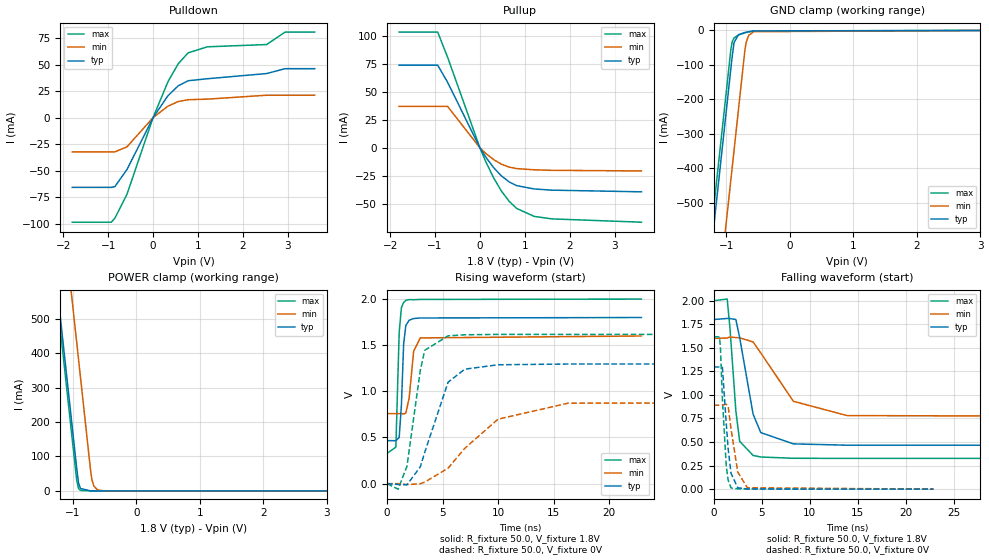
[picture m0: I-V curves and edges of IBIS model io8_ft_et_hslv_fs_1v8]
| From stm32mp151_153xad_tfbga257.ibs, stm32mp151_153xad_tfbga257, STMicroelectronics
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[Model]   io8_ft_et_hslv_fs_1v8
Model_type I/O
Polarity   Non-Inverting
Enable   Active-Low
| CAP_THRESHOLD on pad IOFT is "UDTCAPC" :
| Rising=20.00f vddiom   Falling=80.00f vddiom
| C_comp min and max val. don't necessarily correlate with the min and max pvt
| but are the smallest and greatest pad capacitance found.
| var   typ   min   max
C_comp   3.43098pF  3.42356pF  3.49920pF
|C_comp_pullup   1.96775pF  2.05990pF  1.91900pF
|C_comp_pulldown   1.46323pF  1.36366pF  1.58020pF
Vinl = 640.0mV
Vinh = 1.2V
Vmeas = 900.0mV   | Reference voltage for timing measurements
Cref  = 50.0pF   | Timing specification test load capacitance value
Rref  = 100.0MOhm   | Timing specification test load resistance value
Vref  = 0V   | Timing specification test load voltage
[Model Spec]
| TIME_THRESHOLD on pin ZIV11 is "CMOS" :
| Rising=40.00f vdd   Falling=60.00f vdd
Vinl 738.60000mV 665.60000mV 824.60000mV
Vinh 1.04640V 924.40000mV 1.13940V
| variable   typ   min   max
[Temperature Range] 25.0 140.0 -40.0
| variable   typ   min   max
[Voltage Range] 1.8V 1.6V 2.0V
| variable   typ   min   max
[POWER Clamp Reference] 1.8V 1.6V 2.0V
| variable   typ   min   max
[GND Clamp Reference] 0V 0V 0V
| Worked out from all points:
|   slope of the pulldown table from 0 to 0.27 V, typ, clamps not added: 16 ohm
|   slope of the pullup table from 0 to 0.27 V, typ, clamps not added: 17 ohm
|   GND clamp passes 1 mA (typ) near -0.52 V on its own axis
|   POWER clamp passes 1 mA (typ) near -0.83 V on its own axis
|   rising waveform, R_fixture 50.0, V_fixture 1.8V: 20-80 % time 262ps typ, 401ps min, 226ps max; typ from 0.466 V to 1.8 V
|   falling waveform, R_fixture 50.0, V_fixture 1.8V: 20-80 % time 1.42ns typ, 3.39ns min, 737ps max; typ from 1.8 V to 0.466 V
|   rising waveform, R_fixture 50.0, V_fixture 0V: 20-80 % time 2.03ns typ, 4.63ns min, 1.08ns max; typ from 0 V to 1.3 V
|   falling waveform, R_fixture 50.0, V_fixture 0V: 20-80 % time 599ps typ, 793ps min, 479ps max; typ from 1.3 V to 0 V
[POWER Clamp]
-1.8V     1.529A     1.894A     1.494A
-940mV    66.83mA    432.1mA    31.5mA
-910mV    22.88mA    381.1mA    7.077mA
-880mV    7.117mA    330.1mA    1.59mA
-720mV    14.05uA    58.12mA    554nA
-700mV    6.453uA    33.14mA    205nA
-670mV    2.008uA    14.27mA    46.29nA
-610mV    195.5nA    2.645mA    2.508nA
-500mV    3.96nA     120.4uA    139.7pA
3.6V      0A         0A         0A
[GND Clamp]
-1.8V     -1.588A    -1.91A     -1.533A
-1.26V    -670.3mA   -992.4mA   -614.9mA
-1.2V     -568.3mA   -890.4mA   -512.9mA
-930mV    -109.3mA   -431.4mA   -53.86mA
-910mV    -75.33mA   -397.4mA   -32.91mA
-880mV    -34.88mA   -346.4mA   -21.56mA
-810mV    -12.56mA   -227.4mA   -13.55mA
-710mV    -6.275mA   -57.63mA   -7.234mA
-690mV    -5.461mA   -35.21mA   -6.234mA
-650mV    -4.039mA   -14.43mA   -4.463mA
-570mV    -1.908mA   -3.832mA   -1.869mA
3.6V      5.084nA    1.599uA    245.6pA
| variable   typ   min   max
[Pullup Reference] 1.8V 1.6V 2.0V
| variable   typ   min   max
[Pulldown Reference] 0V 0V 0V
[Pullup]
-1.8V     73.6mA     36.9mA     103.1mA
-940mV    73.6mA     36.9mA     103.1mA
-720mV    58.44mA    36.9mA     80.78mA
0V        7.41pA     1.331nA    4.294pA
140mV     -8.79mA    -5.35mA    -13.15mA
310mV     -17.86mA   -10.65mA   -27.08mA
480mV     -25.08mA   -14.62mA   -38.59mA
650mV     -30.37mA   -17.22mA   -47.59mA
820mV     -33.72mA   -18.55mA   -54.08mA
1.21V     -36.68mA   -19.61mA   -61.13mA
1.6V      -37.75mA   -20.08mA   -63.35mA
3.6V      -39.24mA   -20.63mA   -66.3mA
[Pulldown]
-1.8V     -65.8mA    -32.31mA   -98.64mA
-930mV    -65.8mA    -32.31mA   -98.64mA
-850mV    -65.04mA   -32.31mA   -94.81mA
-580mV    -48.83mA   -27.49mA   -72.14mA
0V        0A         -3pA       0A
330mV     20.59mA    10.79mA    33.74mA
560mV     30.02mA    15.15mA    50.81mA
780mV     34.81mA    16.9mA     61.1mA
1.21V     36.69mA    17.44mA    66.81mA
2.53V     41.58mA    21.14mA    68.95mA
2.94V     46.18mA    21.14mA    80.69mA
3.6V      46.18mA    21.14mA    80.69mA
[Ramp]
dV/dt_r 777.92791mV/2.02837ns 534.21504mV/4.63418ns 970.12816mV/1.08189ns
dV/dt_f 800.59662mV/1.41649ns 504.71748mV/3.38638ns 1.00395V/732.27748ps
R_load = 50.0
| Removed startup time: 0s 0s 0s  .
| Removed end time: 22.9ns.
[Rising Waveform]
R_fixture   = 50.0
V_fixture   = 1.8V
V_fixture_min = 1.6V
V_fixture_max = 2.0V
0s        465.7mV    758.8mV    326.7mV
800ps     465.4mV    758.9mV    395.8mV
1.1ns     499.2mV    758.9mV    1.64V
1.3ns     850.8mV    759.2mV    1.907V
1.5ns     1.512V     754.2mV    1.963V
1.7ns     1.714V     764.7mV    1.986V
2ns       1.771V     930.4mV    1.994V
2.4ns     1.789V     1.434V     1.993V
3ns       1.795V     1.579V     1.996V
22.9ns    1.8V       1.6V       2V
| Removed startup time: 0s 0s 0s  .
| Removed end time: 99.9ns.
[Falling Waveform]
R_fixture   = 50.0
V_fixture   = 1.8V
V_fixture_min = 1.6V
V_fixture_max = 2.0V
0s        1.8V       1.6V       2V
1.4ns     1.811V     1.603V     2.017V
1.7ns     1.81V      1.615V     1.695V
2.3ns     1.8V       1.608V     831.8mV
2.7ns     1.608V     1.606V     508mV
4.1ns     795.5mV    1.562V     357.7mV
4.9ns     600.2mV    1.445V     341.4mV
8.3ns     480.5mV    932.2mV    327.7mV
13.9ns    466.5mV    780.6mV    326.7mV
99.9ns    465.7mV    758.8mV    326.8mV
| Removed startup time: 0s 0s 0s  .
| Removed end time: 99.9ns.
[Rising Waveform]
R_fixture   = 50.0
V_fixture   = 0V
V_fixture_min = 0V
V_fixture_max = 0V
0s        100.1nV    -275.4nV   -4.987uV
1ns       -9.304mV   -93.83uV   -60.01mV
1.8ns     -12.88mV   -10.38mV   188.5mV
3ns       181.7mV    -1.667mV   1.228V
3.4ns     339.4mV    16.35mV    1.445V
5.5ns     1.099V     167.5mV    1.601V
7ns       1.24V      382.3mV    1.613V
10ns      1.288V     698.6mV    1.617V
16.3ns    1.296V     871.6mV    1.617V
99.9ns    1.297V     890.4mV    1.617V
| Removed startup time: 0s 0s 0s  .
| Removed end time: 22.9ns.
[Falling Waveform]
R_fixture   = 50.0
V_fixture   = 0V
V_fixture_min = 0V
V_fixture_max = 0V
0s        1.297V     890.4mV    1.617V
600ps     1.296V     890.5mV    1.615V
700ps     1.298V     890.5mV    1.49V
900ps     1.291V     890.6mV    953.1mV
1.3ns     697.7mV    901.5mV    249mV
1.5ns     428.2mV    878.7mV    95.13mV
1.8ns     167.9mV    637.3mV    12.87mV
2.5ns     14.43mV    181.4mV    2.639mV
3.5ns     2.73mV     15.03mV    1.331mV
22.9ns    999.6nV    9.911uV    -8.613nV
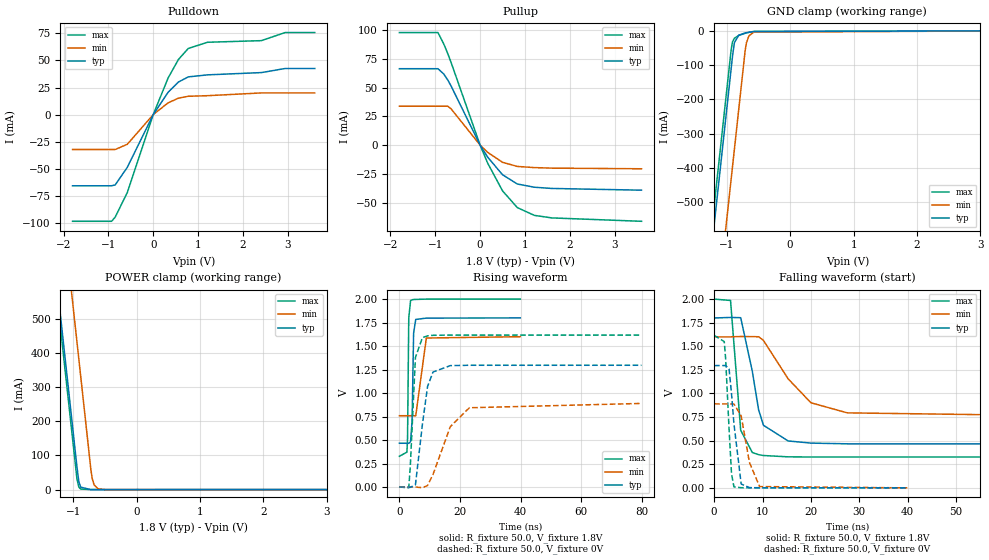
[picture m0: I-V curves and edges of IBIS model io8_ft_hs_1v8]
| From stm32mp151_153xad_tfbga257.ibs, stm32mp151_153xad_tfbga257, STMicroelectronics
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[Model]   io8_ft_hs_1v8
Model_type I/O
Polarity   Non-Inverting
Enable   Active-Low
| CAP_THRESHOLD on pad IOFT is "UDTCAPC" :
| Rising=20.00f vddiom   Falling=80.00f vddiom
| C_comp min and max val. don't necessarily correlate with the min and max pvt
| but are the smallest and greatest pad capacitance found.
| var   typ   min   max
C_comp   3.43303pF  3.42726pF  3.49995pF
|C_comp_pullup   1.98355pF  2.07755pF  1.93335pF
|C_comp_pulldown   1.44948pF  1.34971pF  1.56660pF
Vinl = 640.0mV
Vinh = 1.2V
Vmeas = 900.0mV   | Reference voltage for timing measurements
Cref  = 50.0pF   | Timing specification test load capacitance value
Rref  = 100.0MOhm   | Timing specification test load resistance value
Vref  = 0V   | Timing specification test load voltage
[Model Spec]
| TIME_THRESHOLD on pin ZIV11 is "CMOS" :
| Rising=40.00f vdd   Falling=60.00f vdd
Vinl 738.60000mV 665.60000mV 824.60000mV
Vinh 1.04640V 924.40000mV 1.13940V
| variable   typ   min   max
[Temperature Range] 25.0 140.0 -40.0
| variable   typ   min   max
[Voltage Range] 1.8V 1.6V 2.0V
| variable   typ   min   max
[POWER Clamp Reference] 1.8V 1.6V 2.0V
| variable   typ   min   max
[GND Clamp Reference] 0V 0V 0V
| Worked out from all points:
|   slope of the pulldown table from 0 to 0.27 V, typ, clamps not added: 16 ohm
|   slope of the pullup table from 0 to 0.27 V, typ, clamps not added: 17 ohm
|   GND clamp passes 1 mA (typ) near -0.52 V on its own axis
|   POWER clamp passes 1 mA (typ) near -0.83 V on its own axis
|   rising waveform, R_fixture 50.0, V_fixture 1.8V: 20-80 % time 390ps typ, 807ps min, 283ps max; typ from 0.466 V to 1.8 V
|   falling waveform, R_fixture 50.0, V_fixture 1.8V: 20-80 % time 2.78ns typ, 6.86ns min, 1.4ns max; typ from 1.8 V to 0.466 V
|   rising waveform, R_fixture 50.0, V_fixture 0V: 20-80 % time 2.79ns typ, 6.53ns min, 1.35ns max; typ from 0 V to 1.3 V
|   falling waveform, R_fixture 50.0, V_fixture 0V: 20-80 % time 1.34ns typ, 2.04ns min, 926ps max; typ from 1.3 V to 0 V
[POWER Clamp]
-1.8V     1.529A     1.894A     1.494A
-940mV    66.83mA    432.1mA    31.5mA
-910mV    22.88mA    381.1mA    7.077mA
-880mV    7.117mA    330.1mA    1.59mA
-720mV    14.05uA    58.12mA    554nA
-700mV    6.453uA    33.14mA    205nA
-670mV    2.008uA    14.27mA    46.28nA
-610mV    195.3nA    2.645mA    2.497nA
-500mV    3.855nA    120.4uA    130.5pA
3.6V      0A         0A         0A
[GND Clamp]
-1.8V     -1.588A    -1.91A     -1.533A
-1.26V    -670.3mA   -992.4mA   -614.9mA
-1.2V     -568.3mA   -890.4mA   -512.9mA
-930mV    -109.3mA   -431.4mA   -53.86mA
-910mV    -75.33mA   -397.4mA   -32.91mA
-880mV    -34.88mA   -346.4mA   -21.56mA
-810mV    -12.56mA   -227.4mA   -13.55mA
-710mV    -6.275mA   -57.63mA   -7.234mA
-690mV    -5.461mA   -35.21mA   -6.234mA
-650mV    -4.039mA   -14.43mA   -4.463mA
-570mV    -1.908mA   -3.832mA   -1.869mA
3.6V      5.036nA    1.588uA    245.5pA
| variable   typ   min   max
[Pullup Reference] 1.8V 1.6V 2.0V
| variable   typ   min   max
[Pulldown Reference] 0V 0V 0V
[Pullup]
-1.8V     66.33mA    33.75mA    97.74mA
-940mV    66.33mA    33.75mA    97.74mA
-810mV    61.74mA    33.75mA    87.84mA
-720mV    56.47mA    33.75mA    79.39mA
-650mV    51.56mA    31.62mA    72.14mA
0V        7.41pA     1.33nA     4.294pA
170mV     -10.52mA   -6.378mA   -15.77mA
500mV     -25.79mA   -14.99mA   -39.76mA
830mV     -33.83mA   -18.58mA   -54.35mA
1.21V     -36.65mA   -19.59mA   -61.09mA
1.6V      -37.71mA   -20.06mA   -63.31mA
3.6V      -39.21mA   -20.61mA   -66.25mA
[Pulldown]
-1.8V     -65.8mA    -32.31mA   -98.64mA
-930mV    -65.8mA    -32.31mA   -98.64mA
-850mV    -65.04mA   -32.31mA   -94.81mA
-580mV    -48.83mA   -27.49mA   -72.14mA
0V        0A         0A         0A
330mV     20.59mA    10.79mA    33.74mA
560mV     30.02mA    15.15mA    50.81mA
780mV     34.81mA    16.9mA     61.1mA
1.21V     36.69mA    17.44mA    66.81mA
2.41V     38.78mA    19.98mA    68.31mA
2.94V     42.55mA    19.98mA    75.77mA
3.6V      42.55mA    19.98mA    75.77mA
[Ramp]
dV/dt_r 777.74465mV/2.79218ns 533.89794mV/6.53451ns 970.01034mV/1.35361ns
dV/dt_f 800.598mV/2.77438ns 504.72922mV/6.86444ns 1.00395V/1.39597ns
R_load = 50.0
| Removed startup time: 0s 0s 0s  .
| Removed end time: 39.9ns.
[Rising Waveform]
R_fixture   = 50.0
V_fixture   = 1.8V
V_fixture_min = 1.6V
V_fixture_max = 2.0V
0s        465.7mV    758.8mV    326.8mV
2.5ns     465.7mV    758.8mV    371.3mV
2.7ns     465.7mV    758.8mV    526.8mV
3.1ns     464.9mV    758.8mV    1.799V
3.7ns     482.8mV    758.8mV    1.985V
4.2ns     708.1mV    758.8mV    1.993V
4.7ns     1.639V     758.9mV    1.996V
5.4ns     1.784V     758mV      1.997V
8.9ns     1.798V     1.586V     2V
39.9ns    1.8V       1.6V       2V
| Removed startup time: 0s 0s 0s  .
| Removed end time: 79.9ns.
[Falling Waveform]
R_fixture   = 50.0
V_fixture   = 1.8V
V_fixture_min = 1.6V
V_fixture_max = 2.0V
0s        1.8V       1.6V       2V
3.4ns     1.806V     1.6V       1.986V
5.5ns     1.803V     1.604V     610.5mV
7.9ns     1.234V     1.603V     374mV
9.2ns     825.6mV    1.601V     351.8mV
10.2ns    663mV      1.562V     342.8mV
15.3ns    497mV      1.155V     328.7mV
20ns      474.3mV    901.8mV    327mV
27.5ns    466.7mV    794.7mV    326.8mV
79.9ns    465.7mV    758.8mV    326.8mV
| Removed startup time: 0s 0s 0s  .
| Removed end time: 79.9ns.
[Rising Waveform]
R_fixture   = 50.0
V_fixture   = 0V
V_fixture_min = 0V
V_fixture_max = 0V
0s        69.77nV    639.1nV    99.37nV
3.1ns     201.2uV    665.7nV    -9.143mV
3.6ns     -3.771mV   740.3nV    217.4mV
5.3ns     23.01mV    145.7uV    1.379V
7.6ns     665.8mV    -8.11mV    1.59V
9.3ns     1.069V     15.34mV    1.609V
11.1ns    1.224V     133.5mV    1.615V
16.8ns    1.292V     642.6mV    1.617V
23.1ns    1.296V     843.5mV    1.617V
79.9ns    1.296V     889.8mV    1.617V
| Removed startup time: 0s 0s 0s  .
| Removed end time: 39.9ns.
[Falling Waveform]
R_fixture   = 50.0
V_fixture   = 0V
V_fixture_min = 0V
V_fixture_max = 0V
0s        1.296V     889.9mV    1.617V
2.1ns     1.296V     889.9mV    1.55V
2.4ns     1.296V     889.9mV    1.359V
3.1ns     1.258V     889.9mV    617mV
3.6ns     1.001V     889.9mV    151.1mV
4.1ns     680mV      889.6mV    10.38mV
5.6ns     40.3mV     762.2mV    1.601mV
7.3ns     2.759mV    269.1mV    761.2uV
9.4ns     1.116mV    13.7mV     339.6uV
39.9ns    -1.056uV   11.69uV    88.63nV
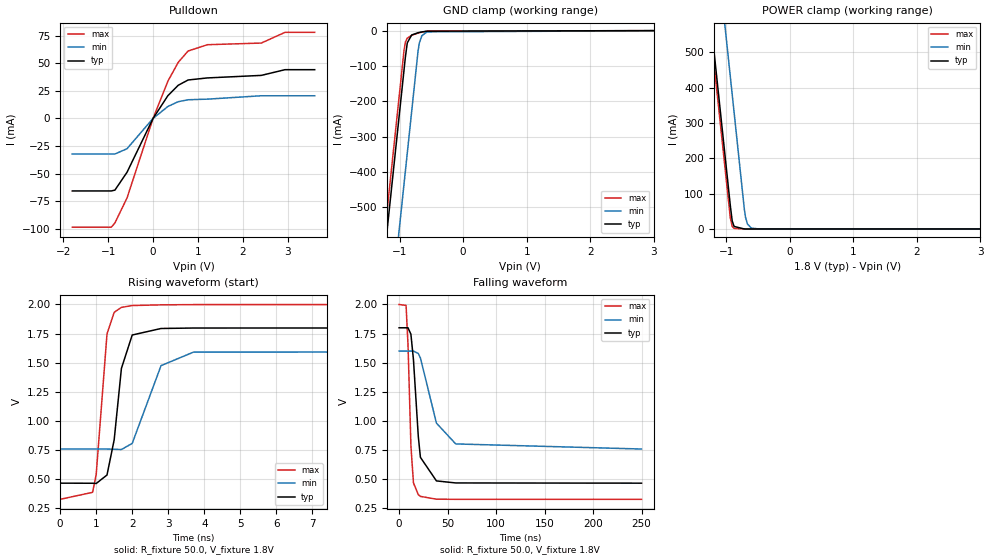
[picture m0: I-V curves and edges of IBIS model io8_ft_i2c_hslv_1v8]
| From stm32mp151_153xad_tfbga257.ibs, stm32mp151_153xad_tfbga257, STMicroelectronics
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[Model]   io8_ft_i2c_hslv_1v8
Model_type I/O_open_drain
Polarity   Non-Inverting
Enable   Active-Low
| CAP_THRESHOLD on pad IOFT is "UDTCAPC" :
| Rising=20.00f vddiom   Falling=80.00f vddiom
| C_comp min and max val. don't necessarily correlate with the min and max pvt
| but are the smallest and greatest pad capacitance found.
| var   typ   min   max
C_comp   3.45148pF  3.42528pF  3.49355pF
|C_comp_pulldown   3.45148pF  3.42528pF  3.49355pF
Vinl = 640.0mV
Vinh = 1.2V
Vmeas = 900.0mV   | Reference voltage for timing measurements
Cref  = 50.0pF   | Timing specification test load capacitance value
Rref  = 100.0MOhm   | Timing specification test load resistance value
Vref  = 900.0mV   | Timing specification test load voltage
[Model Spec]
| TIME_THRESHOLD on pin ZIV11 is "CMOS" :
| Rising=40.00f vdd   Falling=60.00f vdd
Vinl 738.60000mV 665.60000mV 824.60000mV
Vinh 1.04740V 925.40000mV 1.14040V
| variable   typ   min   max
[Temperature Range] 25.0 140.0 -40.0
| variable   typ   min   max
[Voltage Range] 1.8V 1.6V 2.0V
| variable   typ   min   max
[POWER Clamp Reference] 1.8V 1.6V 2.0V
| variable   typ   min   max
[GND Clamp Reference] 0V 0V 0V
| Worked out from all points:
|   slope of the pulldown table from 0 to 0.27 V, typ, clamps not added: 16 ohm
|   GND clamp passes 1 mA (typ) near -0.52 V on its own axis
|   POWER clamp passes 1 mA (typ) near -0.83 V on its own axis
|   rising waveform, R_fixture 50.0, V_fixture 1.8V: 20-80 % time 303ps typ, 522ps min, 243ps max; typ from 0.466 V to 1.8 V
|   falling waveform, R_fixture 50.0, V_fixture 1.8V: 20-80 % time 6.49ns typ, 15.7ns min, 3.61ns max; typ from 1.8 V to 0.466 V
[POWER Clamp]
-1.8V     1.529A     1.894A     1.494A
-940mV    66.83mA    432.1mA    31.5mA
-910mV    22.88mA    381.1mA    7.077mA
-880mV    7.117mA    330.1mA    1.59mA
-720mV    14.05uA    58.12mA    554nA
-700mV    6.453uA    33.14mA    205nA
-670mV    2.008uA    14.27mA    46.28nA
-610mV    195.3nA    2.645mA    2.496nA
-500mV    3.825nA    120.4uA    129.9pA
3.6V      0A         0A         0A
[GND Clamp]
-1.8V     -1.588A    -1.91A     -1.533A
-1.26V    -670.3mA   -992.4mA   -614.9mA
-1.2V     -568.3mA   -890.4mA   -512.9mA
-930mV    -109.3mA   -431.4mA   -53.86mA
-910mV    -75.33mA   -397.4mA   -32.91mA
-880mV    -34.88mA   -346.4mA   -21.56mA
-810mV    -12.56mA   -227.4mA   -13.55mA
-710mV    -6.275mA   -57.63mA   -7.234mA
-690mV    -5.461mA   -35.21mA   -6.234mA
-650mV    -4.039mA   -14.43mA   -4.463mA
-570mV    -1.908mA   -3.832mA   -1.869mA
3.6V      5.036nA    1.588uA    245.5pA
| variable   typ   min   max
[Pullup Reference] 1.8V 1.6V 2.0V
| variable   typ   min   max
[Pulldown Reference] 0V 0V 0V
[Pulldown]
-1.8V     -65.8mA    -32.31mA   -98.64mA
-930mV    -65.8mA    -32.31mA   -98.64mA
-850mV    -65.04mA   -32.31mA   -94.81mA
-580mV    -48.83mA   -27.49mA   -72.14mA
0V        0A         -2pA       0A
330mV     20.59mA    10.79mA    33.74mA
560mV     30.02mA    15.15mA    50.81mA
780mV     34.81mA    16.9mA     61.1mA
1.21V     36.69mA    17.44mA    66.81mA
2.41V     38.98mA    20.51mA    68.31mA
2.94V     44.17mA    20.51mA    78.04mA
3.6V      44.17mA    20.51mA    78.04mA
[Ramp]
dV/dt_r 800.58575mV/285.51296ps 504.68813mV/515.06486ps 1.00394V/226.53402ps
dV/dt_f 800.59773mV/6.49286ns 504.7021mV/15.74821ns 1.00395V/3.60901ns
R_load = 50.0
| Removed startup time: 0s 0s 0s  .
| Removed end time: 59.9ns.
[Rising Waveform]
R_fixture   = 50.0
V_fixture   = 1.8V
V_fixture_min = 1.6V
V_fixture_max = 2.0V
0s        465.7mV    758.8mV    326.7mV
900ps     464.8mV    758.9mV    386.8mV
1ns       462.7mV    758.9mV    539.3mV
1.3ns     535.5mV    758.5mV    1.747V
1.5ns     839mV      756.8mV    1.933V
1.7ns     1.451V     754.5mV    1.975V
2ns       1.738V     807.3mV    1.991V
2.8ns     1.794V     1.475V     1.997V
3.7ns     1.798V     1.591V     1.999V
59.9ns    1.8V       1.6V       2V
| Removed startup time: 0s 0s 0s  .
| Removed end time: 249.9ns.
[Falling Waveform]
R_fixture   = 50.0
V_fixture   = 1.8V
V_fixture_min = 1.6V
V_fixture_max = 2.0V
0s        1.8V       1.6V       2V
7.2ns     1.8V       1.6V       1.992V
9.2ns     1.8V       1.6V       1.655V
12.2ns    1.744V     1.6V       788.3mV
14.8ns    1.528V     1.6V       467.8mV
19.8ns    867.6mV    1.579V     366.9mV
22ns      687.3mV    1.541V     352.1mV
38.5ns    485mV      981.3mV    328mV
58.4ns    467.5mV    802.6mV    326.8mV
249.9ns   465.7mV    758.8mV    326.8mV
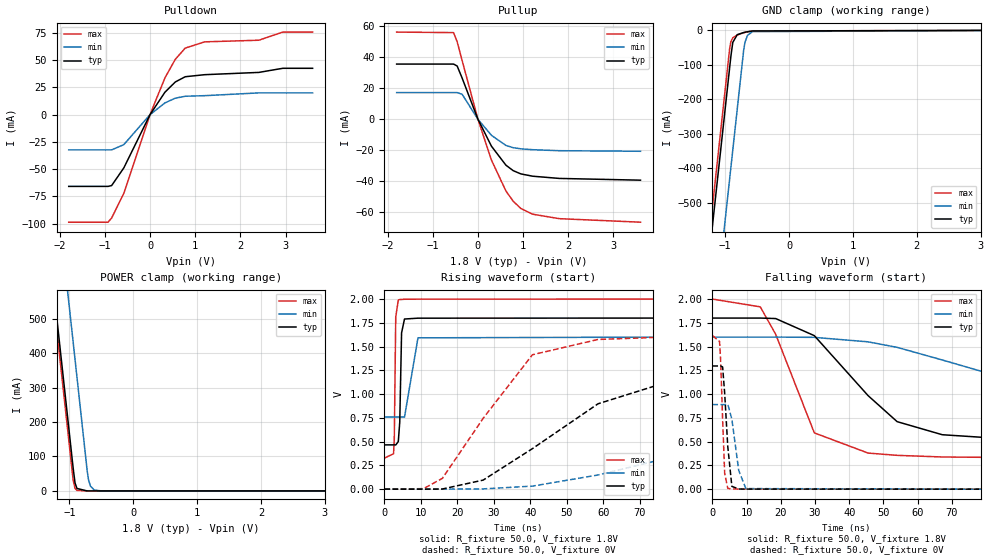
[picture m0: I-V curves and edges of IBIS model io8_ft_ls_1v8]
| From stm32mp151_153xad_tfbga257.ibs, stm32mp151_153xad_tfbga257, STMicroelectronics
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[Model]   io8_ft_ls_1v8
Model_type I/O
Polarity   Non-Inverting
Enable   Active-Low
| CAP_THRESHOLD on pad IOFT is "UDTCAPC" :
| Rising=20.00f vddiom   Falling=80.00f vddiom
| C_comp min and max val. don't necessarily correlate with the min and max pvt
| but are the smallest and greatest pad capacitance found.
| var   typ   min   max
C_comp   3.43303pF  3.42726pF  3.49995pF
|C_comp_pullup   1.98355pF  2.07755pF  1.93335pF
|C_comp_pulldown   1.44948pF  1.34971pF  1.56660pF
Vinl = 640.0mV
Vinh = 1.2V
Vmeas = 900.0mV   | Reference voltage for timing measurements
Cref  = 50.0pF   | Timing specification test load capacitance value
Rref  = 100.0MOhm   | Timing specification test load resistance value
Vref  = 0V   | Timing specification test load voltage
[Model Spec]
| TIME_THRESHOLD on pin ZIV11 is "CMOS" :
| Rising=40.00f vdd   Falling=60.00f vdd
Vinl 738.60000mV 665.60000mV 824.60000mV
Vinh 1.04640V 924.40000mV 1.13940V
| variable   typ   min   max
[Temperature Range] 25.0 140.0 -40.0
| variable   typ   min   max
[Voltage Range] 1.8V 1.6V 2.0V
| variable   typ   min   max
[POWER Clamp Reference] 1.8V 1.6V 2.0V
| variable   typ   min   max
[GND Clamp Reference] 0V 0V 0V
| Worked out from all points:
|   slope of the pulldown table from 0 to 0.27 V, typ, clamps not added: 16 ohm
|   slope of the pullup table from 0 to 0.27 V, typ, clamps not added: 17 ohm
|   GND clamp passes 1 mA (typ) near -0.52 V on its own axis
|   POWER clamp passes 1 mA (typ) near -0.83 V on its own axis
|   rising waveform, R_fixture 50.0, V_fixture 1.8V: 20-80 % time 386ps typ, 812ps min, 279ps max; typ from 0.466 V to 1.8 V
|   falling waveform, R_fixture 50.0, V_fixture 1.8V: 20-80 % time 20.5ns typ, 52.9ns min, 10.5ns max; typ from 1.8 V to 0.466 V
|   rising waveform, R_fixture 50.0, V_fixture 0V: 20-80 % time 31.3ns typ, 68.1ns min, 16.6ns max; typ from 0 V to 1.3 V
|   falling waveform, R_fixture 50.0, V_fixture 0V: 20-80 % time 1.33ns typ, 2.04ns min, 927ps max; typ from 1.3 V to 0 V
[POWER Clamp]
-1.8V     1.529A     1.894A     1.494A
-940mV    66.83mA    432.1mA    31.5mA
-910mV    22.88mA    381.1mA    7.077mA
-880mV    7.117mA    330.1mA    1.59mA
-720mV    14.05uA    58.12mA    554nA
-700mV    6.453uA    33.14mA    205nA
-670mV    2.008uA    14.27mA    46.28nA
-610mV    195.3nA    2.645mA    2.497nA
-500mV    3.855nA    120.4uA    130.5pA
3.6V      0A         0A         0A
[GND Clamp]
-1.8V     -1.588A    -1.91A     -1.533A
-1.26V    -670.3mA   -992.4mA   -614.9mA
-1.2V     -568.3mA   -890.4mA   -512.9mA
-930mV    -109.3mA   -431.4mA   -53.86mA
-910mV    -75.33mA   -397.4mA   -32.91mA
-880mV    -34.88mA   -346.4mA   -21.56mA
-810mV    -12.56mA   -227.4mA   -13.55mA
-710mV    -6.275mA   -57.63mA   -7.234mA
-690mV    -5.461mA   -35.21mA   -6.234mA
-650mV    -4.039mA   -14.43mA   -4.463mA
-570mV    -1.908mA   -3.832mA   -1.869mA
3.6V      5.036nA    1.588uA    245.5pA
| variable   typ   min   max
[Pullup Reference] 1.8V 1.6V 2.0V
| variable   typ   min   max
[Pulldown Reference] 0V 0V 0V
[Pullup]
-1.8V     35.51mA    17.15mA    56.1mA
-540mV    35.51mA    17.15mA    55.76mA
-460mV    34.27mA    17.15mA    49.89mA
-350mV    26.52mA    16.08mA    37.78mA
0V        7.41pA     1.33nA     4.294pA
300mV     -17.37mA   -10.37mA   -26.31mA
620mV     -29.56mA   -16.84mA   -46.16mA
780mV     -33.07mA   -18.31mA   -52.74mA
950mV     -35.16mA   -19.03mA   -57.42mA
1.21V     -36.65mA   -19.59mA   -61.09mA
1.8V      -38.08mA   -20.24mA   -63.98mA
3.6V      -39.21mA   -20.61mA   -66.25mA
[Pulldown]
-1.8V     -65.8mA    -32.31mA   -98.64mA
-930mV    -65.8mA    -32.31mA   -98.64mA
-850mV    -65.04mA   -32.31mA   -94.81mA
-580mV    -48.83mA   -27.49mA   -72.14mA
0V        0A         0A         0A
330mV     20.59mA    10.79mA    33.74mA
560mV     30.02mA    15.15mA    50.81mA
780mV     34.81mA    16.9mA     61.1mA
1.21V     36.69mA    17.44mA    66.81mA
2.41V     38.78mA    19.98mA    68.31mA
2.94V     42.55mA    19.98mA    75.77mA
3.6V      42.55mA    19.98mA    75.77mA
[Ramp]
dV/dt_r 777.74117mV/31.3108ns 533.85108mV/68.09047ns 970.01164mV/16.60492ns
dV/dt_f 800.59647mV/20.47216ns 504.71835mV/52.86349ns 1.00395V/10.47264ns
R_load = 50.0
| Removed startup time: 0s 0s 0s  .
| Removed end time: 79.9ns.
[Rising Waveform]
R_fixture   = 50.0
V_fixture   = 1.8V
V_fixture_min = 1.6V
V_fixture_max = 2.0V
0s        465.7mV    758.8mV    326.8mV
2.5ns     465.7mV    758.8mV    372.2mV
2.7ns     465.7mV    758.8mV    528.3mV
3.1ns     464.7mV    758.8mV    1.811V
3.8ns     500.4mV    758.8mV    1.99V
4.2ns     705.4mV    758.8mV    1.995V
4.7ns     1.644V     758.9mV    1.996V
5.5ns     1.79V      757.2mV    1.998V
9.2ns     1.799V     1.592V     1.999V
79.9ns    1.8V       1.6V       2V
| Removed startup time: 0s 0s 0s  .
| Removed end time: 499.9ns.
[Falling Waveform]
R_fixture   = 50.0
V_fixture   = 1.8V
V_fixture_min = 1.6V
V_fixture_max = 2.0V
0s        1.8V       1.6V       2V
14ns      1.8V       1.6V       1.918V
18.5ns    1.795V     1.6V       1.63V
29.8ns    1.615V     1.597V     592mV
45.5ns    984.5mV    1.55V      379.7mV
54ns      710.3mV    1.492V     355.8mV
67.2ns    572.7mV    1.359V     338.5mV
103.9ns   487.2mV    976.8mV    328.1mV
155.9ns   468.5mV    816.4mV    326.8mV
499.9ns   465.7mV    758.8mV    326.8mV
| Removed startup time: 0s 0s 0s  .
| Removed end time: 499.9ns.
[Rising Waveform]
R_fixture   = 50.0
V_fixture   = 0V
V_fixture_min = 0V
V_fixture_max = 0V
0s        70.65nV    639.3nV    101.1nV
10.7ns    -400.3uV   -253.8uV   4.898mV
15.9ns    1.402mV    -125.8uV   113.4mV
27.1ns    95.32mV    2.513mV    746mV
40.6ns    426.1mV    31.69mV    1.414V
58.6ns    898.1mV    148.8mV    1.575V
84.9ns    1.214V     393.5mV    1.61V
122.8ns   1.282V     675.9mV    1.616V
168.2ns   1.294V     824.8mV    1.617V
499.9ns   1.296V     889.8mV    1.617V
| Removed startup time: 0s 0s 0s  .
| Removed end time: 79.9ns.
[Falling Waveform]
R_fixture   = 50.0
V_fixture   = 0V
V_fixture_min = 0V
V_fixture_max = 0V
0s        1.296V     889.9mV    1.617V
2.1ns     1.296V     889.9mV    1.553V
2.4ns     1.296V     889.9mV    1.369V
3ns       1.286V     889.9mV    736.3mV
3.6ns     1.008V     889.9mV    167.4mV
4.5ns     450.3mV    894.5mV    8.33mV
5.7ns     29.23mV    736.1mV    2.228mV
7.7ns     1.726mV    197.2mV    1.331mV
9.8ns     839.1uV    6.128mV    1.079mV
79.9ns    46.64uV    119.3uV    10.53uV
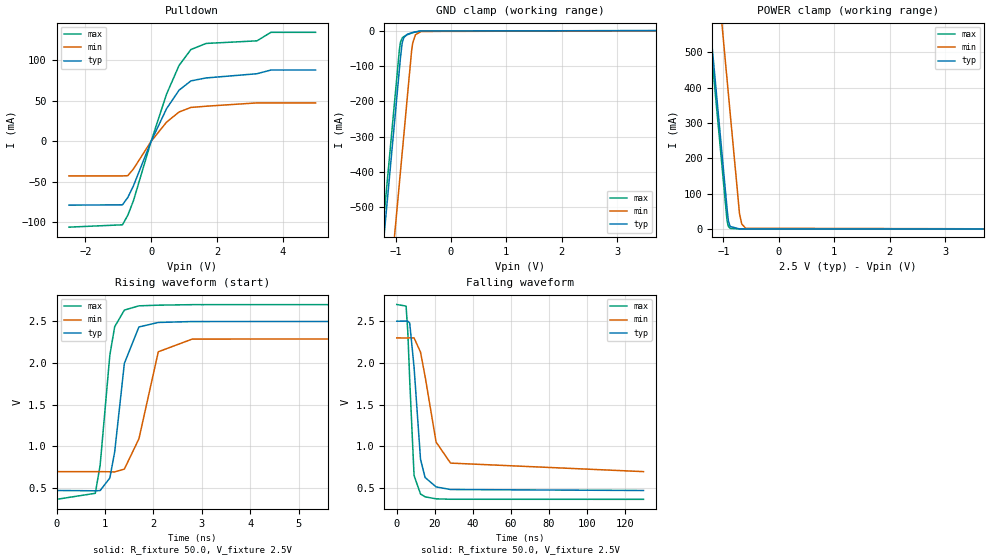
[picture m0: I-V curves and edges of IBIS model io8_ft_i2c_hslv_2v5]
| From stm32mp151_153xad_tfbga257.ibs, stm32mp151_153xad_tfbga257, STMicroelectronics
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[Model]   io8_ft_i2c_hslv_2v5
Model_type I/O_open_drain
Polarity   Non-Inverting
Enable   Active-Low
| CAP_THRESHOLD on pad IOFT is "UDTCAPC" :
| Rising=20.00f vddiom   Falling=80.00f vddiom
| C_comp min and max val. don't necessarily correlate with the min and max pvt
| but are the smallest and greatest pad capacitance found.
| var   typ   min   max
C_comp   3.61949pF  3.58164pF  3.65077pF
|C_comp_pulldown   3.61949pF  3.58164pF  3.65077pF
Vinl = 920.0mV
Vinh = 1.62V
Vmeas = 1.25V   | Reference voltage for timing measurements
Cref  = 50.0pF   | Timing specification test load capacitance value
Rref  = 100.0MOhm   | Timing specification test load resistance value
Vref  = 1.25V   | Timing specification test load voltage
[Model Spec]
| TIME_THRESHOLD on pin ZIV11 is "CMOS" :
| Rising=40.00f vdd   Falling=60.00f vdd
Vinl 1.03860V 964.60000mV 1.11860V
Vinh 1.36440V 1.26340V 1.44240V
| variable   typ   min   max
[Temperature Range] 25.0 140.0 -40.0
| variable   typ   min   max
[Voltage Range] 2.5V 2.3V 2.7V
| variable   typ   min   max
[POWER Clamp Reference] 2.5V 2.3V 2.7V
| variable   typ   min   max
[GND Clamp Reference] 0V 0V 0V
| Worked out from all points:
|   slope of the pulldown table from 0 to 0.375 V, typ, clamps not added: 11.3 ohm
|   GND clamp passes 1 mA (typ) near -0.52 V on its own axis
|   POWER clamp passes 1 mA (typ) near -0.83 V on its own axis
|   rising waveform, R_fixture 50.0, V_fixture 2.5V: 20-80 % time 255ps typ, 328ps min, 233ps max; typ from 0.473 V to 2.5 V
|   falling waveform, R_fixture 50.0, V_fixture 2.5V: 20-80 % time 3.71ns typ, 7.31ns min, 2.47ns max; typ from 2.5 V to 0.473 V
[POWER Clamp]
-2.5V     2.719A     3.084A     2.683A
-1.28V    644.8mA    1.01A      609.5mA
-1.26V    610.8mA    976.1mA    575.5mA
-1.04V    236.8mA    602.1mA    201.5mA
-940mV    66.83mA    432.1mA    31.5mA
-930mV    49.83mA    415.1mA    19.15mA
-910mV    22.88mA    381.1mA    7.077mA
-880mV    7.117mA    330.1mA    1.59mA
-710mV    9.523uA    43.89mA    337nA
-670mV    2.008uA    14.27mA    46.3nA
-600mV    132.9nA    1.998mA    1.599nA
5V        0A         0A         0A
[GND Clamp]
-2.5V     -2.779A    -3.101A    -2.723A
-1.26V    -670.8mA   -992.7mA   -614.5mA
-930mV    -109.8mA   -431.7mA   -53.54mA
-910mV    -75.83mA   -397.7mA   -32.67mA
-880mV    -35.28mA   -346.7mA   -21.39mA
-850mV    -20.07mA   -295.7mA   -16.99mA
-790mV    -10.9mA    -193.7mA   -12.02mA
-710mV    -6.374mA   -57.93mA   -7.219mA
-690mV    -5.545mA   -35.45mA   -6.225mA
-640mV    -3.775mA   -11.96mA   -4.068mA
-540mV    -1.354mA   -2.661mA   -1.223mA
5V        6.965nA    2.133uA    347.4pA
| variable   typ   min   max
[Pullup Reference] 2.5V 2.3V 2.7V
| variable   typ   min   max
[Pulldown Reference] 0V 0V 0V
[Pulldown]
-2.5V     -78.63mA   -42.6mA    -105.8mA
-870mV    -78.28mA   -42.6mA    -102.9mA
-710mV    -69.32mA   -42.37mA   -91.24mA
-540mV    -55.23mA   -34.22mA   -73.64mA
0V        0A         -2pA       0A
470mV     40.29mA    23.69mA    58.27mA
850mV     63.07mA    36.18mA    93.59mA
1.21V     74.52mA    41.78mA    113.2mA
1.67V     78.14mA    43.3mA     120.7mA
3.22V     83.36mA    47.41mA    123.9mA
3.64V     87.89mA    47.41mA    134.4mA
5V        87.89mA    47.41mA    134.4mA
[Ramp]
dV/dt_r 1.21603V/240.53077ps 960.23438mV/318.05663ps 1.39951V/222.49326ps
dV/dt_f 1.21605V/3.71039ns 960.46343mV/7.30327ns 1.39952V/2.47201ns
R_load = 50.0
| Removed startup time: 0s 0s 0s  .
| Removed end time: 35.9ns.
[Rising Waveform]
R_fixture   = 50.0
V_fixture   = 2.5V
V_fixture_min = 2.3V
V_fixture_max = 2.7V
0s        473.2mV    699.2mV    367.4mV
800ps     469.6mV    699.2mV    439.5mV
900ps     472.8mV    699.1mV    776.5mV
1.1ns     622.5mV    697.4mV    2.094V
1.2ns     935.2mV    695.6mV    2.434V
1.4ns     1.995V     729.6mV    2.633V
1.7ns     2.431V     1.092V     2.684V
2.1ns     2.485V     2.134V     2.692V
2.8ns     2.496V     2.286V     2.698V
35.9ns    2.5V       2.3V       2.7V
| Removed startup time: 0s 0s 0s  .
| Removed end time: 129.9ns.
[Falling Waveform]
R_fixture   = 50.0
V_fixture   = 2.5V
V_fixture_min = 2.3V
V_fixture_max = 2.7V
0s        2.5V       2.3V       2.7V
4.9ns     2.501V     2.299V     2.681V
5.8ns     2.5V       2.299V     2.377V
6.8ns     2.479V     2.301V     1.8V
9.1ns     1.949V     2.3V       651.8mV
12.5ns    847.7mV    2.13V      431.3mV
14.9ns    629.1mV    1.839V     397.6mV
20.7ns    516mV      1.053V     373.4mV
28.3ns    485mV      801.2mV    368.4mV
129.9ns   473.2mV    699.2mV    367.5mV
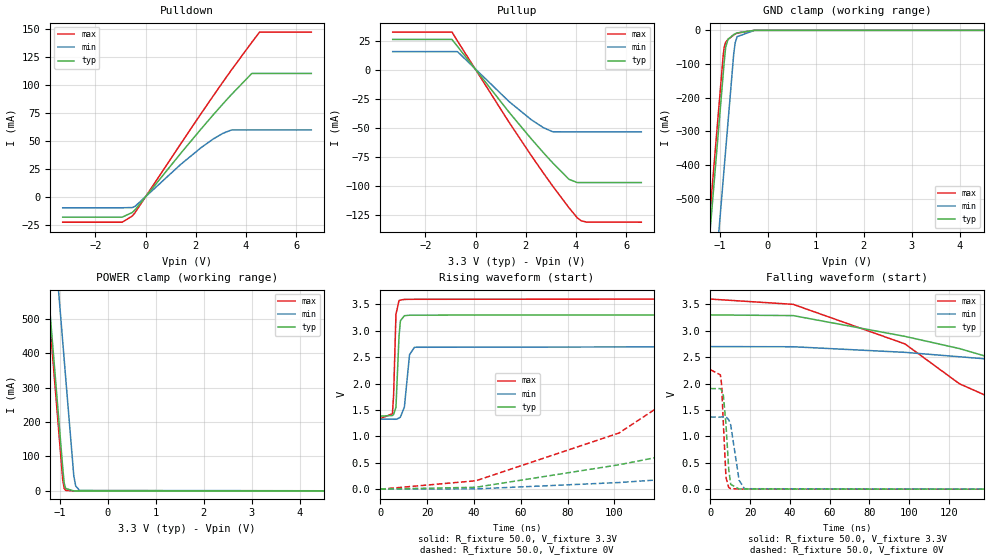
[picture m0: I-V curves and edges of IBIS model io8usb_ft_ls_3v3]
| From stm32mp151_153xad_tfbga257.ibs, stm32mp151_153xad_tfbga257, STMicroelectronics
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[Model]   io8usb_ft_ls_3v3
Model_type I/O
Polarity   Inverting
Enable   Active-Low
| CAP_THRESHOLD on pad DNFT is "UDTCAPC" :
| Rising=20.00f vddiom   Falling=80.00f vddiom
| C_comp min and max val. don't necessarily correlate with the min and max pvt
| but are the smallest and greatest pad capacitance found.
| var   typ   min   max
C_comp   9.38956pF  9.29997pF  9.39296pF
|C_comp_pullup   5.07555pF  4.79110pF  5.26015pF
|C_comp_pulldown   4.31401pF  4.50887pF  4.13281pF
Vinl = 1.08V
Vinh = 2.16V
Vmeas = 1.65V   | Reference voltage for timing measurements
Cref  = 50.0pF   | Timing specification test load capacitance value
Rref  = 100.0MOhm   | Timing specification test load resistance value
Vref  = 0V   | Timing specification test load voltage
[Model Spec]
| TIME_THRESHOLD on pin ZINV11 is "CMOS" :
| Rising=40.00f vdd   Falling=60.00f vdd
Vinl 1.36060V 1.12960V 1.47360V
Vinh 1.71640V 1.45140V 1.83040V
| variable   typ   min   max
[Temperature Range] 25.0 140.0 -40.0
| variable   typ   min   max
[Voltage Range] 3.3V 2.7V 3.6V
| variable   typ   min   max
[POWER Clamp Reference] 3.3V 2.7V 3.6V
| variable   typ   min   max
[GND Clamp Reference] 0V 0V 0V
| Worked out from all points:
|   slope of the pulldown table from 0 to 0.495 V, typ, clamps not added: 35.9 ohm
|   slope of the pullup table from 0 to 0.495 V, typ, clamps not added: 36.4 ohm
|   GND clamp passes 1 mA (typ) near -0.46 V on its own axis
|   POWER clamp passes 1 mA (typ) near -0.83 V on its own axis
|   rising waveform, R_fixture 50.0, V_fixture 3.3V: 20-80 % time 983ps typ, 1.63ns min, 824ps max; typ from 1.38 V to 3.3 V
|   falling waveform, R_fixture 50.0, V_fixture 3.3V: 20-80 % time 95.3ns typ, 181ns min, 67.4ns max; typ from 3.3 V to 1.38 V
|   rising waveform, R_fixture 50.0, V_fixture 0V: 20-80 % time 95.4ns typ, 187ns min, 67.1ns max; typ from 0 V to 1.91 V
|   falling waveform, R_fixture 50.0, V_fixture 0V: 20-80 % time 1.93ns typ, 3.05ns min, 1.5ns max; typ from 1.91 V to 0 V
[POWER Clamp]
-3.3V     4.079A     4.444A     4.043A
-1.46V    950.8mA    1.316A     915.5mA
-1.28V    644.8mA    1.01A      609.5mA
-1.27V    627.8mA    993.1mA    592.5mA
-1.05V    253.8mA    619.1mA    218.5mA
-940mV    66.83mA    432.1mA    31.5mA
-910mV    22.88mA    381.1mA    7.077mA
-880mV    7.117mA    330.1mA    1.59mA
-710mV    9.526uA    43.89mA    337.4nA
-670mV    2.011uA    14.27mA    46.75nA
-590mV    93.56nA    1.508mA    1.48nA
6.6V      0A         0A         0A
[GND Clamp]
-3.3V     -4.158A    -4.471A    -4.102A
-1.25V    -672.7mA   -985.8mA   -617.5mA
-1.1V     -417.7mA   -730.8mA   -362.5mA
-930mV    -128.7mA   -441.8mA   -73.47mA
-910mV    -94.71mA   -407.8mA   -49.55mA
-880mV    -50.68mA   -356.8mA   -35.8mA
-830mV    -26.73mA   -271.8mA   -26.74mA
-710mV    -12.44mA   -67.81mA   -13.64mA
-680mV    -10.24mA   -36.49mA   -11.11mA
-640mV    -7.685mA   -18.75mA   -8.114mA
-280mV    -6.923uA   -112uA     -875.7nA
6.6V      21.96nA    7.413uA    1.058nA
| variable   typ   min   max
[Pullup Reference] 3.3V 2.7V 3.6V
| variable   typ   min   max
[Pulldown Reference] 0V 0V 0V
[Pullup]
-3.3V     26.31mA    15.8mA     32.67mA
-940mV    26.31mA    15.8mA     32.67mA
-720mV    20.29mA    15.8mA     24.95mA
1.33V     -36.39mA   -27.23mA   -45.07mA
2.21V     -59.26mA   -42.82mA   -73.67mA
2.7V      -71.39mA   -49.81mA   -88.96mA
3.07V     -80.17mA   -53.34mA   -100.2mA
3.72V     -94.43mA   -53.42mA   -118.9mA
4.05V     -97.17mA   -53.42mA   -127.7mA
4.21V     -97.19mA   -53.42mA   -130.2mA
4.42V     -97.19mA   -53.42mA   -131.3mA
6.6V      -97.19mA   -53.42mA   -131.4mA
[Pulldown]
-3.3V     -18.2mA    -9.824mA   -22.72mA
-930mV    -18.2mA    -9.824mA   -22.72mA
-530mV    -14.04mA   -9.633mA   -17.24mA
-420mV    -11.67mA   -8.575mA   -14.21mA
1.38V     38.31mA    28.58mA    46.75mA
2.21V     60.64mA    43.95mA    74.4mA
2.7V      73.43mA    51.79mA    90.43mA
3.09V     83.34mA    56.86mA    103mA
3.42V     91.48mA    59.75mA    113.4mA
4.23V     110.3mA    59.75mA    138.2mA
4.54V     110.3mA    59.75mA    147.3mA
6.6V      110.3mA    59.75mA    147.3mA
[Ramp]
dV/dt_r 1.1433V/95.44887ns 819.52193mV/187.29396ns 1.35842V/67.03587ns
dV/dt_f 1.1509V/95.25111ns 825.0661mV/180.68521ns 1.35842V/67.40699ns
R_load = 50.0
| Removed startup time: 0s 0s 0s  .
| Removed end time: 199.9ns.
[Rising Waveform]
R_fixture   = 50.0
V_fixture   = 3.3V
V_fixture_min = 2.7V
V_fixture_max = 3.6V
0s        1.382V     1.325V     1.336V
5.2ns     1.395V     1.325V     1.429V
5.7ns     1.414V     1.324V     1.787V
6.7ns     1.55V      1.324V     3.311V
8ns       2.89V      1.345V     3.572V
8.6ns     3.189V     1.366V     3.582V
10.3ns    3.285V     1.555V     3.593V
12.5ns    3.294V     2.547V     3.595V
14.6ns    3.296V     2.687V     3.596V
199.9ns   3.3V       2.7V       3.6V
| Removed startup time: 0s 0s 0s  .
| Removed end time: 999.9ns.
[Falling Waveform]
R_fixture   = 50.0
V_fixture   = 3.3V
V_fixture_min = 2.7V
V_fixture_max = 3.6V
0s        3.3V       2.7V       3.6V
41.7ns    3.287V     2.697V     3.5V
98ns      2.893V     2.591V     2.75V
125.4ns   2.662V     2.507V     1.995V
137.7ns   2.527V     2.47V      1.79V
190.6ns   1.762V     2.297V     1.356V
264.9ns   1.409V     1.961V     1.336V
342.3ns   1.382V     1.562V     1.336V
444.4ns   1.382V     1.365V     1.336V
999.9ns   1.382V     1.325V     1.336V
| Removed startup time: 0s 0s 0s  .
| Removed end time: 999.9ns.
[Rising Waveform]
R_fixture   = 50.0
V_fixture   = 0V
V_fixture_min = 0V
V_fixture_max = 0V
0s        35.37nV    1.99uV     48.78nV
40.9ns    36.15mV    5.371mV    159.3mV
102ns     462.4mV    125.6mV    1.064V
120.1ns   620mV      180.4mV    1.594V
137ns     811.7mV    231.9mV    1.865V
189.4ns   1.543V     399.6mV    2.235V
263ns     1.876V     713.5mV    2.263V
345.7ns   1.904V     1.122V     2.264V
428.3ns   1.905V     1.307V     2.264V
999.9ns   1.905V     1.366V     2.264V
| Removed startup time: 0s 0s 0s  .
| Removed end time: 199.9ns.
[Falling Waveform]
R_fixture   = 50.0
V_fixture   = 0V
V_fixture_min = 0V
V_fixture_max = 0V
0s        1.905V     1.366V     2.264V
5.1ns     1.904V     1.366V     2.164V
5.7ns     1.872V     1.367V     1.982V
6.6ns     1.774V     1.37V      1.227V
7.9ns     1.227V     1.371V     221.7mV
9.3ns     368.8mV    1.314V     29.81mV
10.3ns    90.28mV    1.212V     10.63mV
14.5ns    3.781mV    170.7mV    3.57mV
17.2ns    2.732mV    8.377mV    3.058mV
199.9ns   4.548uV    88.08uV    1.512uV
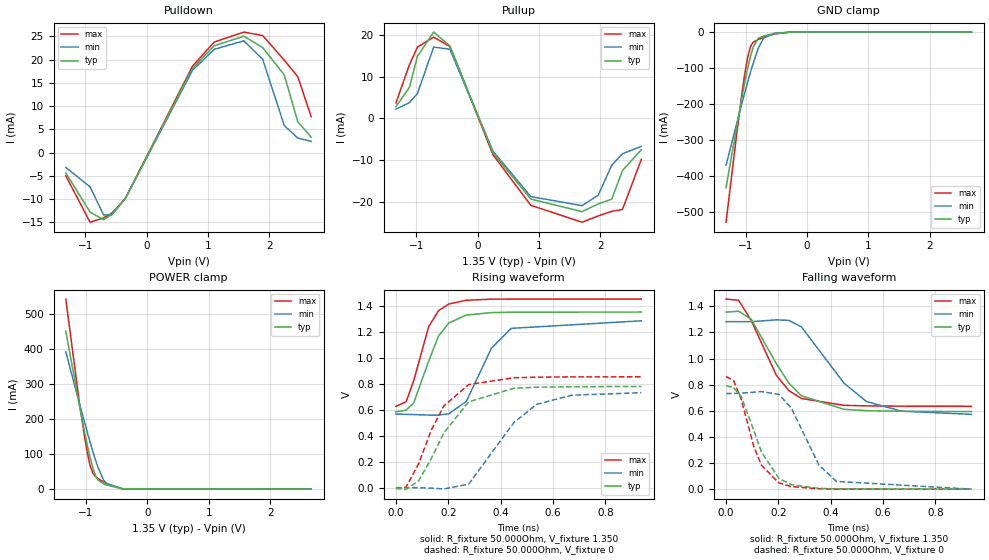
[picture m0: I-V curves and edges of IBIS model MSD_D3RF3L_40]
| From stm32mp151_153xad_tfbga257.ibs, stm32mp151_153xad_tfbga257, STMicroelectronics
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[Model] MSD_D3RF3L_40
Model_type   I/O
C_comp 2.247pF   2.166pF   2.364pF
Vinh = 810.000mV
Vinl = 540.000mV
Vmeas = 675.000mV
Vref = 675.000mV
[Model Spec]
Vinh   810.000mV   777.000mV   860.000mV
Vinl   540.000mV   507.000mV   590.000mV
Vmeas   675.000mV   642.000mV   725.000mV
Vref   675.000mV   642.000mV   725.000mV
[Temperature Range]   25.000   125.000   -40.000
[Voltage Range]   1.350V   1.283V   1.450V
[GND Clamp Reference]   0.00V   0.00V   0.00V
[Pulldown Reference]   0.00V   0.00V   0.00V
[POWER Clamp Reference]   1.350V   1.283V   1.450V
[Pullup Reference]   1.350V   1.283V   1.450V
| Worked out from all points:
|   slope of the pulldown table from 0 to 0.203 V, typ, clamps not added: 35.7 ohm
|   slope of the pullup table from 0 to 0.203 V, typ, clamps not added: 29.7 ohm
|   GND clamp passes 1 mA (typ) near -0.41 V on its own axis
|   POWER clamp passes 1 mA (typ) near -0.41 V on its own axis
|   rising waveform, R_fixture 50.000Ohm, V_fixture 1.350: 20-80 % time 84.9ps typ, 105ps min, 72.6ps max; typ from 0.584 V to 1.35 V
|   rising waveform, R_fixture 50.000Ohm, V_fixture 0: 20-80 % time 138ps typ, 162ps min, 120ps max; typ from -0.006 V to 0.778 V
|   falling waveform, R_fixture 50.000Ohm, V_fixture 1.350: 20-80 % time 142ps typ, 169ps min, 122ps max; typ from 1.35 V to 0.594 V
|   falling waveform, R_fixture 50.000Ohm, V_fixture 0: 20-80 % time 93ps typ, 110ps min, 80.7ps max; typ from 0.792 V to 0 V
[GND Clamp]
-1.318V   -432.8mA   -370.3mA   -528.8mA
-1.142V   -260.6mA   -252.7mA   -280.2mA
-1.055V   -178.2mA   -195.3mA   -165.2mA
-1.011V   -139.1mA   -167.2mA   -114.1mA
-966.7mV  -102.4mA   -139.8mA   -71.26mA
-922.7mV  -69.52mA   -113.2mA   -41.65mA
-878.8mV  -42.91mA   -87.93mA   -28.28mA
-790.9mV  -16.85mA   -43.88mA   -20.2mA
-703mV    -10.77mA   -15.98mA   -14.6mA
-527.3mV  -3.882mA   -3.287mA   -5.181mA
-263.6mV  -34.33uA   -68.91uA   -22.73uA
2.68V     23.22nA    650.7nA    2.894nA
[Power Clamp]
-1.33V    452.1mA    392.8mA    543.8mA
-1.111V   241.8mA    247.2mA    250.6mA
-1.023V   162.2mA    190.3mA    147.9mA
-978.8mV  125.1mA    162.4mA    103.4mA
-934.9mV  91.03mA    135.1mA    67.95mA
-890.9mV  61.68mA    108.8mA    46.37mA
-847mV    39.38mA    83.87mA    35.91mA
-803mV    26.06mA    61.08mA    29.87mA
-715.1mV  15.46mA    26.37mA    20.47mA
-671.2mV  12.27mA    16.31mA    16.36mA
-407.6mV  879.9uA    1.157mA    1.067mA
2.668V    -39.9nA    -766.6nA   -3.595nA
[Pulldown]
-1.318V   -4.4mA     -3.2mA     -5mA
-922.7mV  -12.81mA   -7.4mA     -14.99mA
-703mV    -14.46mA   -13.41mA   -14.07mA
-571.2mV  -13.38mA   -13.44mA   -13.08mA
-351.5mV  -9.983mA   -9.96mA    -9.957mA
747mV     18.14mA    17.69mA    18.58mA
1.098V    22.94mA    22.18mA    23.74mA
1.582V    25.02mA    24.02mA    25.9mA
1.889V    22.57mA    20.05mA    25.16mA
2.241V    16.68mA    5.8mA      19.86mA
2.461V    6.6mA      3.1mA      16.3mA
2.68V     3.3mA      2.4mA      7.7mA
[Pullup]
-1.33V    2.8mA      2.205mA    3.679mA
-1.111V   7.4mA      3.762mA    12.84mA
-978.8mV  14.9mA     5.977mA    17.09mA
-715.1mV  20.68mA    17.1mA     19.47mA
-451.5mV  17.38mA    16.56mA    17.25mA
251.5mV   -8.249mA   -7.869mA   -8.718mA
866.7mV   -19.34mA   -18.75mA   -20.84mA
1.702V    -22.36mA   -20.93mA   -24.89mA
1.965V    -20.5mA    -18.42mA   -23.39mA
2.185V    -19.39mA   -11.25mA   -22.29mA
2.361V    -12.5mA    -8.49mA    -21.82mA
2.668V    -7.5mA     -6.695mA   -9.821mA
[Ramp]
R_load=50.000Ohm
dV/dt_r   460.500mV/111.500ps  434.129mV/134.500ps  500.520mV/96.500ps
dV/dt_f   460.500mV/118.000ps  434.129mV/140.500ps  500.520mV/101.500ps
[Rising waveform]
R_fixture=50.000Ohm
V_fixture=1.350
V_fixture_min=1.283
V_fixture_max=1.450
0s        583.5mV    566.3mV    626mV
39ps      596.1mV    564.1mV    661.4mV
68ps      652.4mV    562.1mV    822.1mV
125ps     972.4mV    558.5mV    1.238V
163ps     1.166V     558.7mV    1.361V
202ps     1.266V     568mV      1.412V
269ps     1.327V     663.1mV    1.441V
365ps     1.346V     1.072V     1.449V
441ps     1.349V     1.225V     1.45V
938ps     1.35V      1.283V     1.45V
[Rising waveform]
R_fixture=50.000Ohm
V_fixture=0
0s        -5.696mV   790.7uV    -5.547mV
39ps      -10.87mV   981.9uV    4.698mV
87ps      53.03mV    351.7uV    186.3mV
135ps     224mV      -2.674mV   442.4mV
183ps     420.7mV    -8.958mV   628.7mV
278ps     660.6mV    27.94mV    792.7mV
451ps     764.4mV    501.5mV    845.4mV
537ps     772.7mV    640.3mV    849.7mV
671ps     776.6mV    711.1mV    852.1mV
938ps     778.5mV    730.5mV    852.6mV
[Falling waveform]
R_fixture=50.000Ohm
V_fixture=1.350
V_fixture_min=1.283
V_fixture_max=1.450
0s        1.355V     1.282V     1.455V
48ps      1.362V     1.282V     1.446V
96ps      1.301V     1.282V     1.292V
192ps     961.5mV    1.296V     872.1mV
240ps     811.8mV    1.292V     754.8mV
288ps     714.8mV    1.242V     694.5mV
451ps     611.2mV    810.9mV    641.7mV
537ps     601mV      670.3mV    637.6mV
671ps     596.3mV    597.1mV    635.2mV
938ps     593.9mV    572.5mV    634.3mV
[Falling waveform]
R_fixture=50.000Ohm
V_fixture=0
0s        791.7mV    732mV      861.9mV
29ps      777.5mV    732.8mV    831.5mV
58ps      707.6mV    735.1mV    687mV
106ps     451mV      742.2mV    327.2mV
135ps     285.3mV    746.9mV    184.1mV
202ps     81.95mV    725.2mV    47.81mV
250ps     33.9mV     619.6mV    19.49mV
355ps     6.379mV    183.8mV    2.936mV
422ps     2.424mV    59.45mV    880.9uV
938ps     7.425uV    129.9uV    5.424uV
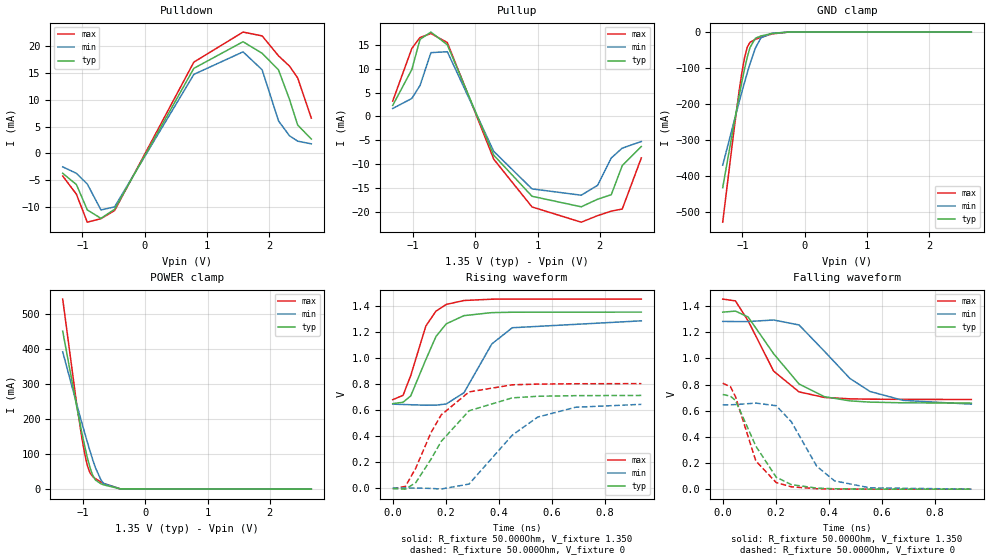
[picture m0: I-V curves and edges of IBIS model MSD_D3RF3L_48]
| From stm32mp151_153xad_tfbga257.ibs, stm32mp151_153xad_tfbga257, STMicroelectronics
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[Model] MSD_D3RF3L_48
Model_type   I/O
C_comp 2.247pF   2.166pF   2.364pF
Vinh = 810.000mV
Vinl = 540.000mV
Vmeas = 675.000mV
Vref = 675.000mV
[Model Spec]
Vinh   810.000mV   777.000mV   860.000mV
Vinl   540.000mV   507.000mV   590.000mV
Vmeas   675.000mV   642.000mV   725.000mV
Vref   675.000mV   642.000mV   725.000mV
[Temperature Range]   25.000   125.000   -40.000
[Voltage Range]   1.350V   1.283V   1.450V
[GND Clamp Reference]   0.00V   0.00V   0.00V
[Pulldown Reference]   0.00V   0.00V   0.00V
[POWER Clamp Reference]   1.350V   1.283V   1.450V
[Pullup Reference]   1.350V   1.283V   1.450V
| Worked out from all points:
|   slope of the pulldown table from 0 to 0.203 V, typ, clamps not added: 42.2 ohm
|   slope of the pullup table from 0 to 0.203 V, typ, clamps not added: 34.5 ohm
|   GND clamp passes 1 mA (typ) near -0.41 V on its own axis
|   POWER clamp passes 1 mA (typ) near -0.41 V on its own axis
|   rising waveform, R_fixture 50.000Ohm, V_fixture 1.350: 20-80 % time 89.7ps typ, 112ps min, 75.7ps max; typ from 0.647 V to 1.35 V
|   rising waveform, R_fixture 50.000Ohm, V_fixture 0: 20-80 % time 150ps typ, 180ps min, 128ps max; typ from -0.005 V to 0.711 V
|   falling waveform, R_fixture 50.000Ohm, V_fixture 1.350: 20-80 % time 156ps typ, 187ps min, 125ps max; typ from 1.35 V to 0.658 V
|   falling waveform, R_fixture 50.000Ohm, V_fixture 0: 20-80 % time 99.2ps typ, 117ps min, 82.2ps max; typ from 0.724 V to 0 V
[GND Clamp]
-1.318V   -432.8mA   -370.3mA   -528.8mA
-1.142V   -260.6mA   -252.7mA   -280.2mA
-1.055V   -178.2mA   -195.3mA   -165.2mA
-1.011V   -139.1mA   -167.2mA   -114.1mA
-966.7mV  -102.4mA   -139.8mA   -71.26mA
-922.7mV  -69.52mA   -113.2mA   -41.65mA
-878.8mV  -42.91mA   -87.93mA   -28.28mA
-790.9mV  -16.85mA   -43.88mA   -20.2mA
-703mV    -10.77mA   -15.98mA   -14.6mA
-527.3mV  -3.882mA   -3.287mA   -5.181mA
-263.6mV  -34.33uA   -68.91uA   -22.73uA
2.68V     23.22nA    650.7nA    2.894nA
[Power Clamp]
-1.33V    452.1mA    392.8mA    543.8mA
-1.111V   241.8mA    247.2mA    250.6mA
-1.023V   162.2mA    190.3mA    147.9mA
-978.8mV  125.1mA    162.4mA    103.4mA
-934.9mV  91.03mA    135.1mA    67.95mA
-890.9mV  61.68mA    108.8mA    46.37mA
-847mV    39.38mA    83.87mA    35.91mA
-803mV    26.06mA    61.08mA    29.87mA
-715.1mV  15.46mA    26.37mA    20.47mA
-671.2mV  12.27mA    16.31mA    16.36mA
-407.6mV  879.9uA    1.157mA    1.067mA
2.668V    -39.9nA    -766.6nA   -3.595nA
[Pulldown]
-1.318V   -3.7mA     -2.5mA     -4.2mA
-1.098V   -5.8mA     -3.7mA     -7.6mA
-922.7mV  -10.54mA   -5.7mA     -12.83mA
-703mV    -12.11mA   -10.54mA   -12.17mA
-483.3mV  -10.41mA   -9.97mA    -10.66mA
790.9mV   15.9mA     14.77mA    17.06mA
1.582V    20.87mA    18.98mA    22.67mA
1.889V    18.71mA    15.63mA    21.96mA
2.153V    15.6mA     6.07mA     18.23mA
2.329V    10.1mA     3.3mA      16.32mA
2.461V    5.3mA      2.3mA      14.1mA
2.68V     2.7mA      1.8mA      6.6mA
[Pullup]
-1.33V    2.3mA      1.652mA    3.207mA
-1.023V   9.8mA      3.762mA    14.2mA
-890.9mV  16.12mA    6.467mA    16.51mA
-715.1mV  17.65mA    13.35mA    17.35mA
-451.5mV  14.99mA    13.54mA    15.46mA
295.4mV   -8.125mA   -7.33mA    -8.964mA
910.6mV   -16.72mA   -15.17mA   -18.95mA
1.702V    -18.92mA   -16.49mA   -22.14mA
1.965V    -17.33mA   -14.42mA   -20.77mA
2.185V    -16.38mA   -8.694mA   -19.82mA
2.361V    -10.3mA    -6.643mA   -19.39mA
2.668V    -6.3mA     -5.248mA   -8.693mA
[Ramp]
R_load=50.000Ohm
dV/dt_r   421.110mV/120.000ps  384.659mV/148.000ps  469.710mV/102.500ps
dV/dt_f   421.110mV/128.000ps  384.629mV/154.000ps  469.710mV/103.500ps
[Rising waveform]
R_fixture=50.000Ohm
V_fixture=1.350
V_fixture_min=1.283
V_fixture_max=1.450
0s        647.4mV    643.7mV    678.1mV
39ps      658.5mV    641.4mV    711.2mV
68ps      707.2mV    639.3mV    862.7mV
125ps     985.6mV    635.6mV    1.243V
163ps     1.162V     636mV      1.357V
202ps     1.26V      645.1mV    1.409V
269ps     1.323V     731.9mV    1.439V
374ps     1.346V     1.106V     1.449V
451ps     1.349V     1.23V      1.45V
938ps     1.35V      1.283V     1.45V
[Rising waveform]
R_fixture=50.000Ohm
V_fixture=0
0s        -4.503mV   658.8uV    -4.42mV
48ps      -8.397mV   866.9uV    12.91mV
87ps      41.84mV    465.5uV    152.9mV
144ps     219.7mV    -2.682mV   424.1mV
183ps     358.1mV    -7.292mV   561.3mV
288ps     593mV      30.81mV    737.7mV
451ps     692mV      405.8mV    792.2mV
547ps     704.2mV    544.6mV    797.5mV
690ps     709mV      620mV      800.3mV
938ps     710.7mV    642.4mV    801.3mV
[Falling waveform]
R_fixture=50.000Ohm
V_fixture=1.350
V_fixture_min=1.283
V_fixture_max=1.450
0s        1.354V     1.283V     1.454V
48ps      1.362V     1.282V     1.44V
96ps      1.317V     1.282V     1.287V
192ps     1.036V     1.294V     903mV
288ps     804.3mV    1.256V     744mV
384ps     707.3mV    1.054V     701.4mV
480ps     675.3mV    846.8mV    690.9mV
556ps     665.8mV    746.9mV    688.3mV
681ps     660.4mV    679mV      686.9mV
938ps     658.3mV    650.4mV    685.8mV
[Falling waveform]
R_fixture=50.000Ohm
V_fixture=0
0s        724mV      644.6mV    810mV
29ps      711.7mV    645.5mV    783.9mV
48ps      679mV      646.8mV    708.7mV
125ps     329.4mV    658.3mV    215.6mV
202ps     91.09mV    638.1mV    50.09mV
259ps     34.84mV    515.6mV    18.14mV
355ps     8.029mV    175mV      3.389mV
422ps     3.07mV     63.37mV    1.047mV
556ps     443uV      10.05mV    172.2uV
938ps     9.733uV    140.4uV    6.86uV
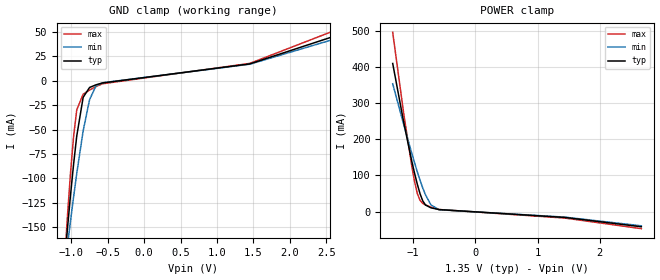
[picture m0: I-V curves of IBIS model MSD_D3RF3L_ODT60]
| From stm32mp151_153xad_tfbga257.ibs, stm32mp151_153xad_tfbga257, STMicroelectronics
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[Model] MSD_D3RF3L_ODT60
Model_type   Input
C_comp 2.201pF   2.154pF   2.263pF
Vinh = 810.000mV
Vinl = 540.000mV
[Temperature Range]   25.000   125.000   -40.000
[Voltage Range]   1.350V   1.283V   1.450V
[GND Clamp Reference]   0.00V   0.00V   0.00V
[POWER Clamp Reference]   1.350V   1.283V   1.450V
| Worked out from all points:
|   GND clamp passes 1 mA (typ) near -0.48 V on its own axis
|   POWER clamp passes 1 mA (typ) near -0.20 V on its own axis
[GND Clamp]
-1.318V   -399.5mA   -339.2mA   -490.1mA
-1.098V   -193.9mA   -198.9mA   -195.7mA
-1.055V   -155.7mA   -171.8mA   -144.1mA
-1.011V   -119.5mA   -145.3mA   -97.39mA
-966.7mV  -86.12mA   -119.6mA   -57.63mA
-922.7mV  -56.68mA   -95.1mA    -29.86mA
-834.9mV  -17.04mA   -51.36mA   -13.76mA
-747mV    -6.894mA   -19.43mA   -9.56mA
-659.1mV  -4.192mA   -5.286mA   -6.03mA
-571.2mV  -2.301mA   -2.087mA   -3.13mA
1.45V     17.25mA    16.93mA    17.77mA
2.68V     47.37mA    44.21mA    53.39mA
[Power Clamp]
-1.33V    409.1mA    353.1mA    494.9mA
-1.155V   248.5mA    241.6mA    273.1mA
-1.023V   139mA      160.9mA    125.5mA
-978.8mV  106.2mA    135.2mA    83.6mA
-934.9mV  76.12mA    110.4mA    50.6mA
-890.9mV  49.81mA    87.04mA    31.29mA
-847mV    29.87mA    65.52mA    22.87mA
-803mV    18.41mA    46.44mA    18.65mA
-715.1mV  10.69mA    18.69mA    12.6mA
-583.3mV  5.781mA    5.363mA    5.989mA
1.438V    -15.9mA    -15.05mA   -17.61mA
2.668V    -41.64mA   -39mA      -46.87mA
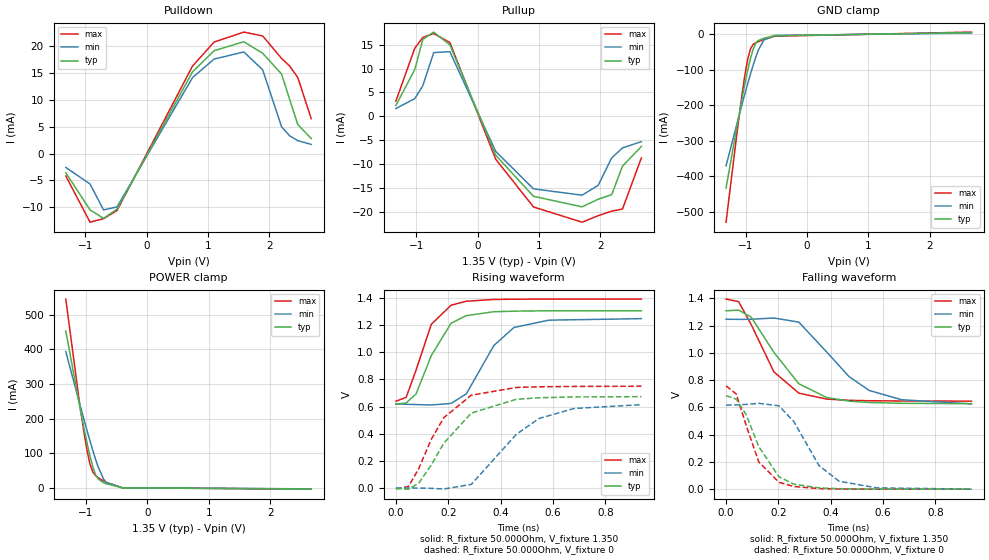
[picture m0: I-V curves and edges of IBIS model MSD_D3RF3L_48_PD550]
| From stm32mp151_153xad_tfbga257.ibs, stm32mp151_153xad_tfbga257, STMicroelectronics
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[Model] MSD_D3RF3L_48_PD550
Model_type   I/O
C_comp 2.422pF   2.338pF   2.546pF
Vinh = 810.000mV
Vinl = 540.000mV
Vmeas = 675.000mV
Vref = 675.000mV
[Model Spec]
Vinh   810.000mV   777.000mV   860.000mV
Vinl   540.000mV   507.000mV   590.000mV
Vmeas   675.000mV   642.000mV   725.000mV
Vref   675.000mV   642.000mV   725.000mV
[Temperature Range]   25.000   125.000   -40.000
[Voltage Range]   1.350V   1.283V   1.450V
[GND Clamp Reference]   0.00V   0.00V   0.00V
[Pulldown Reference]   0.00V   0.00V   0.00V
[POWER Clamp Reference]   1.350V   1.283V   1.450V
[Pullup Reference]   1.350V   1.283V   1.450V
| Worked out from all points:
|   slope of the pulldown table from 0 to 0.203 V, typ, clamps not added: 42.2 ohm
|   slope of the pullup table from 0 to 0.203 V, typ, clamps not added: 34.5 ohm
|   GND clamp passes 1 mA (typ) near -0.40 V on its own axis
|   POWER clamp passes 1 mA (typ) near -0.41 V on its own axis
|   rising waveform, R_fixture 50.000Ohm, V_fixture 1.350: 20-80 % time 94.8ps typ, 117ps min, 80.5ps max; typ from 0.617 V to 1.3 V
|   rising waveform, R_fixture 50.000Ohm, V_fixture 0: 20-80 % time 154ps typ, 186ps min, 132ps max; typ from -0.004 V to 0.672 V
|   falling waveform, R_fixture 50.000Ohm, V_fixture 1.350: 20-80 % time 154ps typ, 187ps min, 122ps max; typ from 1.31 V to 0.627 V
|   falling waveform, R_fixture 50.000Ohm, V_fixture 0: 20-80 % time 101ps typ, 119ps min, 83.8ps max; typ from 0.686 V to 0 V
[GND Clamp]
-1.318V   -433.7mA   -371mA     -529.9mA
-1.142V   -261.3mA   -253.3mA   -281.1mA
-1.055V   -178.8mA   -195.8mA   -166mA
-1.011V   -139.6mA   -167.6mA   -114.8mA
-966.7mV  -102.8mA   -140.2mA   -71.91mA
-922.7mV  -69.98mA   -113.5mA   -42.24mA
-878.8mV  -43.33mA   -88.28mA   -28.82mA
-834.9mV  -25.71mA   -64.84mA   -23.86mA
-790.9mV  -17.19mA   -44.16mA   -20.64mA
-703mV    -11.03mA   -16.2mA    -14.94mA
-527.3mV  -4.003mA   -3.392mA   -5.338mA
2.68V     4.841mA    3.764mA    6.269mA
[Power Clamp]
-1.33V    452.9mA    393.3mA    544.8mA
-1.111V   242.4mA    247.7mA    251.5mA
-1.023V   162.7mA    190.7mA    148.6mA
-978.8mV  125.6mA    162.7mA    104mA
-934.9mV  91.47mA    135.5mA    68.54mA
-890.9mV  62.09mA    109.1mA    46.9mA
-847mV    39.75mA    84.16mA    36.4mA
-803mV    26.39mA    61.34mA    30.3mA
-715.1mV  15.71mA    26.57mA    20.81mA
-671.2mV  12.48mA    16.48mA    16.64mA
-407.6mV  908uA      1.189mA    1.109mA
2.668V    -2.431mA   -2.026mA   -2.89mA
[Pulldown]
-1.318V   -3.6mA     -2.6mA     -4.2mA
-922.7mV  -10.54mA   -5.7mA     -12.83mA
-703mV    -12.11mA   -10.54mA   -12.17mA
-483.3mV  -10.4mA    -9.973mA   -10.65mA
747mV     15.26mA    14.19mA    16.34mA
1.098V    19.2mA     17.64mA    20.82mA
1.582V    20.88mA    18.97mA    22.68mA
1.889V    18.72mA    15.63mA    21.96mA
2.197V    14.84mA    5mA        17.77mA
2.329V    10.1mA     3.3mA      16.33mA
2.461V    5.4mA      2.4mA      14.2mA
2.68V     2.8mA      1.7mA      6.5mA
[Pullup]
-1.33V    2.3mA      1.652mA    3.207mA
-1.023V   9.8mA      3.715mA    14.27mA
-890.9mV  16.12mA    6.45mA     16.52mA
-715.1mV  17.64mA    13.35mA    17.34mA
-451.5mV  14.98mA    13.54mA    15.46mA
295.4mV   -8.125mA   -7.33mA    -8.964mA
910.6mV   -16.72mA   -15.16mA   -18.95mA
1.702V    -18.93mA   -16.49mA   -22.14mA
1.965V    -17.33mA   -14.42mA   -20.77mA
2.185V    -16.38mA   -8.694mA   -19.82mA
2.361V    -10.4mA    -6.59mA    -19.39mA
2.668V    -6.3mA     -5.295mA   -8.693mA
[Ramp]
R_load=50.000Ohm
dV/dt_r   405.180mV/124.500ps  372.629mV/153.000ps  448.080mV/107.000ps
dV/dt_f   405.180mV/127.000ps  372.689mV/156.000ps  448.080mV/103.000ps
[Rising waveform]
R_fixture=50.000Ohm
V_fixture=1.350
V_fixture_min=1.283
V_fixture_max=1.450
0s        617.4mV    618.8mV    638.7mV
39ps      626mV      616.7mV    667.3mV
77ps      692.4mV    614.3mV    867.1mV
135ps     973.7mV    611mV      1.204V
211ps     1.213V     622.8mV    1.345V
269ps     1.268V     693mV      1.374V
374ps     1.297V     1.048V     1.387V
451ps     1.301V     1.181V     1.389V
585ps     1.304V     1.235V     1.39V
938ps     1.304V     1.246V     1.39V
[Rising waveform]
R_fixture=50.000Ohm
V_fixture=0
0s        -4.09mV    606.6uV    -4.131mV
48ps      -7.832mV   818.7uV    11.78mV
87ps      35.91mV    486.3uV    142.2mV
135ps     169.5mV    -1.71mV    357.9mV
183ps     330.1mV    -6.609mV   518.1mV
288ps     551.7mV    27.09mV    683mV
460ps     652.9mV    395mV      739.9mV
547ps     664.6mV    512.1mV    744.9mV
681ps     670.3mV    585.5mV    747.6mV
938ps     672.3mV    613.5mV    749mV
[Falling waveform]
R_fixture=50.000Ohm
V_fixture=1.350
V_fixture_min=1.283
V_fixture_max=1.450
0s        1.308V     1.246V     1.394V
48ps      1.313V     1.245V     1.375V
96ps      1.262V     1.246V     1.207V
183ps     1.003V     1.255V     859.8mV
278ps     773.1mV    1.225V     704.4mV
384ps     672.2mV    1.007V     660.5mV
470ps     645.6mV    825.4mV    651.5mV
547ps     635.7mV    724mV      648.5mV
671ps     629.6mV    655.7mV    646.6mV
938ps     627.1mV    625.3mV    645.6mV
[Falling waveform]
R_fixture=50.000Ohm
V_fixture=0
0s        685.6mV    616.1mV    757.8mV
39ps      660.3mV    617.5mV    698.5mV
77ps      545.4mV    621.5mV    466.8mV
125ps     312.2mV    629.3mV    199.8mV
202ps     90.88mV    611.2mV    50.61mV
259ps     37.05mV    495.9mV    19.54mV
355ps     9.562mV    173.4mV    4.149mV
432ps     3.43mV     58.24mV    1.226mV
575ps     518.6uV    9.63mV     177.5uV
938ps     21.94uV    211.4uV    -6.095uV
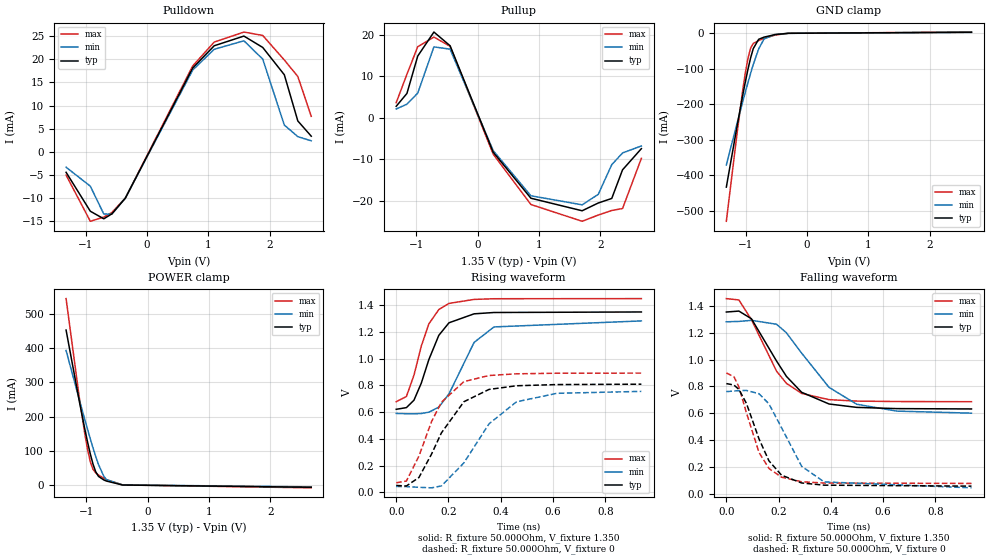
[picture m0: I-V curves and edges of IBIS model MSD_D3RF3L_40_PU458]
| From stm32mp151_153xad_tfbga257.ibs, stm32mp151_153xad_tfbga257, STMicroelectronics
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[Model] MSD_D3RF3L_40_PU458
Model_type   I/O
C_comp 2.396pF   2.311pF   2.520pF
Vinh = 810.000mV
Vinl = 540.000mV
Vmeas = 675.000mV
Vref = 675.000mV
[Model Spec]
Vinh   810.000mV   777.000mV   860.000mV
Vinl   540.000mV   507.000mV   590.000mV
Vmeas   675.000mV   642.000mV   725.000mV
Vref   675.000mV   642.000mV   725.000mV
[Temperature Range]   25.000   125.000   -40.000
[Voltage Range]   1.350V   1.283V   1.450V
[GND Clamp Reference]   0.00V   0.00V   0.00V
[Pulldown Reference]   0.00V   0.00V   0.00V
[POWER Clamp Reference]   1.350V   1.283V   1.450V
[Pullup Reference]   1.350V   1.283V   1.450V
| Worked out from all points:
|   slope of the pulldown table from 0 to 0.203 V, typ, clamps not added: 35.6 ohm
|   slope of the pullup table from 0 to 0.203 V, typ, clamps not added: 29.7 ohm
|   GND clamp passes 1 mA (typ) near -0.40 V on its own axis
|   POWER clamp passes 1 mA (typ) near -0.41 V on its own axis
|   rising waveform, R_fixture 50.000Ohm, V_fixture 1.350: 20-80 % time 85.8ps typ, 108ps min, 72.8ps max; typ from 0.621 V to 1.35 V
|   rising waveform, R_fixture 50.000Ohm, V_fixture 0: 20-80 % time 133ps typ, 159ps min, 113ps max; typ from 0.051 V to 0.809 V
|   falling waveform, R_fixture 50.000Ohm, V_fixture 1.350: 20-80 % time 146ps typ, 175ps min, 127ps max; typ from 1.35 V to 0.632 V
|   falling waveform, R_fixture 50.000Ohm, V_fixture 0: 20-80 % time 97.4ps typ, 116ps min, 84.4ps max; typ from 0.822 V to 0.057 V
[GND Clamp]
-1.318V   -433.3mA   -370.7mA   -529.5mA
-1.142V   -261mA     -253.1mA   -280.7mA
-1.055V   -178.6mA   -195.5mA   -165.6mA
-1.011V   -139.4mA   -167.5mA   -114.5mA
-966.7mV  -102.7mA   -139.9mA   -71.66mA
-922.7mV  -69.78mA   -113.4mA   -42.02mA
-878.8mV  -43.16mA   -88.12mA   -28.62mA
-790.9mV  -17.05mA   -44.03mA   -20.47mA
-703mV    -10.93mA   -16.1mA    -14.81mA
-527.3mV  -3.949mA   -3.336mA   -5.27mA
-307.6mV  -123uA     -180.2uA   -110uA
2.68V     2.885mA    2.451mA    3.413mA
[Power Clamp]
-1.33V    452.7mA    393.2mA    544.5mA
-1.111V   242.2mA    247.6mA    251.2mA
-1.023V   162.6mA    190.6mA    148.4mA
-978.8mV  125.5mA    162.7mA    103.9mA
-934.9mV  91.37mA    135.4mA    68.38mA
-890.9mV  62mA       109.1mA    46.75mA
-847mV    39.66mA    84.12mA    36.27mA
-803mV    26.32mA    61.3mA     30.18mA
-715.1mV  15.66mA    26.54mA    20.71mA
-671.2mV  12.44mA    16.45mA    16.56mA
-407.6mV  911.2uA    1.194mA    1.103mA
2.668V    -5.686mA   -4.559mA   -7.317mA
[Pulldown]
-1.318V   -4.4mA     -3.3mA     -5mA
-922.7mV  -12.81mA   -7.4mA     -14.98mA
-703mV    -14.45mA   -13.41mA   -14.07mA
-571.2mV  -13.38mA   -13.45mA   -13.08mA
-351.5mV  -9.986mA   -9.957mA   -9.956mA
747mV     18.13mA    17.69mA    18.58mA
1.098V    22.94mA    22.18mA    23.73mA
1.582V    25.03mA    24.01mA    25.9mA
1.889V    22.57mA    20.05mA    25.16mA
2.241V    16.67mA    5.8mA      19.86mA
2.461V    6.7mA      3.3mA      16.3mA
2.68V     3.4mA      2.4mA      7.7mA
[Pullup]
-1.33V    2.8mA      2.152mA    3.679mA
-1.155V   5.9mA      3.31mA     10.51mA
-978.8mV  14.9mA     5.977mA    17.15mA
-715.1mV  20.68mA    17.11mA    19.47mA
-451.5mV  17.38mA    16.56mA    17.25mA
251.5mV   -8.249mA   -7.87mA    -8.718mA
866.7mV   -19.34mA   -18.75mA   -20.85mA
1.702V    -22.36mA   -20.93mA   -24.89mA
1.965V    -20.49mA   -18.41mA   -23.39mA
2.185V    -19.39mA   -11.26mA   -22.29mA
2.361V    -12.5mA    -8.438mA   -21.82mA
2.668V    -7.4mA     -6.748mA   -9.748mA
[Ramp]
R_load=50.000Ohm
dV/dt_r   441.270mV/109.500ps  419.292mV/133.500ps  473.775mV/93.000ps
dV/dt_f   441.270mV/122.500ps  419.292mV/147.000ps  473.775mV/106.000ps
[Rising waveform]
R_fixture=50.000Ohm
V_fixture=1.350
V_fixture_min=1.283
V_fixture_max=1.450
0s        621.3mV    590.5mV    678.2mV
39ps      633.9mV    588.1mV    717.1mV
68ps      689.7mV    587.6mV    877.2mV
96ps      817.4mV    589.9mV    1.095V
125ps     993.9mV    599.8mV    1.261V
163ps     1.175V     637.5mV    1.368V
202ps     1.269V     736.9mV    1.414V
298ps     1.336V     1.122V     1.444V
374ps     1.346V     1.238V     1.449V
938ps     1.35V      1.283V     1.45V
[Rising waveform]
R_fixture=50.000Ohm
V_fixture=0
0s        51.26mV    44.18mV    71.37mV
39ps      47.26mV    42.38mV    84.36mV
87ps      110.9mV    37.55mV    271.4mV
135ps     285.3mV    33.43mV    528.5mV
173ps     445mV      47.67mV    673.9mV
259ps     678mV      220.3mV    828.6mV
355ps     770.1mV    512.4mV    874.3mV
460ps     797.5mV    677.2mV    886.9mV
614ps     806.5mV    740.9mV    891.5mV
938ps     809.3mV    755.5mV    892.2mV
[Falling waveform]
R_fixture=50.000Ohm
V_fixture=1.350
V_fixture_min=1.283
V_fixture_max=1.450
0s        1.355V     1.282V     1.455V
48ps      1.362V     1.285V     1.445V
96ps      1.305V     1.293V     1.298V
192ps     990mV      1.264V     914.6mV
230ps     874.9mV    1.2V       822.9mV
288ps     756.7mV    1.049V     748.2mV
393ps     669.3mV    793.1mV    701.6mV
499ps     644mV      667.3mV    690.9mV
652ps     634.8mV    616.2mV    687.6mV
938ps     632.3mV    600.9mV    686.3mV
[Falling waveform]
R_fixture=50.000Ohm
V_fixture=0
0s        821.6mV    761.5mV    900.6mV
29ps      810.6mV    765.9mV    873mV
48ps      778.2mV    768.7mV    797.8mV
77ps      673.3mV    770.6mV    602.9mV
125ps     409.2mV    745.7mV    307.6mV
163ps     245.6mV    670.4mV    188.6mV
211ps     138.7mV    493.1mV    123.5mV
288ps     80.46mV    205.2mV    89.7mV
374ps     64.06mV    88.4mV     80.07mV
938ps     56.82mV    44.18mV    76.96mV
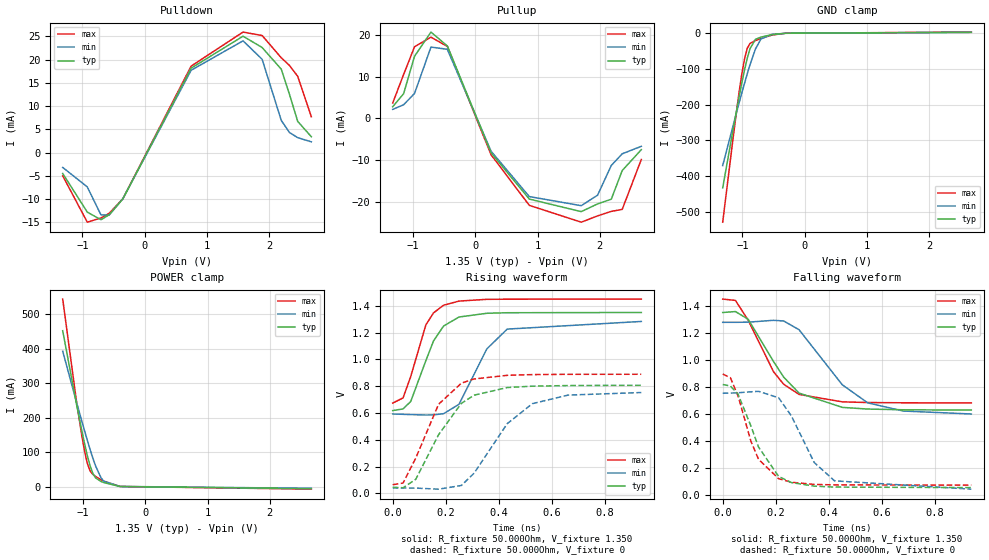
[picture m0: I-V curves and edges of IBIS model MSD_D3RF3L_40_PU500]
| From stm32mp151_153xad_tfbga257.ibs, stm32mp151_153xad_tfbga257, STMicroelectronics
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[Model] MSD_D3RF3L_40_PU500
Model_type   I/O
C_comp 2.412pF   2.328pF   2.536pF
Vinh = 810.000mV
Vinl = 540.000mV
Vmeas = 675.000mV
Vref = 675.000mV
[Model Spec]
Vinh   810.000mV   777.000mV   860.000mV
Vinl   540.000mV   507.000mV   590.000mV
Vmeas   675.000mV   642.000mV   725.000mV
Vref   675.000mV   642.000mV   725.000mV
[Temperature Range]   25.000   125.000   -40.000
[Voltage Range]   1.350V   1.283V   1.450V
[GND Clamp Reference]   0.00V   0.00V   0.00V
[Pulldown Reference]   0.00V   0.00V   0.00V
[POWER Clamp Reference]   1.350V   1.283V   1.450V
[Pullup Reference]   1.350V   1.283V   1.450V
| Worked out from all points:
|   slope of the pulldown table from 0 to 0.203 V, typ, clamps not added: 35.7 ohm
|   slope of the pullup table from 0 to 0.203 V, typ, clamps not added: 29.7 ohm
|   GND clamp passes 1 mA (typ) near -0.40 V on its own axis
|   POWER clamp passes 1 mA (typ) near -0.41 V on its own axis
|   rising waveform, R_fixture 50.000Ohm, V_fixture 1.350: 20-80 % time 86ps typ, 107ps min, 73.2ps max; typ from 0.618 V to 1.35 V
|   rising waveform, R_fixture 50.000Ohm, V_fixture 0: 20-80 % time 134ps typ, 160ps min, 114ps max; typ from 0.047 V to 0.807 V
|   falling waveform, R_fixture 50.000Ohm, V_fixture 1.350: 20-80 % time 147ps typ, 175ps min, 127ps max; typ from 1.35 V to 0.629 V
|   falling waveform, R_fixture 50.000Ohm, V_fixture 0: 20-80 % time 97.7ps typ, 115ps min, 84.8ps max; typ from 0.819 V to 0.052 V
[GND Clamp]
-1.318V   -433.4mA   -370.8mA   -529.6mA
-1.142V   -261.1mA   -253.1mA   -280.9mA
-1.055V   -178.7mA   -195.6mA   -165.8mA
-1.011V   -139.5mA   -167.5mA   -114.6mA
-966.7mV  -102.8mA   -140.1mA   -71.78mA
-922.7mV  -69.86mA   -113.4mA   -42.13mA
-878.8mV  -43.23mA   -88.18mA   -28.72mA
-790.9mV  -17.1mA    -44.08mA   -20.55mA
-703mV    -10.97mA   -16.13mA   -14.88mA
-527.3mV  -3.968mA   -3.356mA   -5.305mA
-307.6mV  -123.2uA   -182.6uA   -113.4uA
2.68V     2.644mA    2.247mA    3.128mA
[Power Clamp]
-1.33V    452.9mA    393.4mA    544.7mA
-1.111V   242.3mA    247.7mA    251.3mA
-1.023V   162.7mA    190.7mA    148.5mA
-978.8mV  125.6mA    162.8mA    103.9mA
-934.9mV  91.45mA    135.5mA    68.48mA
-890.9mV  62.07mA    109.1mA    46.85mA
-847mV    39.74mA    84.18mA    36.35mA
-803mV    26.37mA    61.36mA    30.26mA
-715.1mV  15.7mA     26.59mA    20.77mA
-671.2mV  12.49mA    16.49mA    16.61mA
-407.6mV  917.9uA    1.201mA    1.111mA
2.668V    -5.217mA   -4.179mA   -6.701mA
[Pulldown]
-1.318V   -4.5mA     -3.2mA     -5mA
-922.7mV  -12.81mA   -7.4mA     -14.98mA
-703mV    -14.45mA   -13.41mA   -14.07mA
-571.2mV  -13.39mA   -13.45mA   -13.08mA
-351.5mV  -9.986mA   -9.957mA   -9.954mA
747mV     18.14mA    17.69mA    18.58mA
1.582V    25.02mA    24.02mA    25.9mA
1.889V    22.58mA    20.05mA    25.16mA
2.197V    17.92mA    6.9mA      20.37mA
2.329V    12.5mA     4.3mA      18.73mA
2.461V    6.7mA      3.2mA      16.4mA
2.68V     3.4mA      2.3mA      7.7mA
[Pullup]
-1.33V    2.8mA      2.157mA    3.679mA
-1.155V   5.9mA      3.262mA    10.51mA
-978.8mV  14.9mA     5.977mA    17.18mA
-715.1mV  20.69mA    17.1mA     19.47mA
-451.5mV  17.37mA    16.56mA    17.25mA
251.5mV   -8.249mA   -7.87mA    -8.718mA
866.7mV   -19.35mA   -18.75mA   -20.85mA
1.702V    -22.36mA   -20.93mA   -24.89mA
1.965V    -20.5mA    -18.41mA   -23.38mA
2.185V    -19.38mA   -11.29mA   -22.3mA
2.361V    -12.5mA    -8.49mA    -21.82mA
2.668V    -7.5mA     -6.695mA   -9.848mA
[Ramp]
R_load=50.000Ohm
dV/dt_r   442.854mV/110.500ps  420.486mV/135.000ps  475.917mV/94.500ps
dV/dt_f   442.854mV/122.500ps  420.486mV/147.500ps  475.917mV/106.500ps
[Rising waveform]
R_fixture=50.000Ohm
V_fixture=1.350
V_fixture_min=1.283
V_fixture_max=1.450
0s        618.3mV    592.8mV    674.1mV
39ps      630.8mV    590.4mV    712.7mV
68ps      686.3mV    588.4mV    872.4mV
125ps     990.3mV    585.2mV    1.257V
154ps     1.138V     586.1mV    1.347V
192ps     1.249V     595.2mV    1.404V
250ps     1.316V     664.9mV    1.435V
355ps     1.344V     1.078V     1.448V
432ps     1.348V     1.226V     1.449V
938ps     1.35V      1.283V     1.45V
[Rising waveform]
R_fixture=50.000Ohm
V_fixture=0
0s        46.7mV     41.14mV    65.25mV
39ps      42.62mV    41.12mV    78.07mV
87ps      105.9mV    40.13mV    263.9mV
173ps     438.2mV    32.15mV    665.5mV
259ps     672.1mV    59.53mV    822.6mV
307ps     732.9mV    151.3mV    854.1mV
432ps     790mV      520.7mV    881.2mV
527ps     800.4mV    669.9mV    886.6mV
662ps     805mV      733.9mV    888.8mV
938ps     806.9mV    752.8mV    889.2mV
[Falling waveform]
R_fixture=50.000Ohm
V_fixture=1.350
V_fixture_min=1.283
V_fixture_max=1.450
0s        1.355V     1.282V     1.455V
48ps      1.362V     1.282V     1.445V
96ps      1.305V     1.283V     1.298V
192ps     989.7mV    1.297V     913.6mV
230ps     874.3mV    1.292V     821.3mV
288ps     755.5mV    1.227V     745.7mV
451ps     649.2mV    817.6mV    690.3mV
547ps     636.7mV    683mV      685.3mV
681ps     631.3mV    622mV      683.3mV
938ps     629.2mV    600mV      682.2mV
[Falling waveform]
R_fixture=50.000Ohm
V_fixture=0
0s        819.3mV    754.3mV    897.5mV
29ps      808.1mV    755.4mV    869.7mV
58ps      747.3mV    758mV      734.2mV
106ps     512.6mV    765mV      400.1mV
135ps     354.7mV    768.5mV    263.2mV
211ps     135.3mV    720.7mV    118.6mV
259ps     89.76mV    586mV      92.2mV
345ps     63.33mV    239.8mV    76.14mV
422ps     56.29mV    102.5mV    72.36mV
938ps     52.24mV    40.73mV    70.82mV
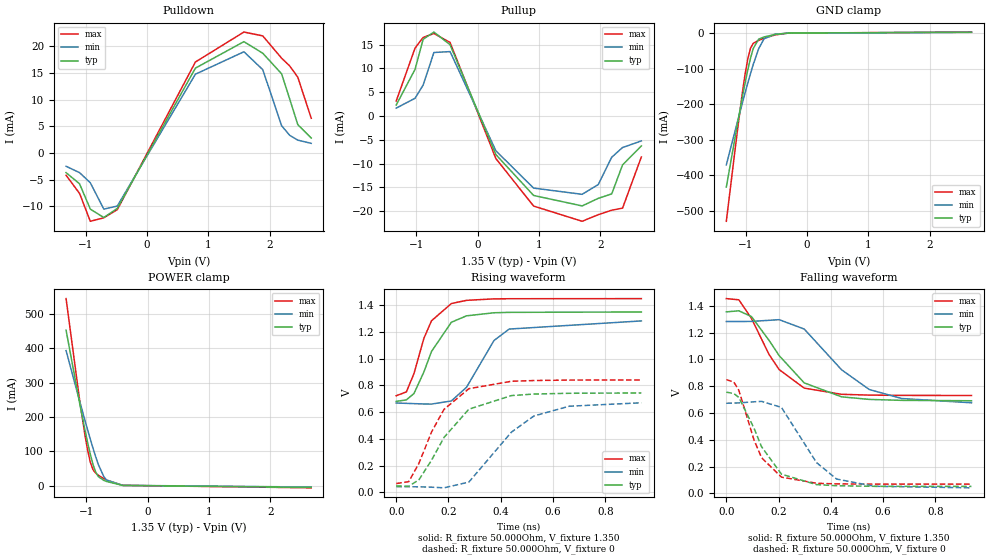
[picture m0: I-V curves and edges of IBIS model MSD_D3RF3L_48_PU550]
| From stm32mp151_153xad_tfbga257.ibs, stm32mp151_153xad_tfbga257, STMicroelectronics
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[Model] MSD_D3RF3L_48_PU550
Model_type   I/O
C_comp 2.425pF   2.340pF   2.550pF
Vinh = 810.000mV
Vinl = 540.000mV
Vmeas = 675.000mV
Vref = 675.000mV
[Model Spec]
Vinh   810.000mV   777.000mV   860.000mV
Vinl   540.000mV   507.000mV   590.000mV
Vmeas   675.000mV   642.000mV   725.000mV
Vref   675.000mV   642.000mV   725.000mV
[Temperature Range]   25.000   125.000   -40.000
[Voltage Range]   1.350V   1.283V   1.450V
[GND Clamp Reference]   0.00V   0.00V   0.00V
[Pulldown Reference]   0.00V   0.00V   0.00V
[POWER Clamp Reference]   1.350V   1.283V   1.450V
[Pullup Reference]   1.350V   1.283V   1.450V
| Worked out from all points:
|   slope of the pulldown table from 0 to 0.203 V, typ, clamps not added: 42.2 ohm
|   slope of the pullup table from 0 to 0.203 V, typ, clamps not added: 34.5 ohm
|   GND clamp passes 1 mA (typ) near -0.40 V on its own axis
|   POWER clamp passes 1 mA (typ) near -0.41 V on its own axis
|   rising waveform, R_fixture 50.000Ohm, V_fixture 1.350: 20-80 % time 92.3ps typ, 115ps min, 77ps max; typ from 0.68 V to 1.35 V
|   rising waveform, R_fixture 50.000Ohm, V_fixture 0: 20-80 % time 146ps typ, 177ps min, 123ps max; typ from 0.048 V to 0.744 V
|   falling waveform, R_fixture 50.000Ohm, V_fixture 1.350: 20-80 % time 162ps typ, 194ps min, 129ps max; typ from 1.35 V to 0.691 V
|   falling waveform, R_fixture 50.000Ohm, V_fixture 0: 20-80 % time 105ps typ, 124ps min, 86.9ps max; typ from 0.756 V to 0.052 V
[GND Clamp]
-1.318V   -433.6mA   -370.9mA   -529.9mA
-1.142V   -261.3mA   -253.2mA   -281mA
-1.055V   -178.7mA   -195.7mA   -165.9mA
-1.011V   -139.6mA   -167.6mA   -114.8mA
-966.7mV  -102.8mA   -140.1mA   -71.88mA
-922.7mV  -69.94mA   -113.6mA   -42.23mA
-878.8mV  -43.31mA   -88.24mA   -28.81mA
-790.9mV  -17.16mA   -44.13mA   -20.63mA
-703mV    -11.02mA   -16.16mA   -14.93mA
-527.3mV  -3.992mA   -3.373mA   -5.331mA
-307.6mV  -127.2uA   -185uA     -115.4uA
2.68V     2.404mA    2.042mA    2.844mA
[Power Clamp]
-1.33V    453mA      393.5mA    545mA
-1.111V   242.5mA    247.8mA    251.5mA
-1.023V   162.8mA    190.8mA    148.6mA
-978.8mV  125.6mA    162.8mA    104.1mA
-934.9mV  91.53mA    135.6mA    68.58mA
-890.9mV  62.14mA    109.2mA    46.94mA
-847mV    39.8mA     84.23mA    36.44mA
-803mV    26.44mA    61.41mA    30.34mA
-715.1mV  15.75mA    26.63mA    20.83mA
-671.2mV  12.52mA    16.53mA    16.67mA
-407.6mV  924.4uA    1.209mA    1.119mA
2.668V    -4.735mA   -3.8mA     -6.092mA
[Pulldown]
-1.318V   -3.7mA     -2.5mA     -4.2mA
-1.098V   -5.8mA     -3.7mA     -7.6mA
-922.7mV  -10.54mA   -5.6mA     -12.82mA
-703mV    -12.11mA   -10.54mA   -12.17mA
-483.3mV  -10.41mA   -9.97mA    -10.65mA
790.9mV   15.91mA    14.77mA    17.06mA
1.582V    20.88mA    18.98mA    22.68mA
1.889V    18.71mA    15.63mA    21.96mA
2.197V    14.84mA    5.1mA      17.77mA
2.329V    10.1mA     3.3mA      16.32mA
2.461V    5.3mA      2.4mA      14.2mA
2.68V     2.8mA      1.8mA      6.5mA
[Pullup]
-1.33V    2.3mA      1.652mA    3.135mA
-1.023V   9.8mA      3.715mA    14.27mA
-890.9mV  16.12mA    6.493mA    16.51mA
-715.1mV  17.65mA    13.35mA    17.35mA
-451.5mV  14.98mA    13.54mA    15.46mA
295.4mV   -8.125mA   -7.329mA   -8.964mA
910.6mV   -16.72mA   -15.17mA   -18.95mA
1.702V    -18.92mA   -16.48mA   -22.15mA
1.965V    -17.33mA   -14.43mA   -20.77mA
2.185V    -16.38mA   -8.671mA   -19.82mA
2.361V    -10.3mA    -6.643mA   -19.39mA
2.668V    -6.3mA     -5.248mA   -8.621mA
[Ramp]
R_load=50.000Ohm
dV/dt_r   405.507mV/119.000ps  372.936mV/147.000ps  447.513mV/101.000ps
dV/dt_f   405.507mV/134.000ps  372.906mV/161.500ps  447.513mV/108.500ps
[Rising waveform]
R_fixture=50.000Ohm
V_fixture=1.350
V_fixture_min=1.283
V_fixture_max=1.450
0s        680.5mV    668.5mV    722.7mV
39ps      691.9mV    665.9mV    752mV
68ps      739.6mV    663.8mV    889.2mV
106ps     901.2mV    661.3mV    1.153V
135ps     1.054V     660.5mV    1.284V
211ps     1.273V     683.9mV    1.413V
269ps     1.321V     786.2mV    1.437V
374ps     1.344V     1.136V     1.448V
432ps     1.347V     1.222V     1.449V
938ps     1.35V      1.283V     1.45V
[Rising waveform]
R_fixture=50.000Ohm
V_fixture=0
0s        47.72mV    41.93mV    65.4mV
48ps      45.51mV    41.9mV     79.74mV
87ps      93.93mV    41.15mV    216.7mV
135ps     239.7mV    38.33mV    451mV
183ps     410.9mV    33.51mV    621.2mV
278ps     622.3mV    76.57mV    775.6mV
441ps     724.1mV    450.8mV    831.2mV
527ps     735.6mV    571.5mV    836.8mV
662ps     741.3mV    644.4mV    840.2mV
938ps     743.8mV    670.1mV    841mV
[Falling waveform]
R_fixture=50.000Ohm
V_fixture=1.350
V_fixture_min=1.283
V_fixture_max=1.450
0s        1.354V     1.282V     1.453V
48ps      1.362V     1.282V     1.444V
96ps      1.319V     1.283V     1.306V
163ps     1.143V     1.291V     1.038V
202ps     1.028V     1.296V     923.6mV
298ps     824.5mV    1.226V     785.4mV
441ps     720.4mV    922mV      739.3mV
547ps     701.2mV    774.9mV    733.2mV
671ps     694.1mV    707.8mV    731.2mV
938ps     691.1mV    675.9mV    730.4mV
[Falling waveform]
R_fixture=50.000Ohm
V_fixture=0
0s        755.5mV    672.5mV    848.7mV
29ps      744.7mV    673.7mV    830.3mV
48ps      715.5mV    675.2mV    768.4mV
106ps     485.7mV    683.3mV    398.3mV
135ps     347.6mV    686.5mV    265.9mV
211ps     143.5mV    641.4mV    121.7mV
345ps     65.87mV    230mV      75.59mV
422ps     57.3mV     107.1mV    71.18mV
566ps     53.03mV    53.29mV    69.6mV
938ps     52.21mV    41.66mV    69.31mV
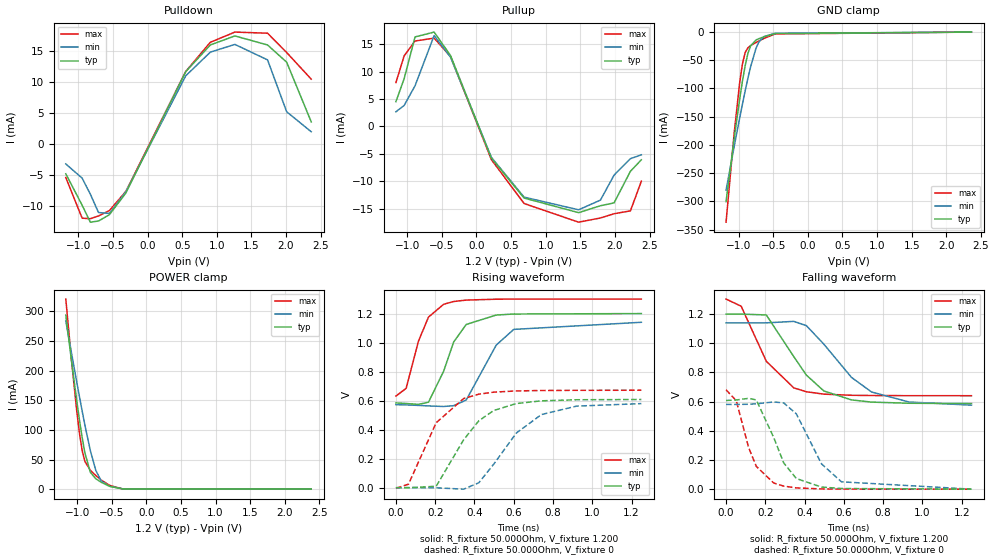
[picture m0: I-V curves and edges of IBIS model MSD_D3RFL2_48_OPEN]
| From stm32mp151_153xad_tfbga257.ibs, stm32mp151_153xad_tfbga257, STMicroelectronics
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[Model] MSD_D3RFL2_48_OPEN
Model_type   I/O
C_comp 2.581pF   2.493pF   2.708pF
Vinh = 820.000mV
Vinl = 380.000mV
Vmeas = 600.000mV
Vref = 600.000mV
[Model Spec]
Vinh   820.000mV   790.000mV   870.000mV
Vinl   380.000mV   350.000mV   430.000mV
Vmeas   600.000mV   570.000mV   650.000mV
Vref   600.000mV   570.000mV   650.000mV
[Temperature Range]   25.000   125.000   -40.000
[Voltage Range]   1.200V   1.140V   1.300V
[GND Clamp Reference]   0.00V   0.00V   0.00V
[Pulldown Reference]   0.00V   0.00V   0.00V
[POWER Clamp Reference]   1.200V   1.140V   1.300V
[Pullup Reference]   1.200V   1.140V   1.300V
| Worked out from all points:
|   slope of the pulldown table from 0 to 0.18 V, typ, clamps not added: 41.6 ohm
|   slope of the pullup table from 0 to 0.18 V, typ, clamps not added: 36.3 ohm
|   GND clamp passes 1 mA (typ) near -0.40 V on its own axis
|   POWER clamp passes 1 mA (typ) near -0.41 V on its own axis
|   rising waveform, R_fixture 50.000Ohm, V_fixture 1.200: 20-80 % time 104ps typ, 132ps min, 91ps max; typ from 0.585 V to 1.2 V
|   rising waveform, R_fixture 50.000Ohm, V_fixture 0: 20-80 % time 181ps typ, 213ps min, 157ps max; typ from 0.001 V to 0.608 V
|   falling waveform, R_fixture 50.000Ohm, V_fixture 1.200: 20-80 % time 186ps typ, 233ps min, 154ps max; typ from 1.2 V to 0.587 V
|   falling waveform, R_fixture 50.000Ohm, V_fixture 0: 20-80 % time 112ps typ, 138ps min, 97.2ps max; typ from 0.608 V to 0 V
[GND Clamp]
-1.182V   -300.5mA   -280.4mA   -337mA
-1.064V   -188.1mA   -202.5mA   -178.5mA
-984.9mV  -118.6mA   -152.2mA   -89.49mA
-945.5mV  -87.16mA   -127.9mA   -56.6mA
-906.1mV  -59.71mA   -104.4mA   -36.4mA
-866.7mV  -38.14mA   -82.14mA   -27.92mA
-827.3mV  -24.29mA   -61.54mA   -24.05mA
-748.5mV  -14mA      -28.45mA   -18.47mA
-709.1mV  -11.76mA   -17.8mA    -15.89mA
-630.3mV  -8.132mA   -7.75mA    -11.05mA
-472.7mV  -2.557mA   -2.242mA   -3.323mA
2.364V    29.58nA    484.6nA    2.864nA
[Power Clamp]
-1.164V   293.6mA    283.6mA    320.6mA
-1.085V   219.6mA    231.9mA    221.3mA
-1.006V   149.3mA    180.9mA    132.2mA
-966.7mV  116.7mA    156mA      94.33mA
-927.3mV  86.87mA    131.6mA    64.9mA
-887.9mV  61.07mA    108mA      46.71mA
-809.1mV  28.38mA    64.84mA    31.83mA
-730.3mV  17.49mA    31.58mA    22.97mA
-651.5mV  11.58mA    13.7mA     15.38mA
-533.3mV  4.956mA    4.897mA    6.46mA
-336.4mV  215.7uA    403.7uA    242.8uA
2.382V    -24.83nA   -515.5nA   -2.721nA
[Pulldown]
-1.182V   -4.8mA     -3.2mA     -5.4mA
-945.5mV  -9.88mA    -5.5mA     -11.96mA
-827.3mV  -12.61mA   -8.09mA    -12.05mA
-709.1mV  -12.42mA   -11.05mA   -11.6mA
-551.5mV  -11.39mA   -11.19mA   -10.73mA
-315.1mV  -7.913mA   -7.699mA   -7.644mA
551.5mV   11.72mA    11.04mA    11.75mA
906.1mV   16.02mA    14.86mA    16.45mA
1.261V    17.48mA    16.11mA    18.1mA
1.733V    16.02mA    13.61mA    17.92mA
2.009V    13.24mA    5.23mA     14.8mA
2.364V    3.6mA      2mA        10.5mA
[Pullup]
-1.164V   4.5mA      2.657mA    7.977mA
-1.045V   8.7mA      3.814mA    12.86mA
-887.9mV  16.31mA    7.396mA    15.56mA
-612.1mV  17.19mA    16.55mA    16.09mA
-375.8mV  12.93mA    12.63mA    12.74mA
215.2mV   -5.799mA   -5.653mA   -6.081mA
687.9mV   -13.08mA   -12.91mA   -14.07mA
1.476V    -15.74mA   -15.22mA   -17.48mA
1.791V    -14.48mA   -13.45mA   -16.71mA
1.988V    -13.96mA   -8.894mA   -15.94mA
2.224V    -8.2mA     -5.895mA   -15.41mA
2.382V    -6.1mA     -5.195mA   -10.01mA
[Ramp]
R_load=50.000Ohm
dV/dt_r   366.690mV/143.500ps  344.579mV/173.500ps  399.540mV/124.500ps
dV/dt_f   366.690mV/150.000ps  344.548mV/187.000ps  399.540mV/126.000ps
[Rising waveform]
R_fixture=50.000Ohm
V_fixture=1.200
V_fixture_min=1.140
V_fixture_max=1.300
0s        584.7mV    572.3mV    631.6mV
52ps      580.4mV    570.7mV    684.9mV
115ps     574.4mV    567.3mV    1.011V
166ps     589.6mV    563.7mV    1.176V
243ps     802.9mV    559.8mV    1.264V
294ps     1.004V     565.4mV    1.283V
358ps     1.125V     604.3mV    1.293V
511ps     1.19V      983.1mV    1.299V
600ps     1.197V     1.091V     1.3V
1.25ns    1.2V       1.14V      1.3V
[Rising waveform]
R_fixture=50.000Ohm
V_fixture=0
0s        651.9uV    197.1uV    -3.706mV
64ps      326.9uV    615.2uV    24.37mV
205ps     10.11mV    -434uV     447.9mV
345ps     330.7mV    -9.815mV   614.5mV
422ps     461.1mV    34.16mV    644.7mV
498ps     532.2mV    162.2mV    658.6mV
613ps     580.1mV    376.7mV    667mV
741ps     598.8mV    504.3mV    670mV
920ps     606.2mV    562.4mV    671.2mV
1.25ns    608mV      579.7mV    671.9mV
[Falling waveform]
R_fixture=50.000Ohm
V_fixture=1.200
V_fixture_min=1.140
V_fixture_max=1.300
0s        1.2V       1.14V      1.303V
77ps      1.2V       1.14V      1.254V
205ps     1.194V     1.14V      876.6mV
345ps     908.4mV    1.15V      694.3mV
409ps     782mV      1.121V     667.8mV
498ps     673.2mV    994mV      651.3mV
639ps     611.7mV    765.9mV    643.5mV
741ps     596.7mV    666.1mV    641.9mV
932ps     588.9mV    597.4mV    640.8mV
1.25ns    586.9mV    575.8mV    640.5mV
[Falling waveform]
R_fixture=50.000Ohm
V_fixture=0
0s        607.9mV    581.1mV    681.2mV
52ps      611.2mV    580.7mV    606.4mV
115ps     622.6mV    581.9mV    285.8mV
154ps     611.5mV    585.3mV    156.1mV
243ps     353.3mV    597.7mV    42.02mV
294ps     179.1mV    591.3mV    20.8mV
358ps     72.84mV    515.8mV    8.731mV
486ps     14.48mV    173.7mV    1.633mV
588ps     4.467mV    50.28mV    464.4uV
1.25ns    10.38uV    98.28uV    -2.272uV
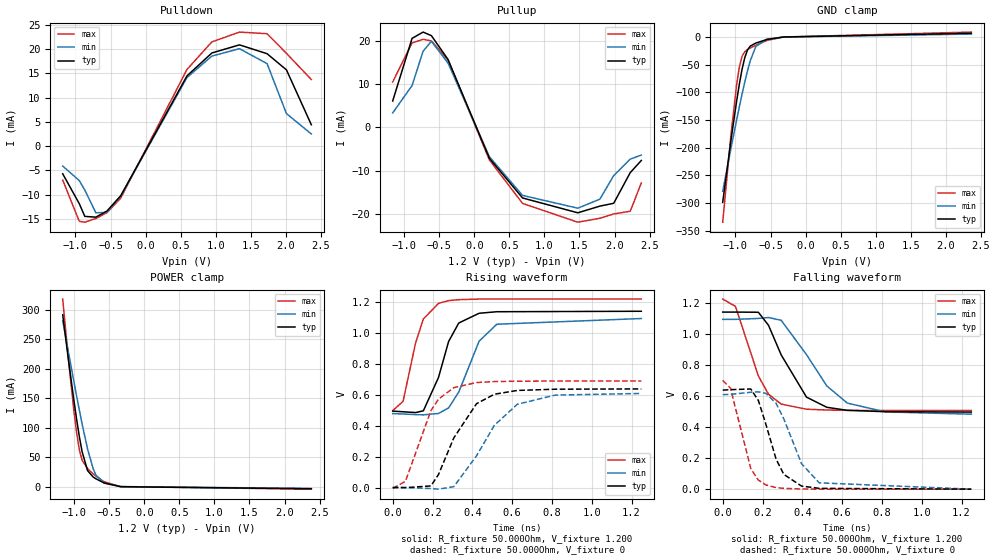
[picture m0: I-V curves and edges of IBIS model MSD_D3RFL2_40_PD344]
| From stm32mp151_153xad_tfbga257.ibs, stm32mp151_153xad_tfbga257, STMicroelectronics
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[Model] MSD_D3RFL2_40_PD344
Model_type   I/O
C_comp 2.341pF   2.257pF   2.465pF
Vinh = 820.000mV
Vinl = 380.000mV
Vmeas = 600.000mV
Vref = 600.000mV
[Model Spec]
Vinh   820.000mV   790.000mV   870.000mV
Vinl   380.000mV   350.000mV   430.000mV
Vmeas   600.000mV   570.000mV   650.000mV
Vref   600.000mV   570.000mV   650.000mV
[Temperature Range]   25.000   125.000   -40.000
[Voltage Range]   1.200V   1.140V   1.300V
[GND Clamp Reference]   0.00V   0.00V   0.00V
[Pulldown Reference]   0.00V   0.00V   0.00V
[POWER Clamp Reference]   1.200V   1.140V   1.300V
[Pullup Reference]   1.200V   1.140V   1.300V
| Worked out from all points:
|   slope of the pulldown table from 0 to 0.18 V, typ, clamps not added: 35.6 ohm
|   slope of the pullup table from 0 to 0.18 V, typ, clamps not added: 29.6 ohm
|   GND clamp passes 1 mA (typ) near -0.40 V on its own axis
|   POWER clamp passes 1 mA (typ) near -0.42 V on its own axis
|   rising waveform, R_fixture 50.000Ohm, V_fixture 1.200: 20-80 % time 93.1ps typ, 120ps min, 79.6ps max; typ from 0.495 V to 1.14 V
|   rising waveform, R_fixture 50.000Ohm, V_fixture 0: 20-80 % time 150ps typ, 184ps min, 126ps max; typ from 0.001 V to 0.639 V
|   falling waveform, R_fixture 50.000Ohm, V_fixture 1.200: 20-80 % time 150ps typ, 193ps min, 118ps max; typ from 1.14 V to 0.497 V
|   falling waveform, R_fixture 50.000Ohm, V_fixture 0: 20-80 % time 95.1ps typ, 120ps min, 79.5ps max; typ from 0.639 V to 0 V
[GND Clamp]
-1.182V   -298.7mA   -278.9mA   -334.7mA
-1.064V   -186.5mA   -201.2mA   -176.5mA
-984.9mV  -117.2mA   -151.1mA   -87.71mA
-945.5mV  -85.91mA   -126.8mA   -54.95mA
-906.1mV  -58.56mA   -103.4mA   -34.88mA
-866.7mV  -37.08mA   -81.29mA   -26.52mA
-827.3mV  -23.32mA   -60.76mA   -22.77mA
-787.9mV  -16.51mA   -42.62mA   -20mA
-709.1mV  -11.08mA   -17.24mA   -14.98mA
-551.5mV  -4.681mA   -3.974mA   -6.287mA
-315.1mV  -154.2uA   -220.1uA   -140.9uA
2.364V    6.653mA    5.111mA    8.718mA
[Power Clamp]
-1.164V   291.4mA    281.7mA    318.1mA
-1.085V   217.8mA    230mA      219mA
-1.006V   147.7mA    179.3mA    130.2mA
-966.7mV  115.2mA    154.5mA    92.47mA
-927.3mV  85.46mA    130.3mA    63.19mA
-887.9mV  59.77mA    106.8mA    45.13mA
-809.1mV  27.31mA    63.82mA    30.53mA
-730.3mV  16.63mA    30.75mA    21.92mA
-690.9mV  13.57mA    19.97mA    18.11mA
-572.7mV  6.421mA    6.328mA    8.512mA
-336.4mV  165.6uA    318.9uA    193uA
2.382V    -3.424mA   -2.825mA   -4.062mA
[Pulldown]
-1.182V   -5.7mA     -4.1mA     -7mA
-945.5mV  -11.85mA   -7.1mA     -15.47mA
-866.7mV  -14.47mA   -9.06mA    -15.66mA
-709.1mV  -14.62mA   -13.73mA   -14.89mA
-551.5mV  -13.37mA   -13.65mA   -13.72mA
-354.6mV  -10.22mA   -10.29mA   -10.7mA
590.9mV   14.46mA    14.13mA    15.79mA
945.5mV   19.17mA    18.53mA    21.45mA
1.339V    20.84mA    20.05mA    23.47mA
1.733V    19.02mA    16.98mA    23.14mA
2.009V    15.7mA     6.7mA      19.1mA
2.364V    4.4mA      2.5mA      13.7mA
[Pullup]
-1.164V   6.1mA      3.362mA    10.46mA
-887.9mV  20.51mA    9.641mA    19.46mA
-730.3mV  21.96mA    17.57mA    20.3mA
-612.1mV  21.14mA    19.84mA    19.93mA
-375.8mV  15.67mA    14.86mA    15.58mA
215.2mV   -7.105mA   -6.743mA   -7.481mA
687.9mV   -16.23mA   -15.64mA   -17.48mA
1.476V    -19.65mA   -18.59mA   -21.81mA
1.791V    -18.11mA   -16.51mA   -20.91mA
1.988V    -17.46mA   -11.09mA   -19.91mA
2.224V    -10.4mA    -7.291mA   -19.29mA
2.382V    -7.6mA     -6.348mA   -12.78mA
[Ramp]
R_load=50.000Ohm
dV/dt_r   385.260mV/122.000ps  367.109mV/152.500ps  421.380mV/102.500ps
dV/dt_f   385.260mV/124.000ps  367.109mV/158.000ps  421.380mV/98.500ps
[Rising waveform]
R_fixture=50.000Ohm
V_fixture=1.200
V_fixture_min=1.140
V_fixture_max=1.300
0s        495.4mV    479.5mV    499mV
52ps      491.2mV    476.8mV    558.6mV
115ps     486mV      472.9mV    936.8mV
154ps     497.5mV    471.3mV    1.092V
230ps     713.3mV    480.1mV    1.193V
281ps     946.8mV    516.5mV    1.211V
332ps     1.066V     619.3mV    1.217V
434ps     1.129V     948.2mV    1.221V
523ps     1.139V     1.058V     1.221V
1.249ns   1.142V     1.095V     1.221V
[Rising waveform]
R_fixture=50.000Ohm
V_fixture=0
0s        829.1uV    786.4uV    -5.39mV
64ps      -141.1uV   795.5uV    41.21mV
192ps     10.96mV    -6.115mV   498.9mV
230ps     84.84mV    -9.986mV   572.7mV
307ps     322.2mV    6.181mV    647.6mV
421ps     543.4mV    205.9mV    680.4mV
511ps     604.9mV    403.8mV    686.7mV
626ps     629.3mV    539.9mV    689.1mV
817ps     637.3mV    599.3mV    690.3mV
1.249ns   639.1mV    609.8mV    690.7mV
[Falling waveform]
R_fixture=50.000Ohm
V_fixture=1.200
V_fixture_min=1.140
V_fixture_max=1.300
0s        1.142V     1.095V     1.226V
64ps      1.142V     1.095V     1.179V
179ps     1.141V     1.101V     730.9mV
230ps     1.057V     1.107V     612.3mV
294ps     865.5mV    1.089V     548.5mV
421ps     593.5mV    867.5mV    515.6mV
523ps     528mV      665.8mV    510.4mV
626ps     508.4mV    555.1mV    508.3mV
817ps     499.6mV    498.2mV    507.5mV
1.249ns   497.2mV    483.6mV    507.4mV
[Falling waveform]
R_fixture=50.000Ohm
V_fixture=0
0s        638.7mV    609.8mV    701.6mV
39ps      641.7mV    611.4mV    651.7mV
141ps     646.1mV    625.1mV    132mV
179ps     572.2mV    627.9mV    58.55mV
217ps     418.3mV    617.5mV    27.17mV
268ps     194.3mV    554mV      10.38mV
307ps     95.26mV    453.2mV    5.141mV
396ps     19.91mV    164.1mV    1.049mV
485ps     5.237mV    40.73mV    211.9uV
1.249ns   1.416uV    18.55uV    0V
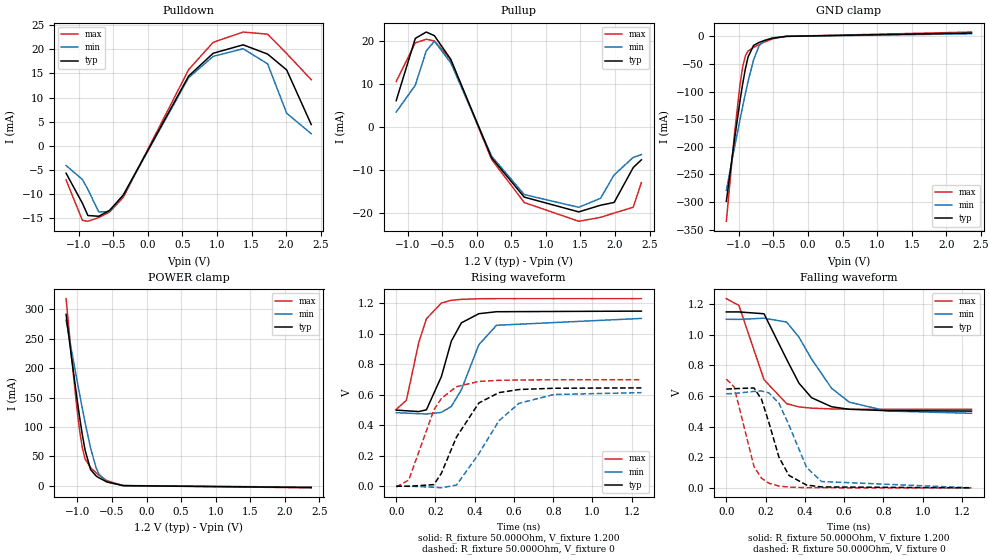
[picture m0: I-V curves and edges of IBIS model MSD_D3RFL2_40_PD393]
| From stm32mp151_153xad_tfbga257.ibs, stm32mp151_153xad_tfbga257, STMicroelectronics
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[Model] MSD_D3RFL2_40_PD393
Model_type   I/O
C_comp 2.371pF   2.287pF   2.495pF
Vinh = 820.000mV
Vinl = 380.000mV
Vmeas = 600.000mV
Vref = 600.000mV
[Model Spec]
Vinh   820.000mV   790.000mV   870.000mV
Vinl   380.000mV   350.000mV   430.000mV
Vmeas   600.000mV   570.000mV   650.000mV
Vref   600.000mV   570.000mV   650.000mV
[Temperature Range]   25.000   125.000   -40.000
[Voltage Range]   1.200V   1.140V   1.300V
[GND Clamp Reference]   0.00V   0.00V   0.00V
[Pulldown Reference]   0.00V   0.00V   0.00V
[POWER Clamp Reference]   1.200V   1.140V   1.300V
[Pullup Reference]   1.200V   1.140V   1.300V
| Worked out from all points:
|   slope of the pulldown table from 0 to 0.18 V, typ, clamps not added: 35.6 ohm
|   slope of the pullup table from 0 to 0.18 V, typ, clamps not added: 29.6 ohm
|   GND clamp passes 1 mA (typ) near -0.40 V on its own axis
|   POWER clamp passes 1 mA (typ) near -0.42 V on its own axis
|   rising waveform, R_fixture 50.000Ohm, V_fixture 1.200: 20-80 % time 93.4ps typ, 121ps min, 80.3ps max; typ from 0.5 V to 1.15 V
|   rising waveform, R_fixture 50.000Ohm, V_fixture 0: 20-80 % time 151ps typ, 185ps min, 128ps max; typ from 0.001 V to 0.645 V
|   falling waveform, R_fixture 50.000Ohm, V_fixture 1.200: 20-80 % time 153ps typ, 196ps min, 120ps max; typ from 1.15 V to 0.501 V
|   falling waveform, R_fixture 50.000Ohm, V_fixture 0: 20-80 % time 96.2ps typ, 121ps min, 80.6ps max; typ from 0.645 V to 0 V
[GND Clamp]
-1.182V   -298.9mA   -279mA     -334.9mA
-1.064V   -186.7mA   -201.4mA   -176.7mA
-984.9mV  -117.4mA   -151.2mA   -87.93mA
-945.5mV  -86.07mA   -127mA     -55.15mA
-906.1mV  -58.69mA   -103.6mA   -35.07mA
-866.7mV  -37.21mA   -81.39mA   -26.69mA
-787.9mV  -16.61mA   -42.71mA   -20.15mA
-709.1mV  -11.16mA   -17.31mA   -15.09mA
-630.3mV  -7.681mA   -7.385mA   -10.44mA
-512.1mV  -3.463mA   -2.956mA   -4.587mA
-315.1mV  -156.4uA   -222.4uA   -144.7uA
2.364V    5.825mA    4.473mA    7.624mA
[Power Clamp]
-1.164V   291.7mA    281.8mA    318.4mA
-1.085V   218mA      230.2mA    219.3mA
-1.006V   147.9mA    179.5mA    130.4mA
-966.7mV  115.4mA    154.7mA    92.71mA
-927.3mV  85.63mA    130.4mA    63.4mA
-887.9mV  59.94mA    106.9mA    45.32mA
-809.1mV  27.44mA    63.95mA    30.69mA
-730.3mV  16.73mA    30.86mA    22.05mA
-690.9mV  13.67mA    20.06mA    18.23mA
-572.7mV  6.475mA    6.385mA    8.584mA
-336.4mV  171uA      329.6uA    200.9uA
2.382V    -2.997mA   -2.472mA   -3.554mA
[Pulldown]
-1.182V   -5.7mA     -4.1mA     -7.1mA
-945.5mV  -11.93mA   -7mA       -15.48mA
-866.7mV  -14.47mA   -9.06mA    -15.66mA
-709.1mV  -14.62mA   -13.73mA   -14.89mA
-551.5mV  -13.38mA   -13.65mA   -13.72mA
-354.6mV  -10.22mA   -10.29mA   -10.7mA
590.9mV   14.46mA    14.13mA    15.79mA
945.5mV   19.18mA    18.53mA    21.45mA
1.379V    20.93mA    20.12mA    23.58mA
1.733V    19.01mA    16.98mA    23.14mA
2.009V    15.71mA    6.74mA     19.11mA
2.364V    4.4mA      2.5mA      13.7mA
[Pullup]
-1.164V   6.1mA      3.457mA    10.51mA
-887.9mV  20.5mA     9.662mA    19.47mA
-730.3mV  21.97mA    17.56mA    20.3mA
-612.1mV  21.14mA    19.85mA    19.93mA
-375.8mV  15.67mA    14.87mA    15.59mA
215.2mV   -7.105mA   -6.742mA   -7.482mA
687.9mV   -16.23mA   -15.64mA   -17.48mA
1.476V    -19.65mA   -18.59mA   -21.82mA
1.791V    -18.11mA   -16.51mA   -20.92mA
1.988V    -17.46mA   -11.09mA   -19.92mA
2.264V    -9.4mA     -7.043mA   -18.58mA
2.382V    -7.6mA     -6.395mA   -12.88mA
[Ramp]
R_load=50.000Ohm
dV/dt_r   387.990mV/123.000ps  369.149mV/153.500ps  425.250mV/104.000ps
dV/dt_f   387.990mV/125.500ps  369.149mV/160.000ps  425.250mV/100.500ps
[Rising waveform]
R_fixture=50.000Ohm
V_fixture=1.200
V_fixture_min=1.140
V_fixture_max=1.300
0s        499.5mV    482.6mV    504.1mV
52ps      495.3mV    479.8mV    564.3mV
115ps     490.1mV    475.9mV    943.8mV
154ps     501.8mV    474.3mV    1.099V
230ps     718.7mV    484.6mV    1.202V
281ps     952.5mV    523.8mV    1.22V
332ps     1.072V     633mV      1.226V
421ps     1.132V     928.5mV    1.23V
511ps     1.145V     1.056V     1.231V
1.249ns   1.149V     1.101V     1.231V
[Rising waveform]
R_fixture=50.000Ohm
V_fixture=0
0s        830uV      801uV      -5.389mV
64ps      -138.3uV   783.6uV    41.2mV
192ps     10.93mV    -6.438mV   501.1mV
230ps     84.85mV    -10.19mV   576.2mV
307ps     322.8mV    8.064mV    653.3mV
421ps     546.2mV    213.5mV    687.8mV
523ps     614.3mV    429.4mV    695.1mV
626ps     634.7mV    544.4mV    697.3mV
804ps     643mV      602.1mV    698.6mV
1.249ns   645.3mV    614.3mV    699.1mV
[Falling waveform]
R_fixture=50.000Ohm
V_fixture=1.200
V_fixture_min=1.140
V_fixture_max=1.300
0s        1.149V     1.101V     1.236V
64ps      1.149V     1.1V       1.191V
192ps     1.137V     1.108V     706.3mV
307ps     839.9mV    1.083V     549.9mV
370ps     683.7mV    984.1mV    529mV
434ps     588.8mV    841.7mV    520.5mV
536ps     529.7mV    650.7mV    515.5mV
626ps     513.1mV    559.8mV    513.7mV
817ps     504.1mV    502mV      512.7mV
1.249ns   501.4mV    486.9mV    512.5mV
[Falling waveform]
R_fixture=50.000Ohm
V_fixture=0
0s        644.8mV    614.4mV    709.9mV
39ps      647.7mV    616.1mV    660.7mV
141ps     652.3mV    629.9mV    138.6mV
179ps     579mV      632.4mV    62.85mV
217ps     425.6mV    620.1mV    29.93mV
268ps     200.5mV    553.5mV    11.82mV
319ps     81.23mV    409.9mV    4.876mV
409ps     17.92mV    132.8mV    1.032mV
485ps     5.943mV    41.34mV    300.1uV
1.249ns   1.859uV    19.56uV    536.9nV
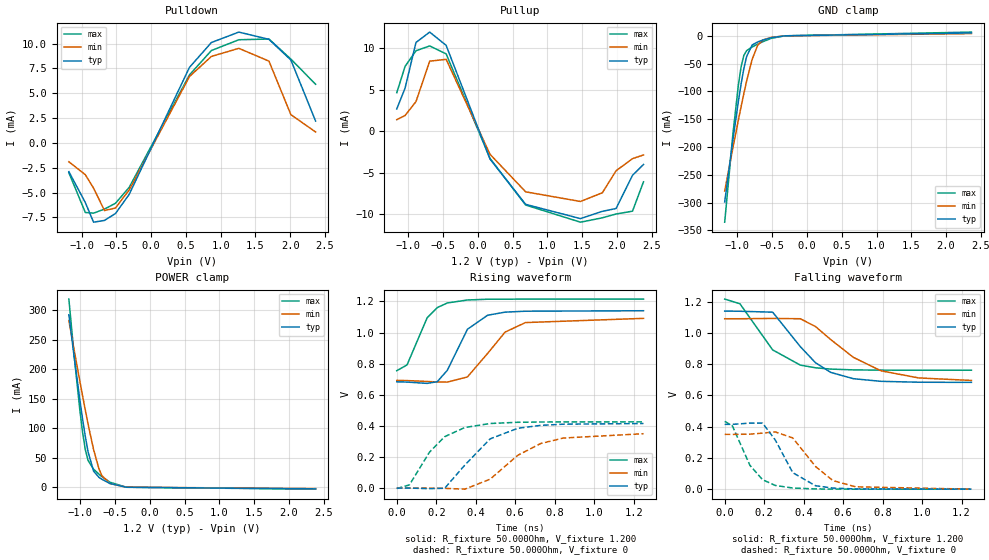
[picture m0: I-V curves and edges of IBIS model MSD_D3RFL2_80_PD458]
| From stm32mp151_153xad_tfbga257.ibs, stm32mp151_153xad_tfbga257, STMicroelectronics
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[Model] MSD_D3RFL2_80_PD458
Model_type   I/O
C_comp 2.402pF   2.316pF   2.526pF
Vinh = 820.000mV
Vinl = 380.000mV
Vmeas = 600.000mV
Vref = 600.000mV
[Model Spec]
Vinh   820.000mV   790.000mV   870.000mV
Vinl   380.000mV   350.000mV   430.000mV
Vmeas   600.000mV   570.000mV   650.000mV
Vref   600.000mV   570.000mV   650.000mV
[Temperature Range]   25.000   125.000   -40.000
[Voltage Range]   1.200V   1.140V   1.300V
[GND Clamp Reference]   0.00V   0.00V   0.00V
[Pulldown Reference]   0.00V   0.00V   0.00V
[POWER Clamp Reference]   1.200V   1.140V   1.300V
[Pullup Reference]   1.200V   1.140V   1.300V
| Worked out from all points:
|   slope of the pulldown table from 0 to 0.18 V, typ, clamps not added: 63.6 ohm
|   slope of the pullup table from 0 to 0.18 V, typ, clamps not added: 52.8 ohm
|   GND clamp passes 1 mA (typ) near -0.40 V on its own axis
|   POWER clamp passes 1 mA (typ) near -0.41 V on its own axis
|   rising waveform, R_fixture 50.000Ohm, V_fixture 1.200: 20-80 % time 115ps typ, 150ps min, 100ps max; typ from 0.684 V to 1.14 V
|   rising waveform, R_fixture 50.000Ohm, V_fixture 0: 20-80 % time 185ps typ, 231ps min, 158ps max; typ from 0 V to 0.416 V
|   falling waveform, R_fixture 50.000Ohm, V_fixture 1.200: 20-80 % time 191ps typ, 267ps min, 170ps max; typ from 1.14 V to 0.684 V
|   falling waveform, R_fixture 50.000Ohm, V_fixture 0: 20-80 % time 114ps typ, 146ps min, 105ps max; typ from 0.415 V to 0 V
[GND Clamp]
-1.182V   -299.1mA   -279.3mA   -335.3mA
-1.064V   -187mA     -201.5mA   -177mA
-984.9mV  -117.6mA   -151.3mA   -88.16mA
-945.5mV  -86.22mA   -127.1mA   -55.37mA
-906.1mV  -58.84mA   -103.8mA   -35.26mA
-866.7mV  -37.35mA   -81.5mA    -26.87mA
-787.9mV  -16.73mA   -42.8mA    -20.29mA
-709.1mV  -11.25mA   -17.38mA   -15.2mA
-630.3mV  -7.745mA   -7.438mA   -10.54mA
-512.1mV  -3.498mA   -2.984mA   -4.633mA
-315.1mV  -158.7uA   -224.9uA   -147.6uA
2.364V    4.99mA     3.837mA    6.535mA
[Power Clamp]
-1.164V   292mA      282.1mA    318.7mA
-1.085V   218.3mA    230.5mA    219.6mA
-1.006V   148.1mA    179.7mA    130.7mA
-966.7mV  115.5mA    154.8mA    92.95mA
-927.3mV  85.81mA    130.6mA    63.61mA
-887.9mV  60.1mA     107.1mA    45.52mA
-809.1mV  27.58mA    64.08mA    30.85mA
-730.3mV  16.84mA    30.96mA    22.19mA
-690.9mV  13.77mA    20.14mA    18.34mA
-572.7mV  6.533mA    6.447mA    8.649mA
-336.4mV  178.2uA    339.3uA    207.6uA
2.382V    -2.569mA   -2.119mA   -3.047mA
[Pulldown]
-1.182V   -2.9mA     -1.9mA     -3mA
-945.5mV  -6mA       -3.2mA     -7mA
-827.3mV  -7.98mA    -4.55mA    -7.07mA
-669.7mV  -7.8mA     -6.81mA    -6.66mA
-512.1mV  -7.109mA   -6.552mA   -6.075mA
-315.1mV  -5.181mA   -4.738mA   -4.478mA
551.5mV   7.601mA    6.678mA    6.842mA
866.7mV   10.1mA     8.7mA      9.294mA
1.261V    11.15mA    9.516mA    10.38mA
1.694V    10.42mA    8.227mA    10.45mA
2.009V    8.34mA     2.84mA     8.43mA
2.364V    2.2mA      1.1mA      5.9mA
[Pullup]
-1.164V   2.7mA      1.405mA    4.654mA
-1.045V   5.2mA      1.905mA    7.823mA
-887.9mV  10.71mA    3.587mA    9.714mA
-690.9mV  11.96mA    8.455mA    10.29mA
-454.5mV  10.36mA    8.678mA    9.332mA
175.8mV   -3.335mA   -2.767mA   -3.264mA
687.9mV   -8.798mA   -7.289mA   -8.88mA
1.476V    -10.52mA   -8.453mA   -10.95mA
1.791V    -9.644mA   -7.402mA   -10.42mA
1.988V    -9.3mA     -4.749mA   -9.962mA
2.224V    -5.3mA     -3.295mA   -9.621mA
2.382V    -4mA       -2.848mA   -6.085mA
[Ramp]
R_load=50.000Ohm
dV/dt_r   261.480mV/150.500ps  225.029mV/192.500ps  263.730mV/129.000ps
dV/dt_f   261.480mV/153.000ps  224.939mV/210.000ps  263.730mV/138.000ps
[Rising waveform]
R_fixture=50.000Ohm
V_fixture=1.200
V_fixture_min=1.140
V_fixture_max=1.300
0s        683.6mV    692.5mV    754.8mV
52ps      681.6mV    691.2mV    792mV
154ps     673.2mV    685.6mV    1.095V
205ps     684.1mV    682.4mV    1.16V
256ps     757.2mV    681.4mV    1.19V
358ps     1.021V     714.9mV    1.209V
460ps     1.111V     865.4mV    1.214V
549ps     1.131V     1.003V     1.214V
652ps     1.137V     1.064V     1.215V
1.25ns    1.14V      1.091V     1.215V
[Rising waveform]
R_fixture=50.000Ohm
V_fixture=0
0s        128.5uV    103.1uV    -2.528mV
64ps      570.3uV    370.5uV    21.14mV
166ps     -3.13mV    468.7uV    231.8mV
243ps     -34.7uV    -1.309mV   331.1mV
345ps     148.7mV    -6.402mV   389.9mV
473ps     316.8mV    57.8mV     415.5mV
613ps     384.7mV    211.2mV    423.3mV
728ps     403.4mV    286.4mV    425mV
843ps     411.1mV    322.1mV    425.7mV
1.25ns    415.5mV    349.9mV    426.1mV
[Falling waveform]
R_fixture=50.000Ohm
V_fixture=1.200
V_fixture_min=1.140
V_fixture_max=1.300
0s        1.14V      1.091V     1.217V
77ps      1.139V     1.091V     1.187V
243ps     1.133V     1.093V     891.6mV
383ps     912.6mV    1.091V     794.3mV
460ps     809.5mV    1.041V     777mV
537ps     747.7mV    957.9mV    768.7mV
652ps     707.2mV    843.7mV    763.6mV
792ps     690.3mV    757.6mV    762mV
983ps     684.6mV    712.1mV    761.5mV
1.25ns    683.6mV    696mV      761.5mV
[Falling waveform]
R_fixture=50.000Ohm
V_fixture=0
0s        415mV      350.9mV    434.1mV
39ps      414.8mV    350.6mV    405.3mV
128ps     423.1mV    352.2mV    152.2mV
192ps     422.7mV    358.9mV    60.4mV
256ps     315.2mV    366.6mV    23.99mV
345ps     105.4mV    328mV      7.202mV
460ps     22.1mV     145.3mV    1.536mV
549ps     6.738mV    54.34mV    403.2uV
664ps     1.385mV    15.08mV    50.26uV
1.25ns    -7.413uV   11.34uV    -1.312uV
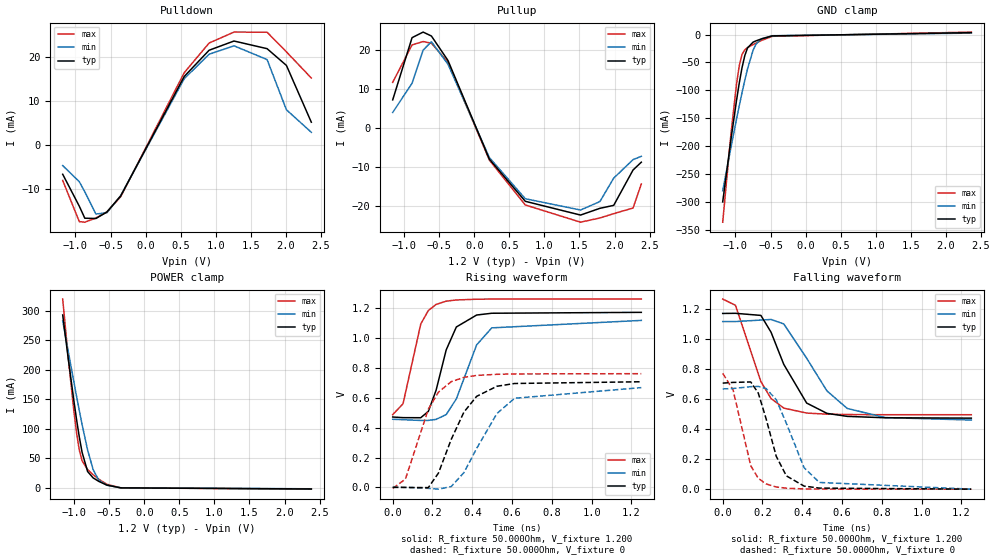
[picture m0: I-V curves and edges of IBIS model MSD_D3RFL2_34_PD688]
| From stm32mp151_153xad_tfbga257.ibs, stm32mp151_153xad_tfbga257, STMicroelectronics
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[Model] MSD_D3RFL2_34_PD688
Model_type   I/O
C_comp 2.461pF   2.375pF   2.586pF
Vinh = 820.000mV
Vinl = 380.000mV
Vmeas = 600.000mV
Vref = 600.000mV
[Model Spec]
Vinh   820.000mV   790.000mV   870.000mV
Vinl   380.000mV   350.000mV   430.000mV
Vmeas   600.000mV   570.000mV   650.000mV
Vref   600.000mV   570.000mV   650.000mV
[Temperature Range]   25.000   125.000   -40.000
[Voltage Range]   1.200V   1.140V   1.300V
[GND Clamp Reference]   0.00V   0.00V   0.00V
[Pulldown Reference]   0.00V   0.00V   0.00V
[POWER Clamp Reference]   1.200V   1.140V   1.300V
[Pullup Reference]   1.200V   1.140V   1.300V
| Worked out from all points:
|   slope of the pulldown table from 0 to 0.18 V, typ, clamps not added: 31.3 ohm
|   slope of the pullup table from 0 to 0.18 V, typ, clamps not added: 26.5 ohm
|   GND clamp passes 1 mA (typ) near -0.40 V on its own axis
|   POWER clamp passes 1 mA (typ) near -0.41 V on its own axis
|   rising waveform, R_fixture 50.000Ohm, V_fixture 1.200: 20-80 % time 91.2ps typ, 117ps min, 77.9ps max; typ from 0.472 V to 1.17 V
|   rising waveform, R_fixture 50.000Ohm, V_fixture 0: 20-80 % time 146ps typ, 177ps min, 126ps max; typ from 0.001 V to 0.708 V
|   falling waveform, R_fixture 50.000Ohm, V_fixture 1.200: 20-80 % time 147ps typ, 193ps min, 122ps max; typ from 1.17 V to 0.474 V
|   falling waveform, R_fixture 50.000Ohm, V_fixture 0: 20-80 % time 95.7ps typ, 122ps min, 82.1ps max; typ from 0.707 V to 0 V
[GND Clamp]
-1.182V   -299.6mA   -279.7mA   -335.9mA
-1.064V   -187.4mA   -201.8mA   -177.5mA
-984.9mV  -117.9mA   -151.6mA   -88.6mA
-945.5mV  -86.54mA   -127.3mA   -55.77mA
-906.1mV  -59.13mA   -104mA     -35.64mA
-866.7mV  -37.61mA   -81.71mA   -27.22mA
-827.3mV  -23.8mA    -61.15mA   -23.42mA
-748.5mV  -13.62mA   -28.14mA   -17.95mA
-709.1mV  -11.42mA   -17.52mA   -15.44mA
-630.3mV  -7.875mA   -7.542mA   -10.71mA
-472.7mV  -2.454mA   -2.156mA   -3.182mA
2.364V    3.327mA    2.556mA    4.357mA
[Power Clamp]
-1.164V   292.5mA    282.6mA    319.4mA
-1.085V   218.7mA    230.9mA    220.2mA
-1.006V   148.5mA    180.1mA    131.2mA
-966.7mV  115.9mA    155.2mA    93.42mA
-927.3mV  86.16mA    130.9mA    64.04mA
-887.9mV  60.43mA    107.4mA    45.92mA
-809.1mV  27.85mA    64.33mA    31.18mA
-730.3mV  17.06mA    31.16mA    22.45mA
-651.5mV  11.24mA    13.38mA    14.99mA
-533.3mV  4.769mA    4.703mA    6.239mA
-336.4mV  190.8uA    361uA      219.4uA
2.382V    -1.713mA   -1.413mA   -2.032mA
[Pulldown]
-1.182V   -6.7mA     -4.7mA     -8.1mA
-945.5mV  -13.99mA   -8.4mA     -17.52mA
-866.7mV  -16.74mA   -10.69mA   -17.65mA
-709.1mV  -16.81mA   -15.79mA   -16.7mA
-551.5mV  -15.32mA   -15.49mA   -15.28mA
-354.6mV  -11.64mA   -11.56mA   -11.82mA
551.5mV   15.66mA    15.15mA    16.52mA
906.1mV   21.65mA    20.73mA    23.3mA
1.261V    23.76mA    22.66mA    25.8mA
1.733V    22.01mA    19.52mA    25.77mA
2.009V    18.18mA    8.04mA     21.28mA
2.364V    5.2mA      2.9mA      15.3mA
[Pullup]
-1.164V   7.3mA      4.062mA    11.8mA
-887.9mV  23.27mA    11.57mA    21.41mA
-730.3mV  24.7mA     20.06mA    22.27mA
-612.1mV  23.69mA    22.22mA    21.84mA
-375.8mV  17.41mA    16.45mA    16.97mA
215.2mV   -7.946mA   -7.529mA   -8.168mA
727.3mV   -18.74mA   -18.08mA   -19.68mA
1.515V    -22.27mA   -20.97mA   -24.1mA
1.791V    -20.54mA   -18.81mA   -23.02mA
1.988V    -19.78mA   -12.79mA   -21.91mA
2.264V    -10.7mA    -8.043mA   -20.46mA
2.382V    -8.7mA     -7.195mA   -14.29mA
[Ramp]
R_load=50.000Ohm
dV/dt_r   422.130mV/118.500ps  398.519mV/147.500ps  458.340mV/102.000ps
dV/dt_f   422.130mV/122.000ps  398.488mV/159.000ps  458.340mV/102.500ps
[Rising waveform]
R_fixture=50.000Ohm
V_fixture=1.200
V_fixture_min=1.140
V_fixture_max=1.300
0s        471.8mV    456.7mV    487.6mV
52ps      467.5mV    453.9mV    560.5mV
141ps     467mV      448.7mV    1.095V
179ps     509.3mV    449mV      1.185V
218ps     650.5mV    455.9mV    1.226V
269ps     921.6mV    488.2mV    1.248V
320ps     1.075V     593.5mV    1.256V
422ps     1.155V     954.9mV    1.261V
498ps     1.167V     1.069V     1.262V
1.25ns    1.173V     1.119V     1.262V
[Rising waveform]
R_fixture=50.000Ohm
V_fixture=0
0s        903.8uV    888.6uV    -6.476mV
64ps      -163.2uV   768.5uV    55.97mV
179ps     -1.349mV   -6.26mV    524.2mV
230ps     96.19mV    -11.62mV   638.4mV
294ps     321.1mV    5.677mV    708.3mV
358ps     504.5mV    99.19mV    737.5mV
422ps     610.3mV    261.1mV    750.4mV
524ps     677.8mV    495.3mV    757.9mV
613ps     696.4mV    597.4mV    760.5mV
1.25ns    708mV      668.7mV    762.1mV
[Falling waveform]
R_fixture=50.000Ohm
V_fixture=1.200
V_fixture_min=1.140
V_fixture_max=1.300
0s        1.172V     1.118V     1.268V
64ps      1.173V     1.118V     1.227V
192ps     1.159V     1.128V     717.4mV
243ps     1.047V     1.132V     604.6mV
307ps     832.4mV    1.102V     540.8mV
422ps     574.4mV    873.6mV    507.5mV
524ps     505.7mV    655.5mV    500.4mV
626ps     485.5mV    538.4mV    497.7mV
817ps     476.3mV    477.6mV    496.6mV
1.25ns    473.7mV    461.1mV    496.5mV
[Falling waveform]
R_fixture=50.000Ohm
V_fixture=0
0s        707.4mV    668.6mV    772.9mV
52ps      712mV      671.4mV    662.1mV
141ps     715.2mV    683.7mV    156.3mV
179ps     640.5mV    685.4mV    72.13mV
218ps     470.3mV    671.1mV    34.88mV
269ps     219.9mV    597.2mV    14.62mV
320ps     88.87mV    439.5mV    6.411mV
409ps     20.51mV    143.4mV    1.538mV
486ps     7.138mV    44.76mV    447.7uV
1.25ns    2.789uV    26.77uV    885.4nV
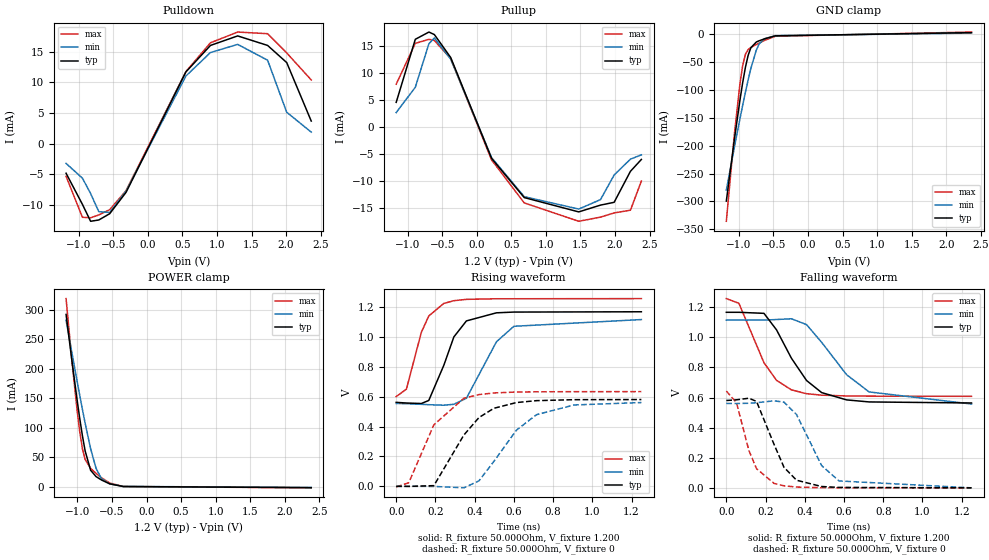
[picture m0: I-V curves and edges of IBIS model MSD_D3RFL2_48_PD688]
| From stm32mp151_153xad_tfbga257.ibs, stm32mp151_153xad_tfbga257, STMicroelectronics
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[Model] MSD_D3RFL2_48_PD688
Model_type   I/O
C_comp 2.461pF   2.375pF   2.586pF
Vinh = 820.000mV
Vinl = 380.000mV
Vmeas = 600.000mV
Vref = 600.000mV
[Model Spec]
Vinh   820.000mV   790.000mV   870.000mV
Vinl   380.000mV   350.000mV   430.000mV
Vmeas   600.000mV   570.000mV   650.000mV
Vref   600.000mV   570.000mV   650.000mV
[Temperature Range]   25.000   125.000   -40.000
[Voltage Range]   1.200V   1.140V   1.300V
[GND Clamp Reference]   0.00V   0.00V   0.00V
[Pulldown Reference]   0.00V   0.00V   0.00V
[POWER Clamp Reference]   1.200V   1.140V   1.300V
[Pullup Reference]   1.200V   1.140V   1.300V
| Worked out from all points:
|   slope of the pulldown table from 0 to 0.18 V, typ, clamps not added: 41.6 ohm
|   slope of the pullup table from 0 to 0.18 V, typ, clamps not added: 36.2 ohm
|   GND clamp passes 1 mA (typ) near -0.40 V on its own axis
|   POWER clamp passes 1 mA (typ) near -0.41 V on its own axis
|   rising waveform, R_fixture 50.000Ohm, V_fixture 1.200: 20-80 % time 103ps typ, 131ps min, 88.3ps max; typ from 0.562 V to 1.17 V
|   rising waveform, R_fixture 50.000Ohm, V_fixture 0: 20-80 % time 173ps typ, 206ps min, 147ps max; typ from 0.001 V to 0.58 V
|   falling waveform, R_fixture 50.000Ohm, V_fixture 1.200: 20-80 % time 174ps typ, 221ps min, 140ps max; typ from 1.17 V to 0.564 V
|   falling waveform, R_fixture 50.000Ohm, V_fixture 0: 20-80 % time 106ps typ, 132ps min, 90.1ps max; typ from 0.58 V to 0 V
[GND Clamp]
-1.182V   -299.6mA   -279.7mA   -335.9mA
-1.064V   -187.4mA   -201.8mA   -177.5mA
-984.9mV  -117.9mA   -151.6mA   -88.6mA
-945.5mV  -86.54mA   -127.3mA   -55.77mA
-906.1mV  -59.13mA   -104mA     -35.64mA
-866.7mV  -37.61mA   -81.71mA   -27.22mA
-827.3mV  -23.8mA    -61.15mA   -23.42mA
-748.5mV  -13.62mA   -28.14mA   -17.95mA
-709.1mV  -11.42mA   -17.52mA   -15.44mA
-630.3mV  -7.875mA   -7.542mA   -10.71mA
-472.7mV  -2.454mA   -2.156mA   -3.182mA
2.364V    3.327mA    2.556mA    4.357mA
[Power Clamp]
-1.164V   292.5mA    282.6mA    319.4mA
-1.085V   218.7mA    230.9mA    220.2mA
-1.006V   148.5mA    180.1mA    131.2mA
-966.7mV  115.9mA    155.2mA    93.42mA
-927.3mV  86.16mA    130.9mA    64.04mA
-887.9mV  60.43mA    107.4mA    45.92mA
-809.1mV  27.85mA    64.33mA    31.18mA
-730.3mV  17.06mA    31.16mA    22.45mA
-651.5mV  11.24mA    13.38mA    14.99mA
-533.3mV  4.769mA    4.703mA    6.239mA
-336.4mV  190.8uA    361uA      219.4uA
2.382V    -1.713mA   -1.413mA   -2.032mA
[Pulldown]
-1.182V   -4.8mA     -3.2mA     -5.3mA
-945.5mV  -9.87mA    -5.6mA     -11.97mA
-827.3mV  -12.62mA   -8.1mA     -12.05mA
-709.1mV  -12.41mA   -11.05mA   -11.59mA
-551.5mV  -11.39mA   -11.19mA   -10.73mA
-315.1mV  -7.914mA   -7.7mA     -7.643mA
551.5mV   11.71mA    11.04mA    11.76mA
906.1mV   16.02mA    14.86mA    16.45mA
1.3V      17.57mA    16.19mA    18.2mA
1.733V    16.02mA    13.61mA    17.93mA
2.009V    13.23mA    5.14mA     14.8mA
2.364V    3.7mA      1.9mA      10.4mA
[Pullup]
-1.164V   4.6mA      2.705mA    7.977mA
-887.9mV  16.31mA    7.401mA    15.56mA
-690.9mV  17.66mA    15.5mA     16.31mA
-612.1mV  17.19mA    16.55mA    16.09mA
-375.8mV  12.93mA    12.63mA    12.74mA
215.2mV   -5.8mA     -5.653mA   -6.08mA
687.9mV   -13.08mA   -12.91mA   -14.07mA
1.476V    -15.74mA   -15.21mA   -17.48mA
1.791V    -14.48mA   -13.46mA   -16.71mA
1.988V    -13.96mA   -8.894mA   -15.93mA
2.224V    -8.2mA     -5.943mA   -15.42mA
2.382V    -6mA       -5.148mA   -10.01mA
[Ramp]
R_load=50.000Ohm
dV/dt_r   355.260mV/138.000ps  336.539mV/169.000ps  383.970mV/118.000ps
dV/dt_f   355.260mV/141.500ps  336.478mV/178.000ps  383.970mV/115.000ps
[Rising waveform]
R_fixture=50.000Ohm
V_fixture=1.200
V_fixture_min=1.140
V_fixture_max=1.300
0s        561.8mV    554.3mV    600.2mV
52ps      557.3mV    552.8mV    650.1mV
128ps     553.9mV    548.6mV    1.029V
166ps     574.3mV    546.1mV    1.139V
243ps     810.1mV    542.6mV    1.223V
294ps     999mV      548.8mV    1.241V
358ps     1.106V     589.1mV    1.25V
511ps     1.16V      966.3mV    1.254V
600ps     1.165V     1.07V      1.254V
1.25ns    1.167V     1.115V     1.255V
[Rising waveform]
R_fixture=50.000Ohm
V_fixture=0
0s        709.2uV    211.5uV    -3.711mV
64ps      36.23uV    628.9uV    24.51mV
192ps     5.182mV    -71.8uV    411.6mV
345ps     343.4mV    -9.527mV   589mV
422ps     460.3mV    37.23mV    613.7mV
498ps     522mV      167mV      624.5mV
613ps     560.4mV    375.8mV    630.7mV
715ps     573mV      479.2mV    632.3mV
907ps     579.6mV    544.3mV    633.1mV
1.25ns    580.5mV    560.4mV    633.5mV
[Falling waveform]
R_fixture=50.000Ohm
V_fixture=1.200
V_fixture_min=1.140
V_fixture_max=1.300
0s        1.167V     1.115V     1.258V
64ps      1.167V     1.115V     1.227V
192ps     1.16V      1.115V     831.8mV
256ps     1.05V      1.119V     714.5mV
332ps     861.4mV    1.124V     651.3mV
409ps     713.5mV    1.085V     625.8mV
486ps     633.1mV    967.3mV    616mV
613ps     584.7mV    752.4mV    610.9mV
728ps     571.1mV    637.5mV    609.6mV
1.25ns    564.1mV    557.4mV    608.4mV
[Falling waveform]
R_fixture=50.000Ohm
V_fixture=0
0s        580.5mV    561mV      643.4mV
52ps      585.2mV    560.7mV    565.6mV
115ps     595.8mV    562.2mV    248.3mV
154ps     574.5mV    565.9mV    127.4mV
243ps     289.8mV    578.6mV    29.6mV
294ps     136.5mV    569.6mV    13.46mV
358ps     50.54mV    487.1mV    5.103mV
486ps     8.686mV    147.7mV    814.8uV
575ps     2.88mV     45.69mV    308uV
1.25ns    4.099uV    58.47uV    1.817uV
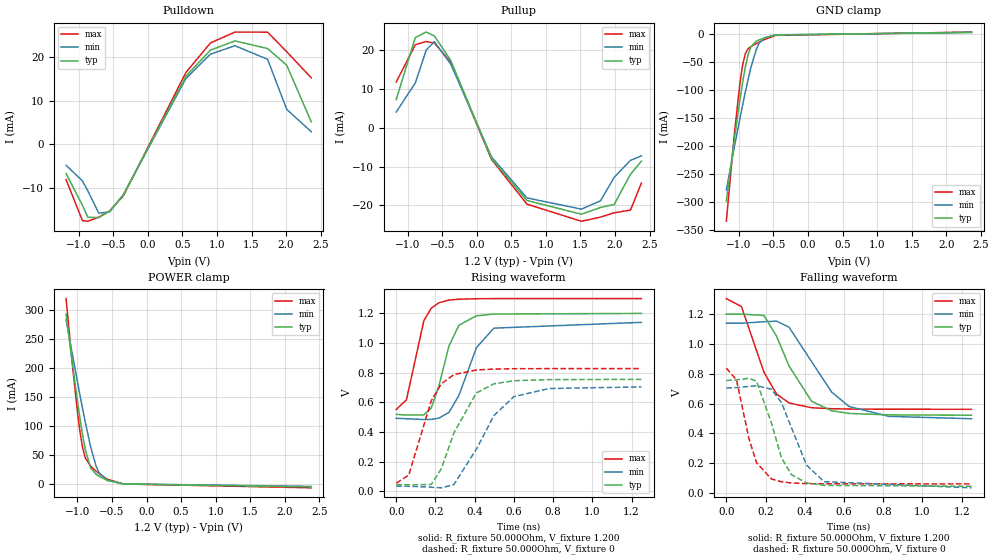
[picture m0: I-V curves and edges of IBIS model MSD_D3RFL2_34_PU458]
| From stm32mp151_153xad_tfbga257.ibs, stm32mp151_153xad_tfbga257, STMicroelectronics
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[Model] MSD_D3RFL2_34_PU458
Model_type   I/O
C_comp 2.406pF   2.319pF   2.532pF
Vinh = 820.000mV
Vinl = 380.000mV
Vmeas = 600.000mV
Vref = 600.000mV
[Model Spec]
Vinh   820.000mV   790.000mV   870.000mV
Vinl   380.000mV   350.000mV   430.000mV
Vmeas   600.000mV   570.000mV   650.000mV
Vref   600.000mV   570.000mV   650.000mV
[Temperature Range]   25.000   125.000   -40.000
[Voltage Range]   1.200V   1.140V   1.300V
[GND Clamp Reference]   0.00V   0.00V   0.00V
[Pulldown Reference]   0.00V   0.00V   0.00V
[POWER Clamp Reference]   1.200V   1.140V   1.300V
[Pullup Reference]   1.200V   1.140V   1.300V
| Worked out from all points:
|   slope of the pulldown table from 0 to 0.18 V, typ, clamps not added: 31.3 ohm
|   slope of the pullup table from 0 to 0.18 V, typ, clamps not added: 26.5 ohm
|   GND clamp passes 1 mA (typ) near -0.40 V on its own axis
|   POWER clamp passes 1 mA (typ) near -0.41 V on its own axis
|   rising waveform, R_fixture 50.000Ohm, V_fixture 1.200: 20-80 % time 87.1ps typ, 115ps min, 72.8ps max; typ from 0.52 V to 1.2 V
|   rising waveform, R_fixture 50.000Ohm, V_fixture 0: 20-80 % time 135ps typ, 167ps min, 113ps max; typ from 0.046 V to 0.756 V
|   falling waveform, R_fixture 50.000Ohm, V_fixture 1.200: 20-80 % time 151ps typ, 196ps min, 126ps max; typ from 1.2 V to 0.522 V
|   falling waveform, R_fixture 50.000Ohm, V_fixture 0: 20-80 % time 97.9ps typ, 124ps min, 83.6ps max; typ from 0.755 V to 0.046 V
[GND Clamp]
-1.182V   -299mA     -279mA     -335.2mA
-1.064V   -186.9mA   -201.3mA   -176.9mA
-984.9mV  -117.5mA   -151.2mA   -88.11mA
-945.5mV  -86.15mA   -126.9mA   -55.31mA
-906.1mV  -58.77mA   -103.6mA   -35.22mA
-866.7mV  -37.28mA   -81.4mA    -26.82mA
-827.3mV  -23.51mA   -60.86mA   -23.06mA
-748.5mV  -13.37mA   -27.9mA    -17.67mA
-709.1mV  -11.21mA   -17.31mA   -15.18mA
-630.3mV  -7.712mA   -7.374mA   -10.51mA
-472.7mV  -2.381mA   -2.076mA   -3.096mA
2.364V    2.48mA     2.095mA    2.917mA
[Power Clamp]
-1.164V   292.1mA    282.5mA    318.8mA
-1.085V   218.4mA    230.8mA    219.7mA
-1.006V   148.3mA    180mA      130.8mA
-966.7mV  115.6mA    155.1mA    93.04mA
-927.3mV  85.92mA    130.8mA    63.68mA
-887.9mV  60.21mA    107.3mA    45.58mA
-809.1mV  27.67mA    64.23mA    30.9mA
-730.3mV  16.91mA    31.08mA    22.23mA
-690.9mV  13.83mA    20.26mA    18.38mA
-572.7mV  6.582mA    6.523mA    8.677mA
-336.4mV  195.4uA    370.9uA    217.1uA
2.382V    -4.955mA   -3.949mA   -6.434mA
[Pulldown]
-1.182V   -6.7mA     -4.8mA     -8.1mA
-945.5mV  -13.98mA   -8.4mA     -17.52mA
-866.7mV  -16.74mA   -10.69mA   -17.66mA
-709.1mV  -16.81mA   -15.8mA    -16.7mA
-551.5mV  -15.32mA   -15.49mA   -15.28mA
-354.6mV  -11.63mA   -11.57mA   -11.83mA
551.5mV   15.66mA    15.15mA    16.51mA
906.1mV   21.65mA    20.73mA    23.3mA
1.261V    23.76mA    22.65mA    25.8mA
1.733V    22.01mA    19.53mA    25.77mA
2.009V    18.18mA    8.05mA     21.28mA
2.364V    5.2mA      2.9mA      15.3mA
[Pullup]
-1.164V   7.3mA      4.062mA    11.8mA
-887.9mV  23.27mA    11.57mA    21.42mA
-730.3mV  24.7mA     20.06mA    22.27mA
-612.1mV  23.69mA    22.22mA    21.84mA
-375.8mV  17.4mA     16.45mA    16.97mA
215.2mV   -7.945mA   -7.528mA   -8.168mA
727.3mV   -18.74mA   -18.08mA   -19.68mA
1.515V    -22.27mA   -20.97mA   -24.1mA
1.791V    -20.54mA   -18.82mA   -23.03mA
1.988V    -19.78mA   -12.79mA   -21.91mA
2.224V    -12mA      -8.391mA   -21.22mA
2.382V    -8.6mA     -7.243mA   -14.29mA
[Ramp]
R_load=50.000Ohm
dV/dt_r   416.361mV/111.500ps  393.825mV/140.500ps  451.272mV/93.000ps
dV/dt_f   416.361mV/124.500ps  393.795mV/161.500ps  451.272mV/105.000ps
[Rising waveform]
R_fixture=50.000Ohm
V_fixture=1.200
V_fixture_min=1.140
V_fixture_max=1.300
0s        519.8mV    493.5mV    552.7mV
52ps      515mV      490.3mV    617mV
141ps     516.1mV    485mV      1.151V
179ps     563.7mV    485.9mV    1.236V
218ps     713.1mV    494.7mV    1.272V
269ps     981.1mV    533mV      1.29V
320ps     1.121V     648.4mV    1.296V
409ps     1.184V     969.4mV    1.299V
498ps     1.196V     1.101V     1.3V
1.25ns    1.2V       1.14V      1.3V
[Rising waveform]
R_fixture=50.000Ohm
V_fixture=0
0s        46.45mV    36.11mV    56.31mV
64ps      45.08mV    35.78mV    110.6mV
179ps     46.98mV    28.77mV    612.8mV
230ps     152.8mV    24.6mV     725.5mV
294ps     394.7mV    46.41mV    787.6mV
409ps     664.5mV    285.8mV    818.9mV
498ps     725.8mV    511.3mV    825.1mV
600ps     746.7mV    639.4mV    827.5mV
779ps     754mV      694mV      828.3mV
1.25ns    755.7mV    705mV      828.4mV
[Falling waveform]
R_fixture=50.000Ohm
V_fixture=1.200
V_fixture_min=1.140
V_fixture_max=1.300
0s        1.2V       1.139V     1.304V
77ps      1.2V       1.139V     1.251V
192ps     1.191V     1.149V     809.9mV
256ps     1.052V     1.153V     664.7mV
320ps     851.5mV    1.112V     604.6mV
435ps     615.6mV    880.8mV    572.3mV
537ps     552.3mV    677.6mV    565.9mV
626ps     534.2mV    580.6mV    563.9mV
830ps     524.6mV    514.4mV    562.3mV
1.25ns    522.2mV    498.6mV    562.1mV
[Falling waveform]
R_fixture=50.000Ohm
V_fixture=0
0s        755.1mV    704.7mV    837.9mV
52ps      759.1mV    707.3mV    758.5mV
115ps     769.8mV    715.1mV    367.3mV
154ps     750mV      720.1mV    204.1mV
230ps     470.7mV    696.6mV    95.06mV
281ps     237.2mV    607.1mV    75.91mV
332ps     124.1mV    438.9mV    68.1mV
409ps     67.94mV    188.1mV    63.8mV
498ps     52.4mV     76.9mV     62.47mV
1.25ns    45.74mV    35.49mV    62.06mV
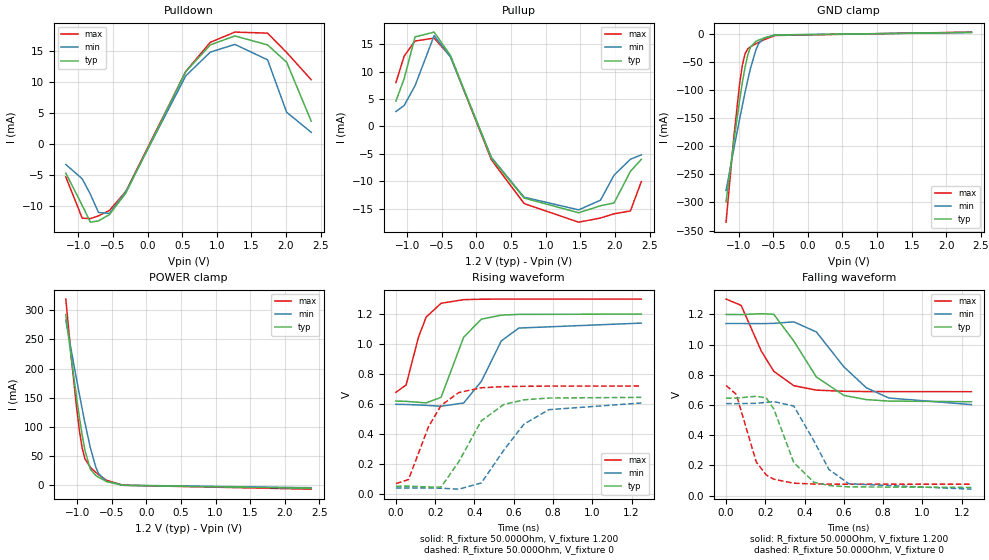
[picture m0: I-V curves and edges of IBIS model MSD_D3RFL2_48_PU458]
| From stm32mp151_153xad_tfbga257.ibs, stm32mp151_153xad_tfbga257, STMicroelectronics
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[Model] MSD_D3RFL2_48_PU458
Model_type   I/O
C_comp 2.406pF   2.319pF   2.532pF
Vinh = 820.000mV
Vinl = 380.000mV
Vmeas = 600.000mV
Vref = 600.000mV
[Model Spec]
Vinh   820.000mV   790.000mV   870.000mV
Vinl   380.000mV   350.000mV   430.000mV
Vmeas   600.000mV   570.000mV   650.000mV
Vref   600.000mV   570.000mV   650.000mV
[Temperature Range]   25.000   125.000   -40.000
[Voltage Range]   1.200V   1.140V   1.300V
[GND Clamp Reference]   0.00V   0.00V   0.00V
[Pulldown Reference]   0.00V   0.00V   0.00V
[POWER Clamp Reference]   1.200V   1.140V   1.300V
[Pullup Reference]   1.200V   1.140V   1.300V
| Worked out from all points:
|   slope of the pulldown table from 0 to 0.18 V, typ, clamps not added: 41.6 ohm
|   slope of the pullup table from 0 to 0.18 V, typ, clamps not added: 36.3 ohm
|   GND clamp passes 1 mA (typ) near -0.40 V on its own axis
|   POWER clamp passes 1 mA (typ) near -0.41 V on its own axis
|   rising waveform, R_fixture 50.000Ohm, V_fixture 1.200: 20-80 % time 97.3ps typ, 126ps min, 82.2ps max; typ from 0.621 V to 1.2 V
|   rising waveform, R_fixture 50.000Ohm, V_fixture 0: 20-80 % time 158ps typ, 192ps min, 132ps max; typ from 0.054 V to 0.646 V
|   falling waveform, R_fixture 50.000Ohm, V_fixture 1.200: 20-80 % time 177ps typ, 225ps min, 144ps max; typ from 1.2 V to 0.622 V
|   falling waveform, R_fixture 50.000Ohm, V_fixture 0: 20-80 % time 109ps typ, 135ps min, 92.1ps max; typ from 0.646 V to 0.054 V
[GND Clamp]
-1.182V   -299mA     -279mA     -335.2mA
-1.064V   -186.9mA   -201.3mA   -176.9mA
-984.9mV  -117.5mA   -151.2mA   -88.11mA
-945.5mV  -86.15mA   -126.9mA   -55.31mA
-906.1mV  -58.77mA   -103.6mA   -35.22mA
-866.7mV  -37.28mA   -81.4mA    -26.82mA
-827.3mV  -23.51mA   -60.86mA   -23.06mA
-748.5mV  -13.37mA   -27.9mA    -17.67mA
-709.1mV  -11.21mA   -17.31mA   -15.18mA
-630.3mV  -7.712mA   -7.374mA   -10.51mA
-472.7mV  -2.381mA   -2.076mA   -3.096mA
2.364V    2.48mA     2.095mA    2.917mA
[Power Clamp]
-1.164V   292.1mA    282.5mA    318.8mA
-1.085V   218.4mA    230.8mA    219.7mA
-1.006V   148.3mA    180mA      130.8mA
-966.7mV  115.6mA    155.1mA    93.04mA
-927.3mV  85.92mA    130.8mA    63.68mA
-887.9mV  60.21mA    107.3mA    45.58mA
-809.1mV  27.67mA    64.23mA    30.9mA
-730.3mV  16.91mA    31.08mA    22.23mA
-690.9mV  13.83mA    20.26mA    18.38mA
-572.7mV  6.582mA    6.523mA    8.677mA
-336.4mV  195.4uA    370.9uA    217.1uA
2.382V    -4.955mA   -3.949mA   -6.434mA
[Pulldown]
-1.182V   -4.7mA     -3.3mA     -5.3mA
-945.5mV  -9.88mA    -5.6mA     -11.97mA
-827.3mV  -12.62mA   -8.09mA    -12.05mA
-709.1mV  -12.41mA   -11.06mA   -11.6mA
-551.5mV  -11.39mA   -11.19mA   -10.72mA
-315.1mV  -7.913mA   -7.696mA   -7.646mA
551.5mV   11.71mA    11.03mA    11.75mA
906.1mV   16.03mA    14.86mA    16.45mA
1.261V    17.48mA    16.11mA    18.1mA
1.733V    16.03mA    13.62mA    17.93mA
2.009V    13.23mA    5.15mA     14.8mA
2.364V    3.7mA      1.9mA      10.4mA
[Pullup]
-1.164V   4.6mA      2.709mA    7.977mA
-1.045V   8.7mA      3.814mA    12.81mA
-887.9mV  16.31mA    7.406mA    15.56mA
-612.1mV  17.19mA    16.55mA    16.09mA
-375.8mV  12.93mA    12.63mA    12.73mA
215.2mV   -5.799mA   -5.653mA   -6.081mA
687.9mV   -13.07mA   -12.91mA   -14.07mA
1.476V    -15.75mA   -15.22mA   -17.47mA
1.791V    -14.48mA   -13.46mA   -16.71mA
1.988V    -13.96mA   -8.894mA   -15.94mA
2.224V    -8.2mA     -5.995mA   -15.42mA
2.382V    -6mA       -5.195mA   -10.06mA
[Ramp]
R_load=50.000Ohm
dV/dt_r   351.399mV/128.500ps  332.358mV/161.000ps  377.424mV/106.500ps
dV/dt_f   351.369mV/144.000ps  332.355mV/182.000ps  377.424mV/118.500ps
[Rising waveform]
R_fixture=50.000Ohm
V_fixture=1.200
V_fixture_min=1.140
V_fixture_max=1.300
0s        621.1mV    599.4mV    679mV
52ps      619mV      598.1mV    728.5mV
115ps     612.8mV    594.9mV    1.047V
154ps     608.8mV    592.2mV    1.18V
230ps     645.8mV    586.8mV    1.272V
345ps     1.046V     607.9mV    1.296V
435ps     1.166V     752.3mV    1.299V
537ps     1.193V     1.022V     1.3V
626ps     1.198V     1.107V     1.3V
1.25ns    1.2V       1.14V      1.3V
[Rising waveform]
R_fixture=50.000Ohm
V_fixture=0
0s        53.83mV    42.15mV    71.37mV
64ps      54.22mV    42.43mV    98.19mV
166ps     49.08mV    42.36mV    450.2mV
230ps     48.86mV    40.78mV    592mV
320ps     216.5mV    34.41mV    677.6mV
435ps     489.4mV    75.62mV    709.4mV
549ps     598.1mV    293.4mV    717.1mV
652ps     629.2mV    467.1mV    719.3mV
779ps     641.2mV    563.6mV    720.6mV
1.25ns    645.6mV    608.2mV    721.2mV
[Falling waveform]
R_fixture=50.000Ohm
V_fixture=1.200
V_fixture_min=1.140
V_fixture_max=1.300
0s        1.2V       1.14V      1.302V
77ps      1.199V     1.14V      1.26V
179ps     1.205V     1.139V     958.5mV
243ps     1.201V     1.141V     823.3mV
345ps     1.024V     1.151V     728.1mV
460ps     785.6mV    1.084V     698.6mV
600ps     663.7mV    853.1mV    690.8mV
715ps     635.5mV    713.6mV    689mV
830ps     626mV      646.1mV    688.5mV
1.25ns    621.5mV    602.5mV    688.2mV
[Falling waveform]
R_fixture=50.000Ohm
V_fixture=0
0s        645.6mV    609.1mV    729.3mV
52ps      645.4mV    608.8mV    670.7mV
154ps     657.8mV    611.3mV    222.1mV
205ps     646.3mV    617.2mV    136.3mV
243ps     574.4mV    622.7mV    108.1mV
345ps     218.4mV    593.2mV    81.88mV
447ps     88.37mV    363.1mV    76.37mV
524ps     66.16mV    172.6mV    75.39mV
626ps     57.3mV     77.67mV    75.07mV
1.25ns    53.68mV    42.16mV    74.93mV
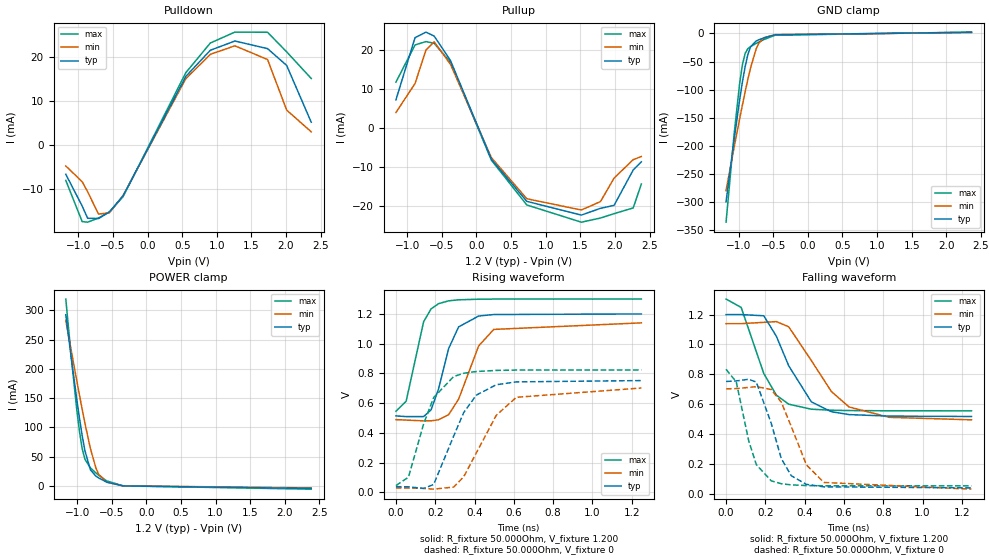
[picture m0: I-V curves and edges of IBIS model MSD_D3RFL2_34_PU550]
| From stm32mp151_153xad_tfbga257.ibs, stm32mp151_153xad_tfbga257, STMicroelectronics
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[Model] MSD_D3RFL2_34_PU550
Model_type   I/O
C_comp 2.435pF   2.348pF   2.561pF
Vinh = 820.000mV
Vinl = 380.000mV
Vmeas = 600.000mV
Vref = 600.000mV
[Model Spec]
Vinh   820.000mV   790.000mV   870.000mV
Vinl   380.000mV   350.000mV   430.000mV
Vmeas   600.000mV   570.000mV   650.000mV
Vref   600.000mV   570.000mV   650.000mV
[Temperature Range]   25.000   125.000   -40.000
[Voltage Range]   1.200V   1.140V   1.300V
[GND Clamp Reference]   0.00V   0.00V   0.00V
[Pulldown Reference]   0.00V   0.00V   0.00V
[POWER Clamp Reference]   1.200V   1.140V   1.300V
[Pullup Reference]   1.200V   1.140V   1.300V
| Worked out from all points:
|   slope of the pulldown table from 0 to 0.18 V, typ, clamps not added: 31.3 ohm
|   slope of the pullup table from 0 to 0.18 V, typ, clamps not added: 26.5 ohm
|   GND clamp passes 1 mA (typ) near -0.40 V on its own axis
|   POWER clamp passes 1 mA (typ) near -0.41 V on its own axis
|   rising waveform, R_fixture 50.000Ohm, V_fixture 1.200: 20-80 % time 88ps typ, 115ps min, 73.9ps max; typ from 0.515 V to 1.2 V
|   rising waveform, R_fixture 50.000Ohm, V_fixture 0: 20-80 % time 137ps typ, 169ps min, 116ps max; typ from 0.039 V to 0.752 V
|   falling waveform, R_fixture 50.000Ohm, V_fixture 1.200: 20-80 % time 152ps typ, 197ps min, 126ps max; typ from 1.2 V to 0.517 V
|   falling waveform, R_fixture 50.000Ohm, V_fixture 0: 20-80 % time 98.5ps typ, 125ps min, 84.3ps max; typ from 0.752 V to 0.038 V
[GND Clamp]
-1.182V   -299.3mA   -279.3mA   -335.5mA
-1.064V   -187.1mA   -201.6mA   -177.2mA
-984.9mV  -117.6mA   -151.4mA   -88.33mA
-945.5mV  -86.31mA   -127.1mA   -55.53mA
-906.1mV  -58.92mA   -103.8mA   -35.42mA
-866.7mV  -37.43mA   -81.52mA   -27.01mA
-827.3mV  -23.64mA   -60.97mA   -23.23mA
-748.5mV  -13.47mA   -27.99mA   -17.8mA
-709.1mV  -11.3mA    -17.39mA   -15.29mA
-630.3mV  -7.775mA   -7.441mA   -10.6mA
-472.7mV  -2.409mA   -2.105mA   -3.132mA
2.364V    2.067mA    1.746mA    2.431mA
[Power Clamp]
-1.164V   292.4mA    282.7mA    319.1mA
-1.085V   218.6mA    231mA      220mA
-1.006V   148.4mA    180.1mA    131mA
-966.7mV  115.9mA    155.2mA    93.22mA
-927.3mV  86.08mA    130.9mA    63.88mA
-887.9mV  60.35mA    107.4mA    45.77mA
-809.1mV  27.78mA    64.33mA    31.06mA
-730.3mV  17mA       31.16mA    22.35mA
-690.9mV  13.91mA    20.33mA    18.49mA
-572.7mV  6.632mA    6.569mA    8.741mA
-336.4mV  198.8uA    376.6uA    221.3uA
2.382V    -4.134mA   -3.29mA    -5.363mA
[Pulldown]
-1.182V   -6.7mA     -4.8mA     -8.1mA
-945.5mV  -13.96mA   -8.4mA     -17.51mA
-866.7mV  -16.74mA   -10.69mA   -17.65mA
-709.1mV  -16.81mA   -15.8mA    -16.7mA
-551.5mV  -15.32mA   -15.49mA   -15.28mA
-354.6mV  -11.64mA   -11.56mA   -11.82mA
551.5mV   15.66mA    15.14mA    16.51mA
906.1mV   21.65mA    20.72mA    23.3mA
1.261V    23.76mA    22.66mA    25.8mA
1.733V    22.02mA    19.53mA    25.76mA
2.009V    18.18mA    7.98mA     21.28mA
2.364V    5.2mA      3mA        15.2mA
[Pullup]
-1.164V   7.3mA      4.062mA    11.85mA
-887.9mV  23.27mA    11.49mA    21.41mA
-730.3mV  24.71mA    20.07mA    22.27mA
-612.1mV  23.69mA    22.22mA    21.84mA
-375.8mV  17.41mA    16.45mA    16.97mA
215.2mV   -7.946mA   -7.529mA   -8.168mA
727.3mV   -18.75mA   -18.08mA   -19.68mA
1.515V    -22.28mA   -20.97mA   -24.1mA
1.791V    -20.54mA   -18.82mA   -23.03mA
1.988V    -19.78mA   -12.79mA   -21.91mA
2.264V    -10.7mA    -8.043mA   -20.44mA
2.382V    -8.6mA     -7.248mA   -14.29mA
[Ramp]
R_load=50.000Ohm
dV/dt_r   419.097mV/113.000ps  395.922mV/142.500ps  454.962mV/95.500ps
dV/dt_f   419.097mV/125.000ps  395.889mV/162.000ps  454.962mV/105.500ps
[Rising waveform]
R_fixture=50.000Ohm
V_fixture=1.200
V_fixture_min=1.140
V_fixture_max=1.300
0s        514.6mV    489.6mV    545.5mV
52ps      509.9mV    486.5mV    613.1mV
141ps     510mV      481.1mV    1.148V
179ps     555.4mV    481.5mV    1.234V
217ps     695.9mV    488.7mV    1.269V
268ps     966.3mV    522.5mV    1.288V
319ps     1.113V     626.8mV    1.295V
421ps     1.186V     985.1mV    1.299V
498ps     1.196V     1.096V     1.3V
1.249ns   1.2V       1.14V      1.3V
[Rising waveform]
R_fixture=50.000Ohm
V_fixture=0
0s        39.05mV    30.36mV    46.13mV
64ps      37.82mV    30.11mV    103mV
141ps     27.53mV    26.96mV    460.9mV
192ps     53.31mV    22.07mV    637.9mV
294ps     379.6mV    36.29mV    779.4mV
345ps     537mV      105.6mV    801.1mV
409ps     654.2mV    265.3mV    813mV
511ps     724.2mV    519.4mV    820.3mV
613ps     743.3mV    639.7mV    822.7mV
1.249ns   752.1mV    702.1mV    823.5mV
[Falling waveform]
R_fixture=50.000Ohm
V_fixture=1.200
V_fixture_min=1.140
V_fixture_max=1.300
0s        1.2V       1.139V     1.304V
77ps      1.2V       1.139V     1.248V
192ps     1.192V     1.148V     805.1mV
256ps     1.055V     1.153V     659.8mV
319ps     856.6mV    1.118V     599.4mV
434ps     614.9mV    891.9mV    565.7mV
536ps     548.8mV    684.4mV    558.9mV
626ps     529.6mV    580.7mV    556.7mV
830ps     519.4mV    511.3mV    555.1mV
1.249ns   516.9mV    494.5mV    554.9mV
[Falling waveform]
R_fixture=50.000Ohm
V_fixture=0
0s        751.5mV    701.8mV    833.2mV
52ps      755.4mV    704.2mV    748.8mV
115ps     766.3mV    711.8mV    355.3mV
154ps     747.7mV    716.9mV    194.5mV
230ps     470.9mV    697.7mV    85.5mV
281ps     235.4mV    613.3mV    66.32mV
332ps     119.5mV    449.4mV    58.39mV
409ps     61.79mV    192.3mV    53.93mV
498ps     45.43mV    74.51mV    52.51mV
1.249ns   38.32mV    29.71mV    52.06mV
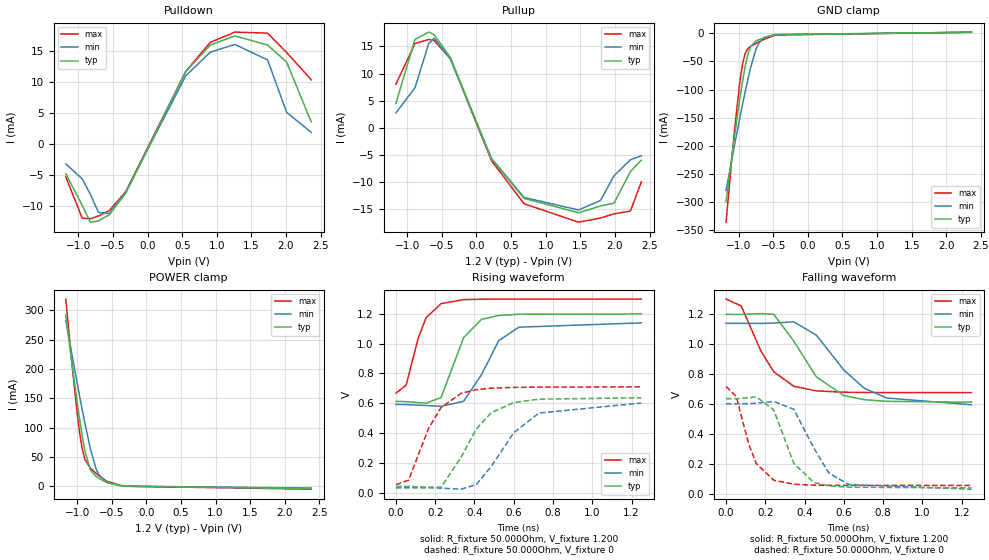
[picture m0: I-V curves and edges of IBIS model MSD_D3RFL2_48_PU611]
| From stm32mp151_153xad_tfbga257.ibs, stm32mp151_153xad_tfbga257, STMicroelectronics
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[Model] MSD_D3RFL2_48_PU611
Model_type   I/O
C_comp 2.451pF   2.364pF   2.578pF
Vinh = 820.000mV
Vinl = 380.000mV
Vmeas = 600.000mV
Vref = 600.000mV
[Model Spec]
Vinh   820.000mV   790.000mV   870.000mV
Vinl   380.000mV   350.000mV   430.000mV
Vmeas   600.000mV   570.000mV   650.000mV
Vref   600.000mV   570.000mV   650.000mV
[Temperature Range]   25.000   125.000   -40.000
[Voltage Range]   1.200V   1.140V   1.300V
[GND Clamp Reference]   0.00V   0.00V   0.00V
[Pulldown Reference]   0.00V   0.00V   0.00V
[POWER Clamp Reference]   1.200V   1.140V   1.300V
[Pullup Reference]   1.200V   1.140V   1.300V
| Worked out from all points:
|   slope of the pulldown table from 0 to 0.18 V, typ, clamps not added: 41.6 ohm
|   slope of the pullup table from 0 to 0.18 V, typ, clamps not added: 36.3 ohm
|   GND clamp passes 1 mA (typ) near -0.40 V on its own axis
|   POWER clamp passes 1 mA (typ) near -0.41 V on its own axis
|   rising waveform, R_fixture 50.000Ohm, V_fixture 1.200: 20-80 % time 99.1ps typ, 128ps min, 84.3ps max; typ from 0.613 V to 1.2 V
|   rising waveform, R_fixture 50.000Ohm, V_fixture 0: 20-80 % time 163ps typ, 198ps min, 138ps max; typ from 0.041 V to 0.637 V
|   falling waveform, R_fixture 50.000Ohm, V_fixture 1.200: 20-80 % time 180ps typ, 227ps min, 147ps max; typ from 1.2 V to 0.613 V
|   falling waveform, R_fixture 50.000Ohm, V_fixture 0: 20-80 % time 110ps typ, 136ps min, 93.3ps max; typ from 0.637 V to 0.041 V
[GND Clamp]
-1.182V   -299.4mA   -279.4mA   -335.7mA
-1.064V   -187.2mA   -201.7mA   -177.3mA
-984.9mV  -117.7mA   -151.5mA   -88.45mA
-945.5mV  -86.41mA   -127.2mA   -55.64mA
-906.1mV  -59.01mA   -103.9mA   -35.52mA
-866.7mV  -37.5mA    -81.58mA   -27.1mA
-827.3mV  -23.7mA    -61.03mA   -23.31mA
-748.5mV  -13.53mA   -28.05mA   -17.87mA
-709.1mV  -11.34mA   -17.43mA   -15.36mA
-630.3mV  -7.814mA   -7.472mA   -10.65mA
-472.7mV  -2.424mA   -2.118mA   -3.155mA
2.364V    1.86mA     1.572mA    2.188mA
[Power Clamp]
-1.164V   292.5mA    282.8mA    319.3mA
-1.085V   218.7mA    231.1mA    220.1mA
-1.006V   148.5mA    180.2mA    131.1mA
-966.7mV  116mA      155.3mA    93.34mA
-927.3mV  86.16mA    131mA      63.99mA
-887.9mV  60.42mA    107.5mA    45.87mA
-809.1mV  27.84mA    64.38mA    31.14mA
-730.3mV  17.05mA    31.2mA     22.42mA
-690.9mV  13.96mA    20.37mA    18.55mA
-572.7mV  6.658mA    6.592mA    8.774mA
-336.4mV  200.5uA    379.1uA    223.4uA
2.382V    -3.72mA    -2.96mA    -4.821mA
[Pulldown]
-1.182V   -4.8mA     -3.2mA     -5.3mA
-945.5mV  -9.87mA    -5.6mA     -11.96mA
-827.3mV  -12.61mA   -8.1mA     -12.05mA
-709.1mV  -12.41mA   -11.05mA   -11.6mA
-551.5mV  -11.39mA   -11.19mA   -10.72mA
-315.1mV  -7.909mA   -7.7mA     -7.642mA
551.5mV   11.72mA    11.04mA    11.75mA
906.1mV   16.02mA    14.86mA    16.45mA
1.261V    17.48mA    16.11mA    18.1mA
1.733V    16.02mA    13.61mA    17.93mA
2.009V    13.24mA    5.14mA     14.8mA
2.364V    3.6mA      1.9mA      10.4mA
[Pullup]
-1.164V   4.5mA      2.709mA    8.031mA
-887.9mV  16.31mA    7.401mA    15.56mA
-690.9mV  17.66mA    15.5mA     16.3mA
-612.1mV  17.19mA    16.54mA    16.09mA
-375.8mV  12.93mA    12.63mA    12.74mA
215.2mV   -5.799mA   -5.653mA   -6.081mA
687.9mV   -13.08mA   -12.91mA   -14.07mA
1.476V    -15.74mA   -15.22mA   -17.48mA
1.791V    -14.48mA   -13.46mA   -16.71mA
1.988V    -13.96mA   -8.894mA   -15.94mA
2.224V    -8.1mA     -5.943mA   -15.42mA
2.382V    -6mA       -5.2mA     -10.01mA
[Ramp]
R_load=50.000Ohm
dV/dt_r   355.191mV/132.000ps  335.379mV/163.500ps  382.863mV/111.000ps
dV/dt_f   355.161mV/145.500ps  335.379mV/183.500ps  382.863mV/120.000ps
[Rising waveform]
R_fixture=50.000Ohm
V_fixture=1.200
V_fixture_min=1.140
V_fixture_max=1.300
0s        612.7mV    592.6mV    667.7mV
52ps      610.6mV    591mV      721.7mV
115ps     604.4mV    587.4mV    1.044V
154ps     600.6mV    584.6mV    1.175V
230ps     638.6mV    579.9mV    1.269V
345ps     1.041V     613mV      1.296V
435ps     1.163V     790.2mV    1.299V
524ps     1.19V      1.021V     1.3V
626ps     1.198V     1.111V     1.3V
1.25ns    1.2V       1.14V      1.3V
[Rising waveform]
R_fixture=50.000Ohm
V_fixture=0
0s        40.8mV     31.94mV    53.1mV
64ps      41.23mV    32.26mV    82.87mV
166ps     36.02mV    32.02mV    430.4mV
230ps     35.95mV    29.78mV    571.7mV
332ps     237.1mV    22.78mV    666.6mV
409ps     426.7mV    53.55mV    691.3mV
486ps     537mV      176.4mV    701.3mV
600ps     604.6mV    401.9mV    706.5mV
728ps     627.5mV    534.1mV    708.5mV
1.25ns    636.7mV    601.5mV    709.8mV
[Falling waveform]
R_fixture=50.000Ohm
V_fixture=1.200
V_fixture_min=1.140
V_fixture_max=1.300
0s        1.2V       1.14V      1.302V
77ps      1.199V     1.14V      1.256V
179ps     1.205V     1.139V     951.3mV
243ps     1.2V       1.142V     816.2mV
345ps     1.021V     1.15V      719.4mV
460ps     781.8mV    1.061V     688.4mV
600ps     657.4mV    827.9mV    679.7mV
703ps     630mV      706.8mV    677.9mV
817ps     618.7mV    641mV      677.2mV
1.25ns    613mV      595.6mV    676.8mV
[Falling waveform]
R_fixture=50.000Ohm
V_fixture=0
0s        636.8mV    602.4mV    718.4mV
52ps      636.6mV    602mV      651.2mV
115ps     642.2mV    603.1mV    334.9mV
154ps     649.3mV    606.2mV    203.1mV
243ps     561.9mV    618mV      91.7mV
345ps     204.1mV    565.6mV    64.57mV
447ps     76.82mV    306.7mV    58.58mV
524ps     53.9mV     139.5mV    57.5mV
626ps     44.57mV    62.48mV    57.09mV
1.25ns    40.64mV    31.87mV    56.89mV
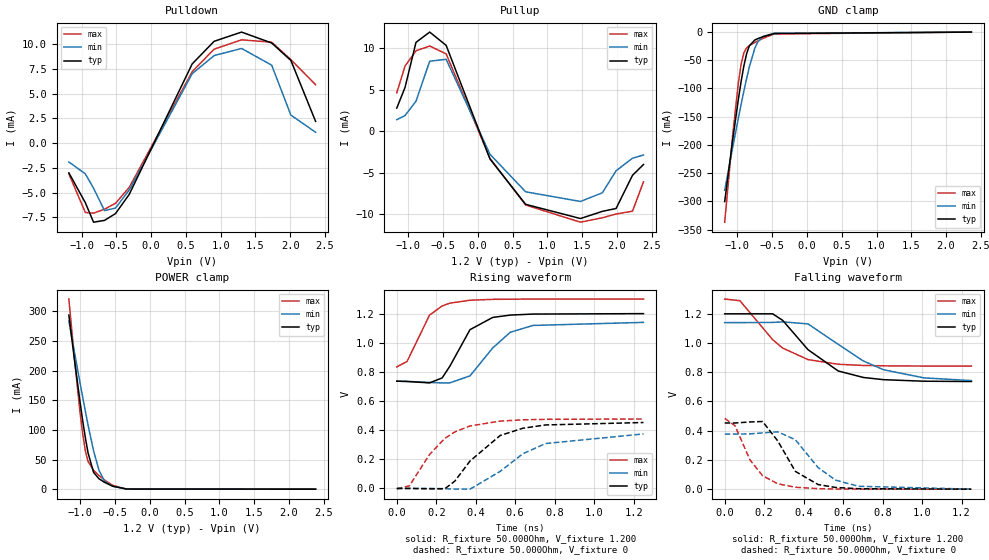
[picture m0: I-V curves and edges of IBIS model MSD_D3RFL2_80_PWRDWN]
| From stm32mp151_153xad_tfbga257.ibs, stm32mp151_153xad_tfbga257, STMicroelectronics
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[Model] MSD_D3RFL2_80_PWRDWN
Model_type   I/O
C_comp 2.581pF   2.493pF   2.708pF
Vinh = 820.000mV
Vinl = 380.000mV
Vmeas = 600.000mV
Vref = 600.000mV
[Model Spec]
Vinh   820.000mV   790.000mV   870.000mV
Vinl   380.000mV   350.000mV   430.000mV
Vmeas   600.000mV   570.000mV   650.000mV
Vref   600.000mV   570.000mV   650.000mV
[Temperature Range]   25.000   125.000   -40.000
[Voltage Range]   1.200V   1.140V   1.300V
[GND Clamp Reference]   0.00V   0.00V   0.00V
[Pulldown Reference]   0.00V   0.00V   0.00V
[POWER Clamp Reference]   1.200V   1.140V   1.300V
[Pullup Reference]   1.200V   1.140V   1.300V
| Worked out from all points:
|   slope of the pulldown table from 0 to 0.18 V, typ, clamps not added: 63.6 ohm
|   slope of the pullup table from 0 to 0.18 V, typ, clamps not added: 52.8 ohm
|   GND clamp passes 1 mA (typ) near -0.40 V on its own axis
|   POWER clamp passes 1 mA (typ) near -0.41 V on its own axis
|   rising waveform, R_fixture 50.000Ohm, V_fixture 1.200: 20-80 % time 120ps typ, 155ps min, 106ps max; typ from 0.736 V to 1.2 V
|   rising waveform, R_fixture 50.000Ohm, V_fixture 0: 20-80 % time 204ps typ, 247ps min, 181ps max; typ from 0 V to 0.453 V
|   falling waveform, R_fixture 50.000Ohm, V_fixture 1.200: 20-80 % time 217ps typ, 287ps min, 202ps max; typ from 1.2 V to 0.737 V
|   falling waveform, R_fixture 50.000Ohm, V_fixture 0: 20-80 % time 125ps typ, 159ps min, 120ps max; typ from 0.453 V to 0 V
[GND Clamp]
-1.182V   -300.5mA   -280.4mA   -337mA
-1.064V   -188.1mA   -202.5mA   -178.5mA
-984.9mV  -118.6mA   -152.2mA   -89.49mA
-945.5mV  -87.16mA   -127.9mA   -56.6mA
-906.1mV  -59.71mA   -104.4mA   -36.4mA
-866.7mV  -38.14mA   -82.14mA   -27.92mA
-827.3mV  -24.29mA   -61.54mA   -24.05mA
-748.5mV  -14mA      -28.45mA   -18.47mA
-709.1mV  -11.76mA   -17.8mA    -15.89mA
-630.3mV  -8.132mA   -7.75mA    -11.05mA
-472.7mV  -2.557mA   -2.242mA   -3.323mA
2.364V    29.58nA    484.6nA    2.864nA
[Power Clamp]
-1.164V   293.6mA    283.6mA    320.6mA
-1.085V   219.6mA    231.9mA    221.3mA
-1.006V   149.3mA    180.9mA    132.2mA
-966.7mV  116.7mA    156mA      94.33mA
-927.3mV  86.87mA    131.6mA    64.9mA
-887.9mV  61.07mA    108mA      46.71mA
-809.1mV  28.38mA    64.84mA    31.83mA
-730.3mV  17.49mA    31.58mA    22.97mA
-651.5mV  11.58mA    13.7mA     15.38mA
-533.3mV  4.956mA    4.897mA    6.46mA
-336.4mV  215.7uA    403.7uA    242.8uA
2.382V    -24.83nA   -515.5nA   -2.721nA
[Pulldown]
-1.182V   -3mA       -1.9mA     -3.1mA
-945.5mV  -6.01mA    -3.1mA     -7mA
-827.3mV  -7.98mA    -4.55mA    -7.07mA
-669.7mV  -7.799mA   -6.81mA    -6.67mA
-512.1mV  -7.115mA   -6.556mA   -6.075mA
-315.1mV  -5.181mA   -4.738mA   -4.478mA
590.9mV   8.002mA    7.016mA    7.22mA
906.1mV   10.28mA    8.84mA     9.488mA
1.3V      11.21mA    9.56mA     10.43mA
1.733V    10.11mA    7.871mA    10.19mA
2.009V    8.35mA     2.83mA     8.43mA
2.364V    2.2mA      1.1mA      5.9mA
[Pullup]
-1.164V   2.8mA      1.405mA    4.654mA
-1.045V   5.3mA      1.905mA    7.869mA
-887.9mV  10.72mA    3.629mA    9.704mA
-690.9mV  11.96mA    8.455mA    10.28mA
-454.5mV  10.36mA    8.679mA    9.333mA
175.8mV   -3.334mA   -2.766mA   -3.264mA
687.9mV   -8.798mA   -7.289mA   -8.88mA
1.476V    -10.51mA   -8.453mA   -10.95mA
1.791V    -9.644mA   -7.404mA   -10.42mA
1.988V    -9.3mA     -4.749mA   -9.962mA
2.224V    -5.3mA     -3.248mA   -9.621mA
2.382V    -4mA       -2.848mA   -6.085mA
[Ramp]
R_load=50.000Ohm
dV/dt_r   275.100mV/163.000ps  234.149mV/204.500ps  280.380mV/144.000ps
dV/dt_f   275.100mV/172.000ps  234.120mV/227.500ps  280.380mV/161.000ps
[Rising waveform]
R_fixture=50.000Ohm
V_fixture=1.200
V_fixture_min=1.140
V_fixture_max=1.300
0s        736.4mV    736.7mV    834.5mV
52ps      734.3mV    735.2mV    871.7mV
166ps     724.7mV    728mV      1.19V
230ps     758.9mV    724.2mV    1.253V
269ps     839.5mV    725mV      1.272V
371ps     1.09V      773mV      1.292V
486ps     1.174V     964.3mV    1.298V
575ps     1.19V      1.072V     1.299V
690ps     1.197V     1.119V     1.3V
1.25ns    1.2V       1.14V      1.3V
[Rising waveform]
R_fixture=50.000Ohm
V_fixture=0
0s        105.3uV    106.5uV    -2.287mV
64ps      546.8uV    377.6uV    18.35mV
166ps     -2.704mV   476.9uV    233mV
243ps     -1.93mV    -1.336mV   343.5mV
294ps     50.26mV    -4.264mV   388.2mV
371ps     188.6mV    -4.665mV   429mV
524ps     363.7mV    117.6mV    462.7mV
639ps     413.7mV    238.5mV    471.2mV
754ps     436.1mV    308.5mV    474.6mV
1.25ns    452.8mV    374.4mV    476.9mV
[Falling waveform]
R_fixture=50.000Ohm
V_fixture=1.200
V_fixture_min=1.140
V_fixture_max=1.300
0s        1.2V       1.14V      1.301V
77ps      1.2V       1.14V      1.29V
243ps     1.2V       1.141V     1.023V
294ps     1.155V     1.145V     965.3mV
422ps     954.7mV    1.131V     886.7mV
575ps     809mV      991.2mV    854.9mV
703ps     764.3mV    876.9mV    846.5mV
805ps     749.3mV    817.3mV    844mV
1.009ns   738.8mV    761.7mV    842.6mV
1.25ns    736.6mV    743mV      842.2mV
[Falling waveform]
R_fixture=50.000Ohm
V_fixture=0
0s        453mV      377.1mV    484.5mV
52ps      452.8mV    376.8mV    434.5mV
128ps     460mV      378.5mV    200.5mV
192ps     463mV      385.1mV    91.7mV
269ps     329.9mV    392.6mV    36.71mV
358ps     121.6mV    338.2mV    13.23mV
473ps     31.64mV    148mV      3.553mV
562ps     11.68mV    61.57mV    1.197mV
677ps     3.197mV    19.93mV    324.5uV
1.25ns    -3.859uV   71.13uV    -13.78uV
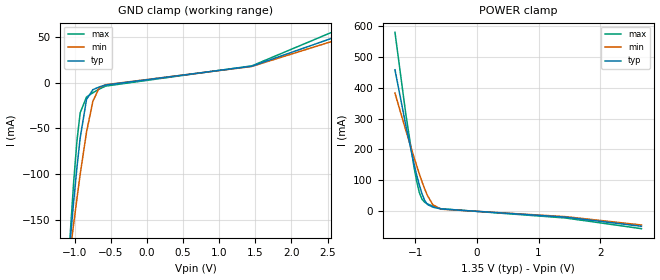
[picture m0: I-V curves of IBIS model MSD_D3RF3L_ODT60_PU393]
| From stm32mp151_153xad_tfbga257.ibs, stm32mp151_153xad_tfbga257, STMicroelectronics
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[Model] MSD_D3RF3L_ODT60_PU393
Model_type   Input
C_comp 2.321pF   2.271pF   2.390pF
Vinh = 810.000mV
Vinl = 540.000mV
[Temperature Range]   25.000   125.000   -40.000
[Voltage Range]   1.350V   1.283V   1.450V
[GND Clamp Reference]   0.00V   0.00V   0.00V
[POWER Clamp Reference]   1.350V   1.283V   1.450V
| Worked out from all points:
|   GND clamp passes 1 mA (typ) near -0.46 V on its own axis
|   POWER clamp passes 1 mA (typ) near -0.18 V on its own axis
[GND Clamp]
-1.318V   -429.1mA   -356.1mA   -544.3mA
-1.098V   -208.6mA   -209.1mA   -216.2mA
-1.055V   -167.2mA   -180.7mA   -158.2mA
-1.011V   -128mA     -152.9mA   -106.4mA
-966.7mV  -91.93mA   -125.8mA   -62.89mA
-922.7mV  -60.29mA   -100mA     -32.9mA
-834.9mV  -18.35mA   -53.83mA   -15.73mA
-747mV    -7.73mA    -20.36mA   -11.1mA
-659.1mV  -4.79mA    -5.686mA   -7.15mA
-571.2mV  -2.69mA    -2.333mA   -3.85mA
1.45V     17.83mA    17.55mA    18.18mA
2.68V     51.67mA    47.86mA    58.89mA
[Power Clamp]
-1.33V    458.4mA    382.6mA    579.8mA
-1.155V   279mA      262.7mA    315.9mA
-1.023V   154.4mA    175.5mA    144.8mA
-978.8mV  117.6mA    147.5mA    97.35mA
-934.9mV  84.31mA    120.5mA    59.99mA
-890.9mV  55.57mA    94.82mA    38.02mA
-847mV    33.86mA    71.24mA    28.22mA
-803mV    21.36mA    50.41mA    23.14mA
-715.1mV  12.67mA    20.47mA    15.72mA
-583.3mV  6.829mA    6.098mA    7.502mA
1.438V    -19.77mA   -18.17mA   -22.54mA
2.668V    -49.45mA   -45.15mA   -57.11mA
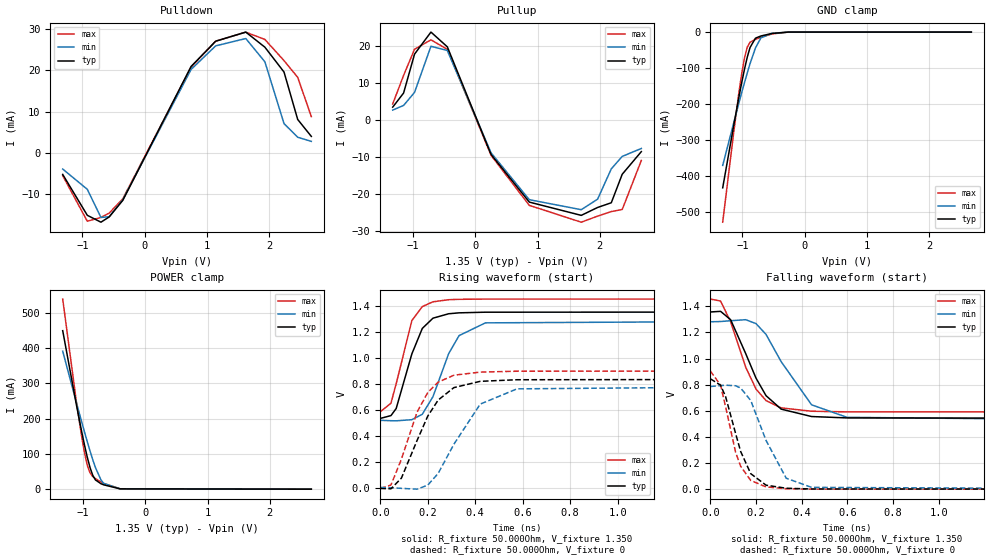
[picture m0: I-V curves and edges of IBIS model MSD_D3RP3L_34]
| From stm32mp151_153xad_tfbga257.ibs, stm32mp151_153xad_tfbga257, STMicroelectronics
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[Model] MSD_D3RP3L_34
Model_type   I/O
C_comp 2.240pF   2.158pF   2.357pF
Vinh = 810.000mV
Vinl = 540.000mV
Vmeas = 675.000mV
Vref = 675.000mV
[Model Spec]
Vinh   810.000mV   777.000mV   860.000mV
Vinl   540.000mV   507.000mV   590.000mV
Vmeas   675.000mV   642.000mV   725.000mV
Vref   675.000mV   642.000mV   725.000mV
[Temperature Range]   25.000   125.000   -40.000
[Voltage Range]   1.350V   1.283V   1.450V
[GND Clamp Reference]   0.00V   0.00V   0.00V
[Pulldown Reference]   0.00V   0.00V   0.00V
[POWER Clamp Reference]   1.350V   1.283V   1.450V
[Pullup Reference]   1.350V   1.283V   1.450V
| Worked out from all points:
|   slope of the pulldown table from 0 to 0.203 V, typ, clamps not added: 31 ohm
|   slope of the pullup table from 0 to 0.203 V, typ, clamps not added: 26.2 ohm
|   GND clamp passes 1 mA (typ) near -0.41 V on its own axis
|   POWER clamp passes 1 mA (typ) near -0.41 V on its own axis
|   rising waveform, R_fixture 50.000Ohm, V_fixture 1.350: 20-80 % time 81.9ps typ, 103ps min, 70.8ps max; typ from 0.532 V to 1.35 V
|   rising waveform, R_fixture 50.000Ohm, V_fixture 0: 20-80 % time 128ps typ, 152ps min, 114ps max; typ from -0.007 V to 0.832 V
|   falling waveform, R_fixture 50.000Ohm, V_fixture 1.350: 20-80 % time 130ps typ, 161ps min, 112ps max; typ from 1.36 V to 0.542 V
|   falling waveform, R_fixture 50.000Ohm, V_fixture 0: 20-80 % time 88.3ps typ, 108ps min, 77ps max; typ from 0.846 V to 0 V
[GND Clamp]
-1.318V   -432mA     -369.8mA   -527.4mA
-1.142V   -260.2mA   -252.4mA   -279.5mA
-1.055V   -177.9mA   -195mA     -164.8mA
-1.011V   -138.8mA   -167mA     -113.9mA
-966.7mV  -102.2mA   -139.6mA   -71.13mA
-922.7mV  -69.41mA   -113.1mA   -41.59mA
-878.8mV  -42.86mA   -87.83mA   -28.26mA
-790.9mV  -16.84mA   -43.84mA   -20.19mA
-703mV    -10.77mA   -15.97mA   -14.59mA
-527.3mV  -3.881mA   -3.286mA   -5.179mA
-263.6mV  -34.33uA   -68.91uA   -22.73uA
2.68V     23.23nA    650.7nA    2.895nA
[Power Clamp]
-1.33V    448.9mA    390.9mA    538.4mA
-1.111V   240.1mA    246mA      248.4mA
-1.023V   161.2mA    189.4mA    146.7mA
-978.8mV  124.3mA    161.6mA    102.6mA
-934.9mV  90.54mA    134.5mA    67.58mA
-890.9mV  61.4mA     108.3mA    46.23mA
-847mV    39.26mA    83.52mA    35.86mA
-803mV    26.02mA    60.85mA    29.84mA
-715.1mV  15.45mA    26.31mA    20.45mA
-671.2mV  12.26mA    16.27mA    16.34mA
-407.6mV  879.8uA    1.157mA    1.067mA
2.668V    -39.9nA    -766.6nA   -3.595nA
[Pulldown]
-1.318V   -5.2mA     -3.9mA     -5.5mA
-922.7mV  -15.09mA   -8.8mA     -16.52mA
-703mV    -16.76mA   -15.61mA   -15.61mA
-571.2mV  -15.49mA   -15.45mA   -14.56mA
-351.5mV  -11.47mA   -11.32mA   -11.1mA
747mV     20.94mA    20.22mA    20.78mA
1.142V    27.04mA    25.92mA    27.06mA
1.626V    29.25mA    27.69mA    29.23mA
1.933V    25.6mA     22.07mA    27.47mA
2.241V    19.58mA    7.1mA      22.34mA
2.461V    8.1mA      3.8mA      18.3mA
2.68V     4mA        2.8mA      8.8mA
[Pullup]
-1.33V    3.4mA      2.605mA    4.252mA
-1.155V   7.2mA      3.862mA    11.96mA
-978.8mV  17.7mA     7.382mA    19.01mA
-715.1mV  23.64mA    19.82mA    21.55mA
-451.5mV  19.66mA    18.67mA    18.98mA
251.5mV   -9.371mA   -8.922mA   -9.594mA
866.7mV   -22.21mA   -21.56mA   -23.09mA
1.702V    -25.79mA   -24.26mA   -27.63mA
1.965V    -23.66mA   -21.42mA   -26mA
2.185V    -22.39mA   -13.25mA   -24.76mA
2.361V    -14.7mA    -9.885mA   -24.21mA
2.668V    -8.6mA     -7.748mA   -10.98mA
[Ramp]
R_load=50.000Ohm
dV/dt_r   492.090mV/103.500ps  462.629mV/126.500ps  526.560mV/91.500ps
dV/dt_f   492.090mV/108.500ps  462.629mV/134.500ps  526.560mV/94.500ps
[Rising waveform]
R_fixture=50.000Ohm
V_fixture=1.350
V_fixture_min=1.283
V_fixture_max=1.450
0s        531.8mV    517.2mV    582.6mV
45ps      553.6mV    514.3mV    648.9mV
67ps      608mV      513.4mV    799mV
133ps     1.028V     522.1mV    1.284V
177ps     1.224V     563.7mV    1.392V
222ps     1.303V     699.4mV    1.429V
288ps     1.337V     1.03V      1.445V
332ps     1.344V     1.169V     1.448V
443ps     1.349V     1.267V     1.45V
2.167ns   1.35V      1.283V     1.45V
[Rising waveform]
R_fixture=50.000Ohm
V_fixture=0
0s        -6.851mV   775.2uV    -6.466mV
45ps      -9.722mV   -1.181mV   19.08mV
89ps      72.69mV    -6.064mV   217.9mV
155ps     362.2mV    -12.39mV   580.1mV
200ps     549.6mV    18.55mV    731mV
244ps     673.5mV    109.2mV    810.9mV
310ps     768.7mV    333mV      864.3mV
421ps     817.2mV    642.1mV    888.1mV
576ps     829.4mV    759.3mV    895mV
2.167ns   832.4mV    782.4mV    896mV
[Falling waveform]
R_fixture=50.000Ohm
V_fixture=1.350
V_fixture_min=1.283
V_fixture_max=1.450
0s        1.357V     1.282V     1.456V
45ps      1.362V     1.284V     1.441V
89ps      1.298V     1.29V      1.282V
155ps     1.038V     1.298V     933.9mV
200ps     850.3mV    1.268V     766.8mV
244ps     715.7mV    1.185V     678mV
310ps     613mV      976.6mV    622.5mV
443ps     556.3mV    646.1mV    597mV
598ps     545.7mV    550.3mV    592mV
2.167ns   542.1mV    523.3mV    590.8mV
[Falling waveform]
R_fixture=50.000Ohm
V_fixture=0
0s        845.7mV    786.1mV    905.7mV
45ps      796.4mV    793.2mV    797.1mV
67ps      708.9mV    796.4mV    631.2mV
111ps     424.9mV    792mV      280.5mV
133ps     288.2mV    774.4mV    174.7mV
177ps     118.6mV    679.1mV    66.44mV
244ps     30.47mV    373mV      17.43mV
332ps     7.048mV    83.94mV    3.414mV
443ps     1.423mV    13.74mV    424.6uV
2.167ns   0V         2.128uV    0V
